VERSION 5.7 ;
  NOWIREEXTENSIONATPIN ON ;
  DIVIDERCHAR "/" ;
  BUSBITCHARS "[]" ;
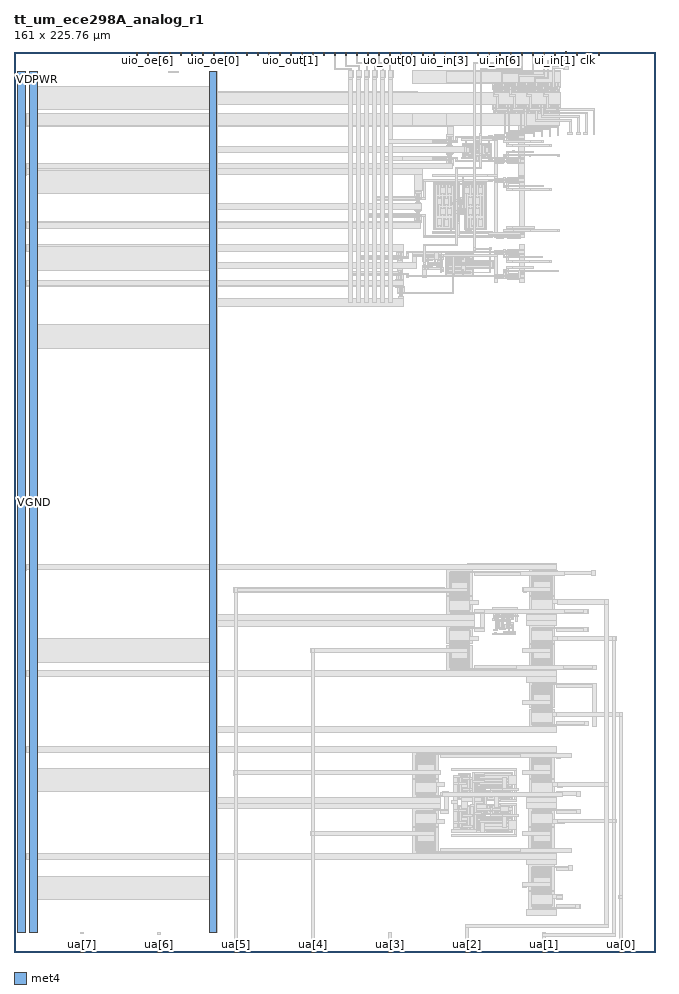
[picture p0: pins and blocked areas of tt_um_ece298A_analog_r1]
MACRO tt_um_ece298A_analog_r1
  CLASS BLOCK ;
  FOREIGN tt_um_ece298A_analog_r1 ;
  ORIGIN 0.000 0.000 ;
  SIZE 161.000 BY 225.760 ;
  PIN clk
    DIRECTION INPUT ;
    USE SIGNAL ;
    PORT
      LAYER met4 ;
        RECT 143.830 224.760 144.130 225.760 ;
    END
  END clk
  PIN ena
    DIRECTION INPUT ;
    USE SIGNAL ;
    PORT
      LAYER met4 ;
        RECT 146.590 224.760 146.890 225.760 ;
    END
  END ena
  PIN rst_n
    DIRECTION INPUT ;
    USE SIGNAL ;
    PORT
      LAYER met4 ;
        RECT 141.070 224.760 141.370 225.760 ;
    END
  END rst_n
  PIN ua[0]
    DIRECTION INOUT ;
    USE SIGNAL ;
    ANTENNADIFFAREA 15.520000 ;
    PORT
      LAYER met4 ;
        RECT 151.810 0.000 152.710 1.000 ;
    END
  END ua[0]
  PIN ua[1]
    DIRECTION INOUT ;
    USE SIGNAL ;
    ANTENNADIFFAREA 31.039999 ;
    PORT
      LAYER met4 ;
        RECT 132.490 0.000 133.390 1.000 ;
    END
  END ua[1]
  PIN ua[2]
    DIRECTION INOUT ;
    USE SIGNAL ;
    ANTENNADIFFAREA 31.039999 ;
    PORT
      LAYER met4 ;
        RECT 113.170 0.000 114.070 1.000 ;
    END
  END ua[2]
  PIN ua[3]
    DIRECTION INOUT ;
    USE SIGNAL ;
    PORT
      LAYER met4 ;
        RECT 93.850 0.000 94.750 1.000 ;
    END
  END ua[3]
  PIN ua[4]
    DIRECTION INOUT ;
    USE SIGNAL ;
    ANTENNADIFFAREA 26.400000 ;
    PORT
      LAYER met4 ;
        RECT 74.530 0.000 75.430 1.000 ;
    END
  END ua[4]
  PIN ua[5]
    DIRECTION INOUT ;
    USE SIGNAL ;
    ANTENNADIFFAREA 26.400000 ;
    PORT
      LAYER met4 ;
        RECT 55.210 0.000 56.110 1.000 ;
    END
  END ua[5]
  PIN ua[6]
    DIRECTION INOUT ;
    USE SIGNAL ;
    PORT
      LAYER met4 ;
        RECT 35.890 0.000 36.790 1.000 ;
    END
  END ua[6]
  PIN ua[7]
    DIRECTION INOUT ;
    USE SIGNAL ;
    PORT
      LAYER met4 ;
        RECT 16.570 0.000 17.470 1.000 ;
    END
  END ua[7]
  PIN ui_in[0]
    DIRECTION INPUT ;
    USE SIGNAL ;
    PORT
      LAYER met4 ;
        RECT 138.310 224.780 138.610 225.780 ;
    END
  END ui_in[0]
  PIN ui_in[1]
    DIRECTION INPUT ;
    USE SIGNAL ;
    ANTENNAGATEAREA 1.980000 ;
    PORT
      LAYER met4 ;
        RECT 135.550 224.760 135.850 225.760 ;
    END
  END ui_in[1]
  PIN ui_in[2]
    DIRECTION INPUT ;
    USE SIGNAL ;
    ANTENNAGATEAREA 1.980000 ;
    PORT
      LAYER met4 ;
        RECT 132.790 224.760 133.090 225.760 ;
    END
  END ui_in[2]
  PIN ui_in[3]
    DIRECTION INPUT ;
    USE SIGNAL ;
    ANTENNAGATEAREA 1.980000 ;
    PORT
      LAYER met4 ;
        RECT 130.030 224.760 130.330 225.760 ;
    END
  END ui_in[3]
  PIN ui_in[4]
    DIRECTION INPUT ;
    USE SIGNAL ;
    ANTENNAGATEAREA 0.951600 ;
    PORT
      LAYER met4 ;
        RECT 127.270 224.760 127.570 225.760 ;
    END
  END ui_in[4]
  PIN ui_in[5]
    DIRECTION INPUT ;
    USE SIGNAL ;
    ANTENNAGATEAREA 4.008000 ;
    ANTENNADIFFAREA 25.557999 ;
    PORT
      LAYER met4 ;
        RECT 124.510 224.760 124.810 225.760 ;
    END
  END ui_in[5]
  PIN ui_in[6]
    DIRECTION INPUT ;
    USE SIGNAL ;
    PORT
      LAYER met4 ;
        RECT 121.750 224.760 122.050 225.760 ;
    END
  END ui_in[6]
  PIN ui_in[7]
    DIRECTION INPUT ;
    USE SIGNAL ;
    PORT
      LAYER met4 ;
        RECT 118.990 224.760 119.290 225.760 ;
    END
  END ui_in[7]
  PIN uio_in[0]
    DIRECTION INPUT ;
    USE SIGNAL ;
    PORT
      LAYER met4 ;
        RECT 116.230 224.760 116.530 225.760 ;
    END
  END uio_in[0]
  PIN uio_in[1]
    DIRECTION INPUT ;
    USE SIGNAL ;
    PORT
      LAYER met4 ;
        RECT 113.470 224.760 113.770 225.760 ;
    END
  END uio_in[1]
  PIN uio_in[2]
    DIRECTION INPUT ;
    USE SIGNAL ;
    PORT
      LAYER met4 ;
        RECT 110.710 224.760 111.010 225.760 ;
    END
  END uio_in[2]
  PIN uio_in[3]
    DIRECTION INPUT ;
    USE SIGNAL ;
    PORT
      LAYER met4 ;
        RECT 107.950 224.760 108.250 225.760 ;
    END
  END uio_in[3]
  PIN uio_in[4]
    DIRECTION INPUT ;
    USE SIGNAL ;
    PORT
      LAYER met4 ;
        RECT 105.190 224.760 105.490 225.760 ;
    END
  END uio_in[4]
  PIN uio_in[5]
    DIRECTION INPUT ;
    USE SIGNAL ;
    PORT
      LAYER met4 ;
        RECT 102.430 224.760 102.730 225.760 ;
    END
  END uio_in[5]
  PIN uio_in[6]
    DIRECTION INPUT ;
    USE SIGNAL ;
    PORT
      LAYER met4 ;
        RECT 99.670 224.760 99.970 225.760 ;
    END
  END uio_in[6]
  PIN uio_in[7]
    DIRECTION INPUT ;
    USE SIGNAL ;
    PORT
      LAYER met4 ;
        RECT 96.910 224.760 97.210 225.760 ;
    END
  END uio_in[7]
  PIN uio_oe[0]
    DIRECTION OUTPUT ;
    USE SIGNAL ;
    PORT
      LAYER met4 ;
        RECT 49.990 224.760 50.290 225.760 ;
    END
  END uio_oe[0]
  PIN uio_oe[1]
    DIRECTION OUTPUT ;
    USE SIGNAL ;
    PORT
      LAYER met4 ;
        RECT 47.230 224.760 47.530 225.760 ;
    END
  END uio_oe[1]
  PIN uio_oe[2]
    DIRECTION OUTPUT ;
    USE SIGNAL ;
    PORT
      LAYER met4 ;
        RECT 44.470 224.760 44.770 225.760 ;
    END
  END uio_oe[2]
  PIN uio_oe[3]
    DIRECTION OUTPUT ;
    USE SIGNAL ;
    PORT
      LAYER met4 ;
        RECT 41.710 224.760 42.010 225.760 ;
    END
  END uio_oe[3]
  PIN uio_oe[4]
    DIRECTION OUTPUT ;
    USE SIGNAL ;
    PORT
      LAYER met4 ;
        RECT 38.950 224.760 39.250 225.760 ;
    END
  END uio_oe[4]
  PIN uio_oe[5]
    DIRECTION OUTPUT ;
    USE SIGNAL ;
    PORT
      LAYER met4 ;
        RECT 36.190 224.760 36.490 225.760 ;
    END
  END uio_oe[5]
  PIN uio_oe[6]
    DIRECTION OUTPUT ;
    USE SIGNAL ;
    PORT
      LAYER met4 ;
        RECT 33.430 224.760 33.730 225.760 ;
    END
  END uio_oe[6]
  PIN uio_oe[7]
    DIRECTION OUTPUT ;
    USE SIGNAL ;
    PORT
      LAYER met4 ;
        RECT 30.670 224.760 30.970 225.760 ;
    END
  END uio_oe[7]
  PIN uio_out[0]
    DIRECTION OUTPUT ;
    USE SIGNAL ;
    PORT
      LAYER met4 ;
        RECT 72.070 224.760 72.370 225.760 ;
    END
  END uio_out[0]
  PIN uio_out[1]
    DIRECTION OUTPUT ;
    USE SIGNAL ;
    PORT
      LAYER met4 ;
        RECT 69.310 224.760 69.610 225.760 ;
    END
  END uio_out[1]
  PIN uio_out[2]
    DIRECTION OUTPUT ;
    USE SIGNAL ;
    PORT
      LAYER met4 ;
        RECT 66.550 224.760 66.850 225.760 ;
    END
  END uio_out[2]
  PIN uio_out[3]
    DIRECTION OUTPUT ;
    USE SIGNAL ;
    PORT
      LAYER met4 ;
        RECT 63.790 224.760 64.090 225.760 ;
    END
  END uio_out[3]
  PIN uio_out[4]
    DIRECTION OUTPUT ;
    USE SIGNAL ;
    PORT
      LAYER met4 ;
        RECT 61.030 224.760 61.330 225.760 ;
    END
  END uio_out[4]
  PIN uio_out[5]
    DIRECTION OUTPUT ;
    USE SIGNAL ;
    PORT
      LAYER met4 ;
        RECT 58.270 224.760 58.570 225.760 ;
    END
  END uio_out[5]
  PIN uio_out[6]
    DIRECTION OUTPUT ;
    USE SIGNAL ;
    PORT
      LAYER met4 ;
        RECT 55.510 224.760 55.810 225.760 ;
    END
  END uio_out[6]
  PIN uio_out[7]
    DIRECTION OUTPUT ;
    USE SIGNAL ;
    PORT
      LAYER met4 ;
        RECT 52.750 224.760 53.050 225.760 ;
    END
  END uio_out[7]
  PIN uo_out[0]
    DIRECTION OUTPUT ;
    USE SIGNAL ;
    ANTENNADIFFAREA 0.429000 ;
    PORT
      LAYER met4 ;
        RECT 94.150 224.760 94.450 225.760 ;
    END
  END uo_out[0]
  PIN uo_out[1]
    DIRECTION OUTPUT ;
    USE SIGNAL ;
    ANTENNADIFFAREA 0.429000 ;
    PORT
      LAYER met4 ;
        RECT 91.390 224.760 91.690 225.760 ;
    END
  END uo_out[1]
  PIN uo_out[2]
    DIRECTION OUTPUT ;
    USE SIGNAL ;
    ANTENNADIFFAREA 0.429000 ;
    PORT
      LAYER met4 ;
        RECT 88.630 224.760 88.930 225.760 ;
    END
  END uo_out[2]
  PIN uo_out[3]
    DIRECTION OUTPUT ;
    USE SIGNAL ;
    ANTENNADIFFAREA 0.429000 ;
    PORT
      LAYER met4 ;
        RECT 85.870 224.760 86.170 225.760 ;
    END
  END uo_out[3]
  PIN uo_out[4]
    DIRECTION OUTPUT ;
    USE SIGNAL ;
    ANTENNADIFFAREA 0.429000 ;
    PORT
      LAYER met4 ;
        RECT 83.110 224.760 83.410 225.760 ;
    END
  END uo_out[4]
  PIN uo_out[5]
    DIRECTION OUTPUT ;
    USE SIGNAL ;
    ANTENNADIFFAREA 0.429000 ;
    PORT
      LAYER met4 ;
        RECT 80.350 224.760 80.650 225.760 ;
    END
  END uo_out[5]
  PIN uo_out[6]
    DIRECTION OUTPUT ;
    USE SIGNAL ;
    PORT
      LAYER met4 ;
        RECT 77.590 224.760 77.890 225.760 ;
    END
  END uo_out[6]
  PIN uo_out[7]
    DIRECTION OUTPUT ;
    USE SIGNAL ;
    PORT
      LAYER met4 ;
        RECT 74.830 224.760 75.130 225.760 ;
    END
  END uo_out[7]
  PIN VDPWR
    DIRECTION INOUT ;
    USE POWER ;
    PORT
      LAYER met4 ;
        RECT 1.000 5.000 3.000 220.760 ;
    END
  END VDPWR
  PIN VGND
    DIRECTION INOUT ;
    USE GROUND ;
    PORT
      LAYER met4 ;
        RECT 4.000 5.000 5.920 220.760 ;
    END
    PORT
      LAYER met4 ;
        RECT 48.990 5.000 50.910 220.760 ;
    END
  END VGND
  OBS
      LAYER nwell ;
        RECT 120.070 216.845 137.010 218.450 ;
      LAYER pwell ;
        RECT 120.430 215.645 124.300 216.555 ;
        RECT 124.570 215.645 128.440 216.555 ;
        RECT 128.710 215.645 132.580 216.555 ;
        RECT 132.850 215.645 136.720 216.555 ;
        RECT 120.430 215.625 120.575 215.645 ;
        RECT 124.570 215.625 124.715 215.645 ;
        RECT 128.710 215.625 128.855 215.645 ;
        RECT 132.850 215.625 132.995 215.645 ;
        RECT 120.405 215.455 120.575 215.625 ;
        RECT 124.545 215.455 124.715 215.625 ;
        RECT 128.685 215.455 128.855 215.625 ;
        RECT 132.825 215.455 132.995 215.625 ;
      LAYER nwell ;
        RECT 120.070 211.415 137.010 213.020 ;
      LAYER pwell ;
        RECT 120.360 210.215 124.230 211.125 ;
        RECT 124.500 210.215 128.370 211.125 ;
        RECT 128.640 210.215 132.510 211.125 ;
        RECT 132.780 210.215 136.650 211.125 ;
        RECT 124.085 210.195 124.230 210.215 ;
        RECT 128.225 210.195 128.370 210.215 ;
        RECT 132.365 210.195 132.510 210.215 ;
        RECT 136.505 210.195 136.650 210.215 ;
        RECT 124.085 210.025 124.255 210.195 ;
        RECT 128.225 210.025 128.395 210.195 ;
        RECT 132.365 210.025 132.535 210.195 ;
        RECT 136.505 210.025 136.675 210.195 ;
      LAYER nwell ;
        RECT 108.420 203.475 110.180 205.080 ;
      LAYER pwell ;
        RECT 115.805 203.380 116.510 204.185 ;
      LAYER nwell ;
        RECT 123.680 203.730 126.490 205.340 ;
      LAYER pwell ;
        RECT 108.850 202.275 109.780 203.185 ;
        RECT 109.675 202.255 109.780 202.275 ;
        RECT 109.675 202.085 109.845 202.255 ;
        RECT 109.675 200.205 109.845 200.375 ;
        RECT 109.675 200.185 109.780 200.205 ;
        RECT 108.850 199.275 109.780 200.185 ;
      LAYER nwell ;
        RECT 112.560 199.670 115.170 202.830 ;
      LAYER pwell ;
        RECT 115.410 199.380 117.110 203.380 ;
      LAYER nwell ;
        RECT 117.260 199.670 119.870 202.830 ;
        RECT 108.420 197.380 110.180 198.985 ;
        RECT 123.680 197.720 126.490 199.330 ;
        RECT 100.450 189.165 102.210 190.770 ;
      LAYER pwell ;
        RECT 100.880 187.965 101.810 188.875 ;
        RECT 101.705 187.945 101.810 187.965 ;
        RECT 101.705 187.775 101.875 187.945 ;
        RECT 101.705 185.895 101.875 186.065 ;
        RECT 101.705 185.875 101.810 185.895 ;
        RECT 100.880 184.965 101.810 185.875 ;
      LAYER nwell ;
        RECT 100.450 183.070 102.210 184.675 ;
      LAYER pwell ;
        RECT 105.330 181.110 110.660 192.990 ;
        RECT 110.780 188.240 112.650 189.260 ;
        RECT 110.780 187.490 112.980 188.240 ;
        RECT 110.780 184.990 112.650 187.490 ;
        RECT 113.130 181.110 118.460 192.990 ;
      LAYER nwell ;
        RECT 123.730 192.770 126.540 194.380 ;
      LAYER pwell ;
        RECT 113.180 180.895 114.880 181.110 ;
      LAYER nwell ;
        RECT 123.730 178.890 126.540 180.500 ;
        RECT 96.000 174.415 97.760 176.020 ;
      LAYER pwell ;
        RECT 96.430 173.215 97.360 174.125 ;
        RECT 97.255 173.195 97.360 173.215 ;
        RECT 97.255 173.025 97.425 173.195 ;
        RECT 97.255 171.145 97.425 171.315 ;
        RECT 97.255 171.125 97.360 171.145 ;
      LAYER nwell ;
        RECT 106.140 171.130 107.400 174.110 ;
      LAYER pwell ;
        RECT 108.160 173.580 115.260 175.680 ;
      LAYER nwell ;
        RECT 123.730 174.700 126.540 176.310 ;
      LAYER pwell ;
        RECT 108.160 171.470 120.260 173.580 ;
        RECT 96.430 170.215 97.360 171.125 ;
      LAYER nwell ;
        RECT 96.000 168.320 97.760 169.925 ;
      LAYER pwell ;
        RECT 108.160 169.370 115.260 171.470 ;
      LAYER nwell ;
        RECT 123.730 168.690 126.540 170.300 ;
        RECT 96.220 165.415 97.980 167.020 ;
      LAYER pwell ;
        RECT 96.620 164.215 97.550 165.125 ;
        RECT 96.620 164.195 96.725 164.215 ;
        RECT 96.555 164.025 96.725 164.195 ;
      LAYER nwell ;
        RECT 108.570 89.370 115.040 96.210 ;
        RECT 129.210 89.410 135.680 96.250 ;
      LAYER pwell ;
        RECT 108.570 84.270 115.040 89.060 ;
      LAYER nwell ;
        RECT 121.340 86.300 122.340 86.500 ;
        RECT 121.340 86.220 125.900 86.300 ;
        RECT 120.900 85.860 125.900 86.220 ;
        RECT 120.380 84.420 125.900 85.860 ;
        RECT 120.380 84.180 123.060 84.420 ;
      LAYER pwell ;
        RECT 129.210 84.310 135.680 89.100 ;
      LAYER nwell ;
        RECT 120.380 83.940 122.740 84.180 ;
      LAYER pwell ;
        RECT 108.560 77.310 115.030 82.100 ;
        RECT 129.200 77.350 135.670 82.140 ;
      LAYER nwell ;
        RECT 108.560 70.160 115.030 77.000 ;
        RECT 129.200 70.200 135.670 77.040 ;
        RECT 129.200 61.210 135.670 68.050 ;
      LAYER pwell ;
        RECT 129.200 56.110 135.670 60.900 ;
      LAYER nwell ;
        RECT 100.080 43.540 106.550 50.380 ;
      LAYER pwell ;
        RECT 100.080 38.440 106.550 43.230 ;
      LAYER nwell ;
        RECT 111.420 38.190 114.530 44.900 ;
        RECT 115.840 41.060 125.030 45.100 ;
        RECT 129.190 43.590 135.660 50.430 ;
      LAYER pwell ;
        RECT 100.070 31.480 106.540 36.270 ;
      LAYER nwell ;
        RECT 100.070 24.330 106.540 31.170 ;
        RECT 111.420 30.090 114.530 36.800 ;
      LAYER pwell ;
        RECT 115.160 34.300 118.230 40.670 ;
        RECT 118.470 38.000 120.930 40.600 ;
        RECT 121.070 37.750 125.030 40.600 ;
        RECT 129.190 38.490 135.660 43.280 ;
        RECT 118.470 34.500 120.930 37.100 ;
        RECT 121.070 34.450 125.030 37.300 ;
      LAYER nwell ;
        RECT 115.840 29.860 125.030 33.900 ;
      LAYER pwell ;
        RECT 129.180 31.530 135.650 36.320 ;
      LAYER nwell ;
        RECT 129.180 24.380 135.650 31.220 ;
        RECT 129.180 15.390 135.650 22.230 ;
      LAYER pwell ;
        RECT 129.180 10.290 135.650 15.080 ;
      LAYER li1 ;
        RECT 120.260 218.175 136.820 218.345 ;
        RECT 120.515 217.375 120.770 218.175 ;
        RECT 120.940 217.205 121.270 218.005 ;
        RECT 121.440 217.375 121.610 218.175 ;
        RECT 121.780 217.205 122.110 218.005 ;
        RECT 122.280 217.375 122.450 218.175 ;
        RECT 122.620 217.205 122.950 218.005 ;
        RECT 123.120 217.375 123.290 218.175 ;
        RECT 123.460 217.205 123.790 218.005 ;
        RECT 123.960 217.375 124.260 218.175 ;
        RECT 124.655 217.375 124.910 218.175 ;
        RECT 125.080 217.205 125.410 218.005 ;
        RECT 125.580 217.375 125.750 218.175 ;
        RECT 125.920 217.205 126.250 218.005 ;
        RECT 126.420 217.375 126.590 218.175 ;
        RECT 126.760 217.205 127.090 218.005 ;
        RECT 127.260 217.375 127.430 218.175 ;
        RECT 127.600 217.205 127.930 218.005 ;
        RECT 128.100 217.375 128.400 218.175 ;
        RECT 128.795 217.375 129.050 218.175 ;
        RECT 129.220 217.205 129.550 218.005 ;
        RECT 129.720 217.375 129.890 218.175 ;
        RECT 130.060 217.205 130.390 218.005 ;
        RECT 130.560 217.375 130.730 218.175 ;
        RECT 130.900 217.205 131.230 218.005 ;
        RECT 131.400 217.375 131.570 218.175 ;
        RECT 131.740 217.205 132.070 218.005 ;
        RECT 132.240 217.375 132.540 218.175 ;
        RECT 132.935 217.375 133.190 218.175 ;
        RECT 133.360 217.205 133.690 218.005 ;
        RECT 133.860 217.375 134.030 218.175 ;
        RECT 134.200 217.205 134.530 218.005 ;
        RECT 134.700 217.375 134.870 218.175 ;
        RECT 135.040 217.205 135.370 218.005 ;
        RECT 135.540 217.375 135.710 218.175 ;
        RECT 135.880 217.205 136.210 218.005 ;
        RECT 136.380 217.375 136.680 218.175 ;
        RECT 120.345 217.040 124.315 217.205 ;
        RECT 124.485 217.040 128.455 217.205 ;
        RECT 128.625 217.040 132.595 217.205 ;
        RECT 132.765 217.040 136.735 217.205 ;
        RECT 120.160 217.035 136.735 217.040 ;
        RECT 120.160 216.445 120.690 217.035 ;
        RECT 120.940 216.615 123.795 216.865 ;
        RECT 123.995 216.445 124.830 217.035 ;
        RECT 125.080 216.615 127.935 216.865 ;
        RECT 128.135 216.445 128.970 217.035 ;
        RECT 129.220 216.615 132.075 216.865 ;
        RECT 132.275 216.445 133.110 217.035 ;
        RECT 133.360 216.615 136.215 216.865 ;
        RECT 136.415 216.445 136.735 217.035 ;
        RECT 120.160 216.440 136.735 216.445 ;
        RECT 120.345 216.255 124.315 216.440 ;
        RECT 124.485 216.255 128.455 216.440 ;
        RECT 128.625 216.255 132.595 216.440 ;
        RECT 132.765 216.255 136.735 216.440 ;
        RECT 120.515 215.625 120.770 216.085 ;
        RECT 120.940 215.795 121.270 216.255 ;
        RECT 121.440 215.625 121.610 216.085 ;
        RECT 121.780 215.795 122.110 216.255 ;
        RECT 122.280 215.625 122.450 216.085 ;
        RECT 122.620 215.795 122.950 216.255 ;
        RECT 123.120 215.625 123.290 216.085 ;
        RECT 123.460 215.795 123.790 216.255 ;
        RECT 123.960 215.625 124.265 216.085 ;
        RECT 124.655 215.625 124.910 216.085 ;
        RECT 125.080 215.795 125.410 216.255 ;
        RECT 125.580 215.625 125.750 216.085 ;
        RECT 125.920 215.795 126.250 216.255 ;
        RECT 126.420 215.625 126.590 216.085 ;
        RECT 126.760 215.795 127.090 216.255 ;
        RECT 127.260 215.625 127.430 216.085 ;
        RECT 127.600 215.795 127.930 216.255 ;
        RECT 128.100 215.625 128.405 216.085 ;
        RECT 128.795 215.625 129.050 216.085 ;
        RECT 129.220 215.795 129.550 216.255 ;
        RECT 129.720 215.625 129.890 216.085 ;
        RECT 130.060 215.795 130.390 216.255 ;
        RECT 130.560 215.625 130.730 216.085 ;
        RECT 130.900 215.795 131.230 216.255 ;
        RECT 131.400 215.625 131.570 216.085 ;
        RECT 131.740 215.795 132.070 216.255 ;
        RECT 132.240 215.625 132.545 216.085 ;
        RECT 132.935 215.625 133.190 216.085 ;
        RECT 133.360 215.795 133.690 216.255 ;
        RECT 133.860 215.625 134.030 216.085 ;
        RECT 134.200 215.795 134.530 216.255 ;
        RECT 134.700 215.625 134.870 216.085 ;
        RECT 135.040 215.795 135.370 216.255 ;
        RECT 135.540 215.625 135.710 216.085 ;
        RECT 135.880 215.795 136.210 216.255 ;
        RECT 136.380 215.625 136.685 216.085 ;
        RECT 120.260 215.455 136.820 215.625 ;
        RECT 120.260 212.745 136.820 212.915 ;
        RECT 120.400 211.945 120.700 212.745 ;
        RECT 120.870 211.775 121.200 212.575 ;
        RECT 121.370 211.945 121.540 212.745 ;
        RECT 121.710 211.775 122.040 212.575 ;
        RECT 122.210 211.945 122.380 212.745 ;
        RECT 122.550 211.775 122.880 212.575 ;
        RECT 123.050 211.945 123.220 212.745 ;
        RECT 123.390 211.775 123.720 212.575 ;
        RECT 123.890 211.945 124.145 212.745 ;
        RECT 124.540 211.945 124.840 212.745 ;
        RECT 125.010 211.775 125.340 212.575 ;
        RECT 125.510 211.945 125.680 212.745 ;
        RECT 125.850 211.775 126.180 212.575 ;
        RECT 126.350 211.945 126.520 212.745 ;
        RECT 126.690 211.775 127.020 212.575 ;
        RECT 127.190 211.945 127.360 212.745 ;
        RECT 127.530 211.775 127.860 212.575 ;
        RECT 128.030 211.945 128.285 212.745 ;
        RECT 128.680 211.945 128.980 212.745 ;
        RECT 129.150 211.775 129.480 212.575 ;
        RECT 129.650 211.945 129.820 212.745 ;
        RECT 129.990 211.775 130.320 212.575 ;
        RECT 130.490 211.945 130.660 212.745 ;
        RECT 130.830 211.775 131.160 212.575 ;
        RECT 131.330 211.945 131.500 212.745 ;
        RECT 131.670 211.775 132.000 212.575 ;
        RECT 132.170 211.945 132.425 212.745 ;
        RECT 132.820 211.945 133.120 212.745 ;
        RECT 133.290 211.775 133.620 212.575 ;
        RECT 133.790 211.945 133.960 212.745 ;
        RECT 134.130 211.775 134.460 212.575 ;
        RECT 134.630 211.945 134.800 212.745 ;
        RECT 134.970 211.775 135.300 212.575 ;
        RECT 135.470 211.945 135.640 212.745 ;
        RECT 135.810 211.775 136.140 212.575 ;
        RECT 136.310 211.945 136.565 212.745 ;
        RECT 120.345 211.610 124.315 211.775 ;
        RECT 124.485 211.610 128.455 211.775 ;
        RECT 128.625 211.610 132.595 211.775 ;
        RECT 132.765 211.610 136.735 211.775 ;
        RECT 120.345 211.605 136.920 211.610 ;
        RECT 120.345 211.015 120.665 211.605 ;
        RECT 120.865 211.185 123.720 211.435 ;
        RECT 123.970 211.015 124.805 211.605 ;
        RECT 125.005 211.185 127.860 211.435 ;
        RECT 128.110 211.015 128.945 211.605 ;
        RECT 129.145 211.185 132.000 211.435 ;
        RECT 132.250 211.015 133.085 211.605 ;
        RECT 133.285 211.185 136.140 211.435 ;
        RECT 136.390 211.015 136.920 211.605 ;
        RECT 120.345 211.010 136.920 211.015 ;
        RECT 120.345 210.825 124.315 211.010 ;
        RECT 124.485 210.825 128.455 211.010 ;
        RECT 128.625 210.825 132.595 211.010 ;
        RECT 132.765 210.825 136.735 211.010 ;
        RECT 120.395 210.195 120.700 210.655 ;
        RECT 120.870 210.365 121.200 210.825 ;
        RECT 121.370 210.195 121.540 210.655 ;
        RECT 121.710 210.365 122.040 210.825 ;
        RECT 122.210 210.195 122.380 210.655 ;
        RECT 122.550 210.365 122.880 210.825 ;
        RECT 123.050 210.195 123.220 210.655 ;
        RECT 123.390 210.365 123.720 210.825 ;
        RECT 123.890 210.195 124.145 210.655 ;
        RECT 124.535 210.195 124.840 210.655 ;
        RECT 125.010 210.365 125.340 210.825 ;
        RECT 125.510 210.195 125.680 210.655 ;
        RECT 125.850 210.365 126.180 210.825 ;
        RECT 126.350 210.195 126.520 210.655 ;
        RECT 126.690 210.365 127.020 210.825 ;
        RECT 127.190 210.195 127.360 210.655 ;
        RECT 127.530 210.365 127.860 210.825 ;
        RECT 128.030 210.195 128.285 210.655 ;
        RECT 128.675 210.195 128.980 210.655 ;
        RECT 129.150 210.365 129.480 210.825 ;
        RECT 129.650 210.195 129.820 210.655 ;
        RECT 129.990 210.365 130.320 210.825 ;
        RECT 130.490 210.195 130.660 210.655 ;
        RECT 130.830 210.365 131.160 210.825 ;
        RECT 131.330 210.195 131.500 210.655 ;
        RECT 131.670 210.365 132.000 210.825 ;
        RECT 132.170 210.195 132.425 210.655 ;
        RECT 132.815 210.195 133.120 210.655 ;
        RECT 133.290 210.365 133.620 210.825 ;
        RECT 133.790 210.195 133.960 210.655 ;
        RECT 134.130 210.365 134.460 210.825 ;
        RECT 134.630 210.195 134.800 210.655 ;
        RECT 134.970 210.365 135.300 210.825 ;
        RECT 135.470 210.195 135.640 210.655 ;
        RECT 135.810 210.365 136.140 210.825 ;
        RECT 136.310 210.195 136.565 210.655 ;
        RECT 120.260 210.025 136.820 210.195 ;
        RECT 108.610 204.805 109.990 204.975 ;
        RECT 121.660 204.910 122.700 205.080 ;
        RECT 108.940 203.655 109.270 204.635 ;
        RECT 109.440 203.665 109.650 204.805 ;
        RECT 121.660 204.430 122.700 204.600 ;
        RECT 108.940 203.520 109.170 203.655 ;
        RECT 115.960 203.630 116.410 204.080 ;
        RECT 121.660 203.950 122.700 204.120 ;
        RECT 122.870 204.035 123.040 204.995 ;
        RECT 123.775 204.055 123.945 205.015 ;
        RECT 124.160 204.930 126.200 205.100 ;
        RECT 124.160 204.450 126.200 204.620 ;
        RECT 124.160 203.970 126.200 204.140 ;
        RECT 108.590 203.190 109.170 203.520 ;
        RECT 109.340 203.480 109.670 203.485 ;
        RECT 109.890 203.480 110.190 203.510 ;
        RECT 109.340 203.250 110.190 203.480 ;
        RECT 109.340 203.245 109.670 203.250 ;
        RECT 109.890 203.220 110.190 203.250 ;
        RECT 108.940 203.055 109.170 203.190 ;
        RECT 108.940 202.425 109.270 203.055 ;
        RECT 109.440 202.255 109.670 203.075 ;
        RECT 112.740 202.480 114.990 202.650 ;
        RECT 108.610 202.085 109.990 202.255 ;
        RECT 108.610 200.205 109.990 200.375 ;
        RECT 108.940 199.405 109.270 200.035 ;
        RECT 108.940 199.270 109.170 199.405 ;
        RECT 109.440 199.385 109.670 200.205 ;
        RECT 112.740 200.020 112.910 202.480 ;
        RECT 113.250 201.980 113.420 201.995 ;
        RECT 113.200 200.510 113.450 201.980 ;
        RECT 113.635 201.910 114.095 202.080 ;
        RECT 113.250 200.505 113.420 200.510 ;
        RECT 113.635 200.420 114.095 200.590 ;
        RECT 114.310 200.505 114.480 201.995 ;
        RECT 114.820 200.020 114.990 202.480 ;
        RECT 115.490 202.435 115.660 202.975 ;
        RECT 115.830 202.890 116.620 203.060 ;
        RECT 115.830 202.350 116.620 202.520 ;
        RECT 116.790 202.435 116.960 202.975 ;
        RECT 117.440 202.480 119.690 202.650 ;
        RECT 116.300 201.730 116.630 201.900 ;
        RECT 115.570 201.020 115.740 201.560 ;
        RECT 116.110 201.020 116.280 201.560 ;
        RECT 116.650 201.020 116.820 201.560 ;
        RECT 115.760 200.680 116.090 200.850 ;
        RECT 112.740 199.850 114.990 200.020 ;
        RECT 115.480 199.755 115.650 200.295 ;
        RECT 115.820 200.210 116.610 200.380 ;
        RECT 115.820 199.670 116.610 199.840 ;
        RECT 116.780 199.755 116.950 200.295 ;
        RECT 117.440 200.020 117.610 202.480 ;
        RECT 117.950 200.505 118.120 201.995 ;
        RECT 118.335 201.910 118.795 202.080 ;
        RECT 118.335 200.420 118.795 200.590 ;
        RECT 119.010 200.505 119.180 201.995 ;
        RECT 119.520 200.020 119.690 202.480 ;
        RECT 117.440 199.850 119.690 200.020 ;
        RECT 108.590 198.940 109.170 199.270 ;
        RECT 109.340 199.210 109.670 199.215 ;
        RECT 109.890 199.210 110.190 199.240 ;
        RECT 109.340 198.980 110.190 199.210 ;
        RECT 109.340 198.975 109.670 198.980 ;
        RECT 109.890 198.950 110.190 198.980 ;
        RECT 108.940 198.805 109.170 198.940 ;
        RECT 121.660 198.900 122.700 199.070 ;
        RECT 108.940 197.825 109.270 198.805 ;
        RECT 109.440 197.655 109.650 198.795 ;
        RECT 121.660 198.420 122.700 198.590 ;
        RECT 121.660 197.940 122.700 198.110 ;
        RECT 122.870 198.025 123.040 198.985 ;
        RECT 123.775 198.045 123.945 199.005 ;
        RECT 124.160 198.920 126.200 199.090 ;
        RECT 124.160 198.440 126.200 198.610 ;
        RECT 124.160 197.960 126.200 198.130 ;
        RECT 108.610 197.485 109.990 197.655 ;
        RECT 121.710 193.950 122.750 194.120 ;
        RECT 121.710 193.470 122.750 193.640 ;
        RECT 121.710 192.990 122.750 193.160 ;
        RECT 122.920 193.075 123.090 194.035 ;
        RECT 123.825 193.095 123.995 194.055 ;
        RECT 124.210 193.970 126.250 194.140 ;
        RECT 124.210 193.490 126.250 193.660 ;
        RECT 124.210 193.010 126.250 193.180 ;
        RECT 105.510 192.640 110.480 192.810 ;
        RECT 100.640 190.495 102.020 190.665 ;
        RECT 100.970 189.345 101.300 190.325 ;
        RECT 101.470 189.355 101.680 190.495 ;
        RECT 100.970 189.210 101.200 189.345 ;
        RECT 100.620 188.880 101.200 189.210 ;
        RECT 101.370 189.170 101.700 189.175 ;
        RECT 101.920 189.170 102.220 189.200 ;
        RECT 101.370 188.940 102.220 189.170 ;
        RECT 101.370 188.935 101.700 188.940 ;
        RECT 101.920 188.910 102.220 188.940 ;
        RECT 100.970 188.745 101.200 188.880 ;
        RECT 100.970 188.115 101.300 188.745 ;
        RECT 101.470 187.945 101.700 188.765 ;
        RECT 100.640 187.775 102.020 187.945 ;
        RECT 100.640 185.895 102.020 186.065 ;
        RECT 100.970 185.095 101.300 185.725 ;
        RECT 100.970 184.960 101.200 185.095 ;
        RECT 101.470 185.075 101.700 185.895 ;
        RECT 100.620 184.630 101.200 184.960 ;
        RECT 101.370 184.900 101.700 184.905 ;
        RECT 101.920 184.900 102.220 184.930 ;
        RECT 101.370 184.670 102.220 184.900 ;
        RECT 101.370 184.665 101.700 184.670 ;
        RECT 101.920 184.640 102.220 184.670 ;
        RECT 100.970 184.495 101.200 184.630 ;
        RECT 100.970 183.515 101.300 184.495 ;
        RECT 101.470 183.345 101.680 184.485 ;
        RECT 100.640 183.175 102.020 183.345 ;
        RECT 105.510 181.460 105.680 192.640 ;
        RECT 110.130 192.590 110.480 192.640 ;
        RECT 110.295 192.390 110.480 192.590 ;
        RECT 106.160 190.000 106.510 192.160 ;
        RECT 106.990 190.000 107.340 192.160 ;
        RECT 107.820 190.000 108.170 192.160 ;
        RECT 108.650 190.000 109.000 192.160 ;
        RECT 109.480 190.000 109.830 192.160 ;
        RECT 106.160 187.310 106.510 189.470 ;
        RECT 106.990 187.310 107.340 189.470 ;
        RECT 107.820 187.310 108.170 189.470 ;
        RECT 108.650 187.310 109.000 189.470 ;
        RECT 109.480 187.310 109.830 189.470 ;
        RECT 106.160 184.630 106.510 186.790 ;
        RECT 106.990 184.630 107.340 186.790 ;
        RECT 107.820 184.630 108.170 186.790 ;
        RECT 108.650 184.630 109.000 186.790 ;
        RECT 109.480 184.630 109.830 186.790 ;
        RECT 106.160 181.940 106.510 184.100 ;
        RECT 106.990 181.940 107.340 184.100 ;
        RECT 107.820 181.940 108.170 184.100 ;
        RECT 108.650 181.940 109.000 184.100 ;
        RECT 109.480 181.940 109.830 184.100 ;
        RECT 110.310 181.460 110.480 192.390 ;
        RECT 113.310 192.640 118.280 192.810 ;
        RECT 113.310 192.620 113.730 192.640 ;
        RECT 113.310 192.490 113.500 192.620 ;
        RECT 110.910 188.305 111.080 188.845 ;
        RECT 111.250 188.760 112.040 188.930 ;
        RECT 111.250 188.220 112.040 188.390 ;
        RECT 112.210 188.305 112.380 188.845 ;
        RECT 111.620 187.540 111.950 187.710 ;
        RECT 112.380 187.640 112.830 188.090 ;
        RECT 110.890 186.830 111.060 187.370 ;
        RECT 111.430 186.830 111.600 187.370 ;
        RECT 111.970 186.830 112.140 187.370 ;
        RECT 111.080 186.490 111.410 186.660 ;
        RECT 110.910 185.355 111.080 185.895 ;
        RECT 111.250 185.810 112.040 185.980 ;
        RECT 111.250 185.270 112.040 185.440 ;
        RECT 112.210 185.355 112.380 185.895 ;
        RECT 105.510 181.290 110.480 181.460 ;
        RECT 113.310 181.460 113.480 192.490 ;
        RECT 113.960 190.000 114.310 192.160 ;
        RECT 114.790 190.000 115.140 192.160 ;
        RECT 115.620 190.000 115.970 192.160 ;
        RECT 116.450 190.000 116.800 192.160 ;
        RECT 117.280 190.000 117.630 192.160 ;
        RECT 113.960 187.310 114.310 189.470 ;
        RECT 114.790 187.310 115.140 189.470 ;
        RECT 115.620 187.310 115.970 189.470 ;
        RECT 116.450 187.310 116.800 189.470 ;
        RECT 117.280 187.310 117.630 189.470 ;
        RECT 113.960 184.630 114.310 186.790 ;
        RECT 114.790 184.630 115.140 186.790 ;
        RECT 115.620 184.630 115.970 186.790 ;
        RECT 116.450 184.630 116.800 186.790 ;
        RECT 117.280 184.630 117.630 186.790 ;
        RECT 113.960 181.940 114.310 184.100 ;
        RECT 114.790 181.940 115.140 184.100 ;
        RECT 115.620 181.940 115.970 184.100 ;
        RECT 116.450 181.940 116.800 184.100 ;
        RECT 117.280 181.940 117.630 184.100 ;
        RECT 118.110 181.460 118.280 192.640 ;
        RECT 113.310 181.290 118.280 181.460 ;
        RECT 121.710 180.070 122.750 180.240 ;
        RECT 121.710 179.590 122.750 179.760 ;
        RECT 121.710 179.110 122.750 179.280 ;
        RECT 122.920 179.195 123.090 180.155 ;
        RECT 123.825 179.215 123.995 180.175 ;
        RECT 124.210 180.090 126.250 180.260 ;
        RECT 124.210 179.610 126.250 179.780 ;
        RECT 124.210 179.130 126.250 179.300 ;
        RECT 96.190 175.745 97.570 175.915 ;
        RECT 121.710 175.880 122.750 176.050 ;
        RECT 96.520 174.595 96.850 175.575 ;
        RECT 97.020 174.605 97.230 175.745 ;
        RECT 108.340 175.330 115.080 175.500 ;
        RECT 121.710 175.400 122.750 175.570 ;
        RECT 96.520 174.460 96.750 174.595 ;
        RECT 96.170 174.130 96.750 174.460 ;
        RECT 96.920 174.420 97.250 174.425 ;
        RECT 97.470 174.420 97.770 174.450 ;
        RECT 96.920 174.190 97.770 174.420 ;
        RECT 96.920 174.185 97.250 174.190 ;
        RECT 97.470 174.160 97.770 174.190 ;
        RECT 96.520 173.995 96.750 174.130 ;
        RECT 96.520 173.365 96.850 173.995 ;
        RECT 97.020 173.195 97.250 174.015 ;
        RECT 102.540 173.890 102.820 174.110 ;
        RECT 102.600 173.670 102.780 173.890 ;
        RECT 103.240 173.850 105.720 174.030 ;
        RECT 103.240 173.670 103.420 173.850 ;
        RECT 102.520 173.250 102.820 173.670 ;
        RECT 103.180 173.250 103.480 173.670 ;
        RECT 103.730 173.610 103.960 173.670 ;
        RECT 104.200 173.610 105.040 173.670 ;
        RECT 103.730 173.430 105.040 173.610 ;
        RECT 96.190 173.025 97.570 173.195 ;
        RECT 102.840 172.550 103.160 172.930 ;
        RECT 103.730 172.290 103.960 173.430 ;
        RECT 104.200 173.370 105.040 173.430 ;
        RECT 104.200 172.890 105.040 172.950 ;
        RECT 105.540 172.890 105.720 173.850 ;
        RECT 108.340 173.920 108.510 175.330 ;
        RECT 108.850 174.460 109.020 174.790 ;
        RECT 109.190 174.760 114.230 174.930 ;
        RECT 109.190 174.320 114.230 174.490 ;
        RECT 114.400 174.460 114.570 174.790 ;
        RECT 114.910 173.920 115.080 175.330 ;
        RECT 121.710 174.920 122.750 175.090 ;
        RECT 122.920 175.005 123.090 175.965 ;
        RECT 123.825 175.025 123.995 175.985 ;
        RECT 124.210 175.900 126.250 176.070 ;
        RECT 124.210 175.420 126.250 175.590 ;
        RECT 124.210 174.940 126.250 175.110 ;
        RECT 108.340 173.750 115.080 173.920 ;
        RECT 106.320 173.610 106.740 173.670 ;
        RECT 106.980 173.610 107.260 173.670 ;
        RECT 106.320 173.430 107.260 173.610 ;
        RECT 106.320 173.370 106.740 173.430 ;
        RECT 106.320 172.890 106.740 172.950 ;
        RECT 104.200 172.710 106.740 172.890 ;
        RECT 104.200 172.650 105.040 172.710 ;
        RECT 105.300 172.490 105.480 172.710 ;
        RECT 106.320 172.650 106.740 172.710 ;
        RECT 104.200 172.290 105.040 172.350 ;
        RECT 102.520 171.810 102.820 172.230 ;
        RECT 103.180 171.810 103.480 172.230 ;
        RECT 103.730 172.110 105.040 172.290 ;
        RECT 105.220 172.170 105.560 172.490 ;
        RECT 105.780 172.170 106.120 172.490 ;
        RECT 106.320 172.290 106.740 172.350 ;
        RECT 106.980 172.290 107.260 173.430 ;
        RECT 108.850 173.400 109.020 173.750 ;
        RECT 103.730 171.810 103.960 172.110 ;
        RECT 104.200 172.050 105.040 172.110 ;
        RECT 102.600 171.570 102.780 171.810 ;
        RECT 103.240 171.570 103.420 171.810 ;
        RECT 104.200 171.570 105.040 171.630 ;
        RECT 105.860 171.570 106.040 172.170 ;
        RECT 106.320 172.110 107.260 172.290 ;
        RECT 106.320 172.050 106.740 172.110 ;
        RECT 106.980 171.810 107.260 172.110 ;
        RECT 108.340 173.230 120.080 173.400 ;
        RECT 108.340 171.820 108.510 173.230 ;
        RECT 108.850 172.360 109.020 172.690 ;
        RECT 109.190 172.660 119.230 172.830 ;
        RECT 109.190 172.220 119.230 172.390 ;
        RECT 119.400 172.360 119.570 172.690 ;
        RECT 119.910 171.820 120.080 173.230 ;
        RECT 108.340 171.650 120.080 171.820 ;
        RECT 106.320 171.570 106.740 171.630 ;
        RECT 102.540 171.350 102.820 171.570 ;
        RECT 103.240 171.390 106.740 171.570 ;
        RECT 104.200 171.330 105.040 171.390 ;
        RECT 106.320 171.330 106.740 171.390 ;
        RECT 96.190 171.145 97.570 171.315 ;
        RECT 108.850 171.300 109.020 171.650 ;
        RECT 96.520 170.345 96.850 170.975 ;
        RECT 96.520 170.210 96.750 170.345 ;
        RECT 97.020 170.325 97.250 171.145 ;
        RECT 108.340 171.130 115.080 171.300 ;
        RECT 96.170 169.880 96.750 170.210 ;
        RECT 96.920 170.150 97.250 170.155 ;
        RECT 97.470 170.150 97.770 170.180 ;
        RECT 96.920 169.920 97.770 170.150 ;
        RECT 96.920 169.915 97.250 169.920 ;
        RECT 97.470 169.890 97.770 169.920 ;
        RECT 96.520 169.745 96.750 169.880 ;
        RECT 96.520 168.765 96.850 169.745 ;
        RECT 97.020 168.595 97.230 169.735 ;
        RECT 108.340 169.720 108.510 171.130 ;
        RECT 108.850 170.260 109.020 170.590 ;
        RECT 109.190 170.560 114.230 170.730 ;
        RECT 109.190 170.120 114.230 170.290 ;
        RECT 114.400 170.260 114.570 170.590 ;
        RECT 114.910 169.720 115.080 171.130 ;
        RECT 121.710 169.870 122.750 170.040 ;
        RECT 108.340 169.550 115.080 169.720 ;
        RECT 121.710 169.390 122.750 169.560 ;
        RECT 121.710 168.910 122.750 169.080 ;
        RECT 122.920 168.995 123.090 169.955 ;
        RECT 123.825 169.015 123.995 169.975 ;
        RECT 124.210 169.890 126.250 170.060 ;
        RECT 124.210 169.410 126.250 169.580 ;
        RECT 124.210 168.930 126.250 169.100 ;
        RECT 96.190 168.425 97.570 168.595 ;
        RECT 96.410 166.745 97.790 166.915 ;
        RECT 96.750 165.605 96.960 166.745 ;
        RECT 97.130 165.595 97.460 166.575 ;
        RECT 97.230 165.460 97.460 165.595 ;
        RECT 96.210 165.420 96.510 165.450 ;
        RECT 96.730 165.420 97.060 165.425 ;
        RECT 96.210 165.190 97.060 165.420 ;
        RECT 96.210 165.160 96.510 165.190 ;
        RECT 96.730 165.185 97.060 165.190 ;
        RECT 97.230 165.130 97.810 165.460 ;
        RECT 96.730 164.195 96.960 165.015 ;
        RECT 97.230 164.995 97.460 165.130 ;
        RECT 97.130 164.365 97.460 164.995 ;
        RECT 96.410 164.025 97.790 164.195 ;
        RECT 109.150 95.860 114.460 96.030 ;
        RECT 129.790 95.900 135.100 96.070 ;
        RECT 109.405 95.345 114.205 95.515 ;
        RECT 130.045 95.385 134.845 95.555 ;
        RECT 109.320 90.090 109.490 95.130 ;
        RECT 109.800 90.090 109.970 95.130 ;
        RECT 110.280 90.090 110.450 95.130 ;
        RECT 110.760 90.090 110.930 95.130 ;
        RECT 111.240 90.090 111.410 95.130 ;
        RECT 111.720 90.090 111.890 95.130 ;
        RECT 112.200 90.090 112.370 95.130 ;
        RECT 112.680 90.090 112.850 95.130 ;
        RECT 113.160 90.090 113.330 95.130 ;
        RECT 113.640 90.090 113.810 95.130 ;
        RECT 114.120 90.090 114.290 95.130 ;
        RECT 129.960 90.130 130.130 95.170 ;
        RECT 130.440 90.130 130.610 95.170 ;
        RECT 130.920 90.130 131.090 95.170 ;
        RECT 131.400 90.130 131.570 95.170 ;
        RECT 131.880 90.130 132.050 95.170 ;
        RECT 132.360 90.130 132.530 95.170 ;
        RECT 132.840 90.130 133.010 95.170 ;
        RECT 133.320 90.130 133.490 95.170 ;
        RECT 133.800 90.130 133.970 95.170 ;
        RECT 134.280 90.130 134.450 95.170 ;
        RECT 134.760 90.130 134.930 95.170 ;
        RECT 109.320 85.300 109.490 88.340 ;
        RECT 109.800 85.300 109.970 88.340 ;
        RECT 110.280 85.300 110.450 88.340 ;
        RECT 110.760 85.300 110.930 88.340 ;
        RECT 111.240 85.300 111.410 88.340 ;
        RECT 111.720 85.300 111.890 88.340 ;
        RECT 112.200 85.300 112.370 88.340 ;
        RECT 112.680 85.300 112.850 88.340 ;
        RECT 113.160 85.300 113.330 88.340 ;
        RECT 113.640 85.300 113.810 88.340 ;
        RECT 114.120 85.300 114.290 88.340 ;
        RECT 121.660 85.940 122.020 86.300 ;
        RECT 109.405 84.960 114.205 85.130 ;
        RECT 109.150 84.450 114.460 84.620 ;
        RECT 120.660 84.380 121.020 85.660 ;
        RECT 121.260 84.380 121.620 85.660 ;
        RECT 121.900 84.380 122.260 85.660 ;
        RECT 122.500 84.380 122.860 85.660 ;
        RECT 123.140 84.620 123.500 85.660 ;
        RECT 123.740 84.620 124.100 85.660 ;
        RECT 124.380 84.620 124.740 85.660 ;
        RECT 124.980 84.620 125.340 85.660 ;
        RECT 120.940 83.780 121.340 84.180 ;
        RECT 122.180 83.780 122.580 84.180 ;
        RECT 123.420 84.020 123.820 84.420 ;
        RECT 124.660 84.020 125.060 84.420 ;
        RECT 120.100 83.460 120.460 83.540 ;
        RECT 121.140 83.460 121.500 83.540 ;
        RECT 120.100 83.260 121.500 83.460 ;
        RECT 120.100 83.180 120.460 83.260 ;
        RECT 121.140 83.180 121.500 83.260 ;
        RECT 122.180 83.140 122.580 83.540 ;
        RECT 123.140 83.300 123.500 83.820 ;
        RECT 123.740 83.300 124.100 83.820 ;
        RECT 124.380 83.300 124.740 83.820 ;
        RECT 124.980 83.300 125.340 83.820 ;
        RECT 125.900 82.980 126.260 86.380 ;
        RECT 129.960 85.340 130.130 88.380 ;
        RECT 130.440 85.340 130.610 88.380 ;
        RECT 130.920 85.340 131.090 88.380 ;
        RECT 131.400 85.340 131.570 88.380 ;
        RECT 131.880 85.340 132.050 88.380 ;
        RECT 132.360 85.340 132.530 88.380 ;
        RECT 132.840 85.340 133.010 88.380 ;
        RECT 133.320 85.340 133.490 88.380 ;
        RECT 133.800 85.340 133.970 88.380 ;
        RECT 134.280 85.340 134.450 88.380 ;
        RECT 134.760 85.340 134.930 88.380 ;
        RECT 130.045 85.000 134.845 85.170 ;
        RECT 129.790 84.490 135.100 84.660 ;
        RECT 109.140 81.750 114.450 81.920 ;
        RECT 109.395 81.240 114.195 81.410 ;
        RECT 120.660 81.140 121.020 82.940 ;
        RECT 121.260 81.140 121.620 82.940 ;
        RECT 121.900 81.140 122.260 82.940 ;
        RECT 122.500 81.140 122.860 82.940 ;
        RECT 123.420 82.580 123.820 82.660 ;
        RECT 124.660 82.580 125.060 82.660 ;
        RECT 123.420 82.380 125.060 82.580 ;
        RECT 123.420 82.260 123.820 82.380 ;
        RECT 124.660 82.260 125.060 82.380 ;
        RECT 123.140 81.140 123.500 82.060 ;
        RECT 123.740 81.140 124.100 82.060 ;
        RECT 124.380 81.140 124.740 82.060 ;
        RECT 124.980 81.140 125.340 82.060 ;
        RECT 129.780 81.790 135.090 81.960 ;
        RECT 130.035 81.280 134.835 81.450 ;
        RECT 109.310 78.030 109.480 81.070 ;
        RECT 109.790 78.030 109.960 81.070 ;
        RECT 110.270 78.030 110.440 81.070 ;
        RECT 110.750 78.030 110.920 81.070 ;
        RECT 111.230 78.030 111.400 81.070 ;
        RECT 111.710 78.030 111.880 81.070 ;
        RECT 112.190 78.030 112.360 81.070 ;
        RECT 112.670 78.030 112.840 81.070 ;
        RECT 113.150 78.030 113.320 81.070 ;
        RECT 113.630 78.030 113.800 81.070 ;
        RECT 114.110 78.030 114.280 81.070 ;
        RECT 120.940 80.540 121.340 80.940 ;
        RECT 120.500 79.580 121.100 80.180 ;
        RECT 122.860 80.140 125.900 80.500 ;
        RECT 129.950 78.070 130.120 81.110 ;
        RECT 130.430 78.070 130.600 81.110 ;
        RECT 130.910 78.070 131.080 81.110 ;
        RECT 131.390 78.070 131.560 81.110 ;
        RECT 131.870 78.070 132.040 81.110 ;
        RECT 132.350 78.070 132.520 81.110 ;
        RECT 132.830 78.070 133.000 81.110 ;
        RECT 133.310 78.070 133.480 81.110 ;
        RECT 133.790 78.070 133.960 81.110 ;
        RECT 134.270 78.070 134.440 81.110 ;
        RECT 134.750 78.070 134.920 81.110 ;
        RECT 109.310 71.240 109.480 76.280 ;
        RECT 109.790 71.240 109.960 76.280 ;
        RECT 110.270 71.240 110.440 76.280 ;
        RECT 110.750 71.240 110.920 76.280 ;
        RECT 111.230 71.240 111.400 76.280 ;
        RECT 111.710 71.240 111.880 76.280 ;
        RECT 112.190 71.240 112.360 76.280 ;
        RECT 112.670 71.240 112.840 76.280 ;
        RECT 113.150 71.240 113.320 76.280 ;
        RECT 113.630 71.240 113.800 76.280 ;
        RECT 114.110 71.240 114.280 76.280 ;
        RECT 129.950 71.280 130.120 76.320 ;
        RECT 130.430 71.280 130.600 76.320 ;
        RECT 130.910 71.280 131.080 76.320 ;
        RECT 131.390 71.280 131.560 76.320 ;
        RECT 131.870 71.280 132.040 76.320 ;
        RECT 132.350 71.280 132.520 76.320 ;
        RECT 132.830 71.280 133.000 76.320 ;
        RECT 133.310 71.280 133.480 76.320 ;
        RECT 133.790 71.280 133.960 76.320 ;
        RECT 134.270 71.280 134.440 76.320 ;
        RECT 134.750 71.280 134.920 76.320 ;
        RECT 109.395 70.855 114.195 71.025 ;
        RECT 130.035 70.895 134.835 71.065 ;
        RECT 109.140 70.340 114.450 70.510 ;
        RECT 129.780 70.380 135.090 70.550 ;
        RECT 129.780 67.700 135.090 67.870 ;
        RECT 130.035 67.185 134.835 67.355 ;
        RECT 129.950 61.930 130.120 66.970 ;
        RECT 130.430 61.930 130.600 66.970 ;
        RECT 130.910 61.930 131.080 66.970 ;
        RECT 131.390 61.930 131.560 66.970 ;
        RECT 131.870 61.930 132.040 66.970 ;
        RECT 132.350 61.930 132.520 66.970 ;
        RECT 132.830 61.930 133.000 66.970 ;
        RECT 133.310 61.930 133.480 66.970 ;
        RECT 133.790 61.930 133.960 66.970 ;
        RECT 134.270 61.930 134.440 66.970 ;
        RECT 134.750 61.930 134.920 66.970 ;
        RECT 129.950 57.140 130.120 60.180 ;
        RECT 130.430 57.140 130.600 60.180 ;
        RECT 130.910 57.140 131.080 60.180 ;
        RECT 131.390 57.140 131.560 60.180 ;
        RECT 131.870 57.140 132.040 60.180 ;
        RECT 132.350 57.140 132.520 60.180 ;
        RECT 132.830 57.140 133.000 60.180 ;
        RECT 133.310 57.140 133.480 60.180 ;
        RECT 133.790 57.140 133.960 60.180 ;
        RECT 134.270 57.140 134.440 60.180 ;
        RECT 134.750 57.140 134.920 60.180 ;
        RECT 130.035 56.800 134.835 56.970 ;
        RECT 129.780 56.290 135.090 56.460 ;
        RECT 100.660 50.030 105.970 50.200 ;
        RECT 129.770 50.080 135.080 50.250 ;
        RECT 100.915 49.515 105.715 49.685 ;
        RECT 130.025 49.565 134.825 49.735 ;
        RECT 100.830 44.260 101.000 49.300 ;
        RECT 101.310 44.260 101.480 49.300 ;
        RECT 101.790 44.260 101.960 49.300 ;
        RECT 102.270 44.260 102.440 49.300 ;
        RECT 102.750 44.260 102.920 49.300 ;
        RECT 103.230 44.260 103.400 49.300 ;
        RECT 103.710 44.260 103.880 49.300 ;
        RECT 104.190 44.260 104.360 49.300 ;
        RECT 104.670 44.260 104.840 49.300 ;
        RECT 105.150 44.260 105.320 49.300 ;
        RECT 105.630 44.260 105.800 49.300 ;
        RECT 117.430 44.920 117.730 45.000 ;
        RECT 116.020 44.750 124.850 44.920 ;
        RECT 111.600 44.550 114.350 44.720 ;
        RECT 111.600 44.200 111.770 44.550 ;
        RECT 111.530 43.900 111.830 44.200 ;
        RECT 112.255 44.040 113.695 44.210 ;
        RECT 100.830 39.470 101.000 42.510 ;
        RECT 101.310 39.470 101.480 42.510 ;
        RECT 101.790 39.470 101.960 42.510 ;
        RECT 102.270 39.470 102.440 42.510 ;
        RECT 102.750 39.470 102.920 42.510 ;
        RECT 103.230 39.470 103.400 42.510 ;
        RECT 103.710 39.470 103.880 42.510 ;
        RECT 104.190 39.470 104.360 42.510 ;
        RECT 104.670 39.470 104.840 42.510 ;
        RECT 105.150 39.470 105.320 42.510 ;
        RECT 105.630 39.470 105.800 42.510 ;
        RECT 100.915 39.130 105.715 39.300 ;
        RECT 100.660 38.620 105.970 38.790 ;
        RECT 111.600 38.540 111.770 43.900 ;
        RECT 112.170 42.115 112.340 43.825 ;
        RECT 112.650 42.115 112.820 43.825 ;
        RECT 113.130 42.115 113.300 43.825 ;
        RECT 113.610 42.115 113.780 43.825 ;
        RECT 112.255 41.730 113.695 41.900 ;
        RECT 112.255 41.190 113.695 41.360 ;
        RECT 112.170 39.265 112.340 40.975 ;
        RECT 112.650 39.265 112.820 40.975 ;
        RECT 113.130 39.265 113.300 40.975 ;
        RECT 113.610 39.265 113.780 40.975 ;
        RECT 112.255 38.880 113.695 39.050 ;
        RECT 114.180 38.540 114.350 44.550 ;
        RECT 116.020 41.410 116.190 44.750 ;
        RECT 117.430 44.700 117.730 44.750 ;
        RECT 116.530 41.895 116.700 44.265 ;
        RECT 116.915 44.180 123.955 44.350 ;
        RECT 116.915 43.390 123.955 43.560 ;
        RECT 116.915 42.600 123.955 42.770 ;
        RECT 116.915 41.810 123.955 41.980 ;
        RECT 124.170 41.895 124.340 44.265 ;
        RECT 124.680 41.410 124.850 44.750 ;
        RECT 129.940 44.310 130.110 49.350 ;
        RECT 130.420 44.310 130.590 49.350 ;
        RECT 130.900 44.310 131.070 49.350 ;
        RECT 131.380 44.310 131.550 49.350 ;
        RECT 131.860 44.310 132.030 49.350 ;
        RECT 132.340 44.310 132.510 49.350 ;
        RECT 132.820 44.310 132.990 49.350 ;
        RECT 133.300 44.310 133.470 49.350 ;
        RECT 133.780 44.310 133.950 49.350 ;
        RECT 134.260 44.310 134.430 49.350 ;
        RECT 134.740 44.310 134.910 49.350 ;
        RECT 116.020 41.240 124.850 41.410 ;
        RECT 111.600 38.370 114.350 38.540 ;
        RECT 115.340 40.320 118.050 40.490 ;
        RECT 111.600 36.450 114.350 36.620 ;
        RECT 100.650 35.920 105.960 36.090 ;
        RECT 100.905 35.410 105.705 35.580 ;
        RECT 100.820 32.200 100.990 35.240 ;
        RECT 101.300 32.200 101.470 35.240 ;
        RECT 101.780 32.200 101.950 35.240 ;
        RECT 102.260 32.200 102.430 35.240 ;
        RECT 102.740 32.200 102.910 35.240 ;
        RECT 103.220 32.200 103.390 35.240 ;
        RECT 103.700 32.200 103.870 35.240 ;
        RECT 104.180 32.200 104.350 35.240 ;
        RECT 104.660 32.200 104.830 35.240 ;
        RECT 105.140 32.200 105.310 35.240 ;
        RECT 105.620 32.200 105.790 35.240 ;
        RECT 111.600 31.100 111.770 36.450 ;
        RECT 112.255 35.940 113.695 36.110 ;
        RECT 112.170 34.015 112.340 35.725 ;
        RECT 112.650 34.015 112.820 35.725 ;
        RECT 113.130 34.015 113.300 35.725 ;
        RECT 113.610 34.015 113.780 35.725 ;
        RECT 112.255 33.630 113.695 33.800 ;
        RECT 112.255 33.090 113.695 33.260 ;
        RECT 112.170 31.165 112.340 32.875 ;
        RECT 112.650 31.165 112.820 32.875 ;
        RECT 113.130 31.165 113.300 32.875 ;
        RECT 113.610 31.165 113.780 32.875 ;
        RECT 111.530 30.800 111.830 31.100 ;
        RECT 100.820 25.410 100.990 30.450 ;
        RECT 101.300 25.410 101.470 30.450 ;
        RECT 101.780 25.410 101.950 30.450 ;
        RECT 102.260 25.410 102.430 30.450 ;
        RECT 102.740 25.410 102.910 30.450 ;
        RECT 103.220 25.410 103.390 30.450 ;
        RECT 103.700 25.410 103.870 30.450 ;
        RECT 104.180 25.410 104.350 30.450 ;
        RECT 104.660 25.410 104.830 30.450 ;
        RECT 105.140 25.410 105.310 30.450 ;
        RECT 105.620 25.410 105.790 30.450 ;
        RECT 111.600 30.440 111.770 30.800 ;
        RECT 112.255 30.780 113.695 30.950 ;
        RECT 114.180 30.440 114.350 36.450 ;
        RECT 115.340 34.650 115.510 40.320 ;
        RECT 115.990 37.680 117.400 39.840 ;
        RECT 115.990 35.130 117.400 37.290 ;
        RECT 117.880 34.650 118.050 40.320 ;
        RECT 118.650 40.250 120.750 40.420 ;
        RECT 118.650 39.400 118.820 40.250 ;
        RECT 119.305 39.740 120.095 39.910 ;
        RECT 118.630 39.100 118.930 39.400 ;
        RECT 118.650 38.350 118.820 39.100 ;
        RECT 119.220 39.030 119.390 39.570 ;
        RECT 120.010 39.030 120.180 39.570 ;
        RECT 119.305 38.690 120.095 38.860 ;
        RECT 120.580 38.350 120.750 40.250 ;
        RECT 121.250 40.250 124.850 40.420 ;
        RECT 121.250 39.400 121.420 40.250 ;
        RECT 121.905 39.740 124.195 39.910 ;
        RECT 121.230 39.100 121.530 39.400 ;
        RECT 118.650 38.180 120.750 38.350 ;
        RECT 121.250 38.100 121.420 39.100 ;
        RECT 121.820 38.780 121.990 39.570 ;
        RECT 124.110 38.780 124.280 39.570 ;
        RECT 121.905 38.440 124.195 38.610 ;
        RECT 124.680 38.100 124.850 40.250 ;
        RECT 129.940 39.520 130.110 42.560 ;
        RECT 130.420 39.520 130.590 42.560 ;
        RECT 130.900 39.520 131.070 42.560 ;
        RECT 131.380 39.520 131.550 42.560 ;
        RECT 131.860 39.520 132.030 42.560 ;
        RECT 132.340 39.520 132.510 42.560 ;
        RECT 132.820 39.520 132.990 42.560 ;
        RECT 133.300 39.520 133.470 42.560 ;
        RECT 133.780 39.520 133.950 42.560 ;
        RECT 134.260 39.520 134.430 42.560 ;
        RECT 134.740 39.520 134.910 42.560 ;
        RECT 130.025 39.180 134.825 39.350 ;
        RECT 129.770 38.670 135.080 38.840 ;
        RECT 121.250 37.930 124.850 38.100 ;
        RECT 121.250 36.950 124.850 37.120 ;
        RECT 118.650 36.750 120.750 36.920 ;
        RECT 118.650 36.000 118.820 36.750 ;
        RECT 119.305 36.240 120.095 36.410 ;
        RECT 118.630 35.700 118.930 36.000 ;
        RECT 118.650 34.850 118.820 35.700 ;
        RECT 119.220 35.530 119.390 36.070 ;
        RECT 120.010 35.530 120.180 36.070 ;
        RECT 119.305 35.190 120.095 35.360 ;
        RECT 120.580 34.850 120.750 36.750 ;
        RECT 121.250 36.000 121.420 36.950 ;
        RECT 121.905 36.440 124.195 36.610 ;
        RECT 121.230 35.700 121.530 36.000 ;
        RECT 118.650 34.680 120.750 34.850 ;
        RECT 121.250 34.800 121.420 35.700 ;
        RECT 121.820 35.480 121.990 36.270 ;
        RECT 124.110 35.480 124.280 36.270 ;
        RECT 121.905 35.140 124.195 35.310 ;
        RECT 124.680 34.800 124.850 36.950 ;
        RECT 129.760 35.970 135.070 36.140 ;
        RECT 130.015 35.460 134.815 35.630 ;
        RECT 115.340 34.480 118.050 34.650 ;
        RECT 121.250 34.630 124.850 34.800 ;
        RECT 111.600 30.270 114.350 30.440 ;
        RECT 116.020 33.550 124.850 33.720 ;
        RECT 116.020 30.210 116.190 33.550 ;
        RECT 116.530 30.695 116.700 33.065 ;
        RECT 116.915 32.980 123.955 33.150 ;
        RECT 116.915 32.190 123.955 32.360 ;
        RECT 116.915 31.400 123.955 31.570 ;
        RECT 116.915 30.610 123.955 30.780 ;
        RECT 124.170 30.695 124.340 33.065 ;
        RECT 118.230 30.210 118.530 30.300 ;
        RECT 124.680 30.210 124.850 33.550 ;
        RECT 129.930 32.250 130.100 35.290 ;
        RECT 130.410 32.250 130.580 35.290 ;
        RECT 130.890 32.250 131.060 35.290 ;
        RECT 131.370 32.250 131.540 35.290 ;
        RECT 131.850 32.250 132.020 35.290 ;
        RECT 132.330 32.250 132.500 35.290 ;
        RECT 132.810 32.250 132.980 35.290 ;
        RECT 133.290 32.250 133.460 35.290 ;
        RECT 133.770 32.250 133.940 35.290 ;
        RECT 134.250 32.250 134.420 35.290 ;
        RECT 134.730 32.250 134.900 35.290 ;
        RECT 116.020 30.040 124.850 30.210 ;
        RECT 118.230 30.000 118.530 30.040 ;
        RECT 129.930 25.460 130.100 30.500 ;
        RECT 130.410 25.460 130.580 30.500 ;
        RECT 130.890 25.460 131.060 30.500 ;
        RECT 131.370 25.460 131.540 30.500 ;
        RECT 131.850 25.460 132.020 30.500 ;
        RECT 132.330 25.460 132.500 30.500 ;
        RECT 132.810 25.460 132.980 30.500 ;
        RECT 133.290 25.460 133.460 30.500 ;
        RECT 133.770 25.460 133.940 30.500 ;
        RECT 134.250 25.460 134.420 30.500 ;
        RECT 134.730 25.460 134.900 30.500 ;
        RECT 100.905 25.025 105.705 25.195 ;
        RECT 130.015 25.075 134.815 25.245 ;
        RECT 100.650 24.510 105.960 24.680 ;
        RECT 129.760 24.560 135.070 24.730 ;
        RECT 129.760 21.880 135.070 22.050 ;
        RECT 130.015 21.365 134.815 21.535 ;
        RECT 129.930 16.110 130.100 21.150 ;
        RECT 130.410 16.110 130.580 21.150 ;
        RECT 130.890 16.110 131.060 21.150 ;
        RECT 131.370 16.110 131.540 21.150 ;
        RECT 131.850 16.110 132.020 21.150 ;
        RECT 132.330 16.110 132.500 21.150 ;
        RECT 132.810 16.110 132.980 21.150 ;
        RECT 133.290 16.110 133.460 21.150 ;
        RECT 133.770 16.110 133.940 21.150 ;
        RECT 134.250 16.110 134.420 21.150 ;
        RECT 134.730 16.110 134.900 21.150 ;
        RECT 129.930 11.320 130.100 14.360 ;
        RECT 130.410 11.320 130.580 14.360 ;
        RECT 130.890 11.320 131.060 14.360 ;
        RECT 131.370 11.320 131.540 14.360 ;
        RECT 131.850 11.320 132.020 14.360 ;
        RECT 132.330 11.320 132.500 14.360 ;
        RECT 132.810 11.320 132.980 14.360 ;
        RECT 133.290 11.320 133.460 14.360 ;
        RECT 133.770 11.320 133.940 14.360 ;
        RECT 134.250 11.320 134.420 14.360 ;
        RECT 134.730 11.320 134.900 14.360 ;
        RECT 130.015 10.980 134.815 11.150 ;
        RECT 129.760 10.470 135.070 10.640 ;
      LAYER met1 ;
        RECT 101.020 220.980 137.010 221.000 ;
        RECT 99.950 218.030 137.010 220.980 ;
        RECT 99.950 218.020 136.820 218.030 ;
        RECT 99.950 217.970 123.000 218.020 ;
        RECT 99.950 217.960 108.520 217.970 ;
        RECT 120.130 217.040 120.640 217.100 ;
        RECT 124.270 217.040 124.780 217.100 ;
        RECT 128.410 217.040 128.920 217.100 ;
        RECT 132.550 217.040 133.060 217.100 ;
        RECT 120.110 216.440 120.660 217.040 ;
        RECT 120.930 216.600 123.810 216.890 ;
        RECT 124.250 216.440 124.800 217.040 ;
        RECT 125.070 216.600 127.950 216.890 ;
        RECT 128.390 216.440 128.940 217.040 ;
        RECT 129.210 216.600 132.090 216.890 ;
        RECT 132.530 216.440 133.080 217.040 ;
        RECT 133.350 216.600 136.230 216.890 ;
        RECT 120.130 216.380 120.640 216.440 ;
        RECT 124.270 216.380 124.780 216.440 ;
        RECT 128.410 216.380 128.920 216.440 ;
        RECT 132.550 216.380 133.060 216.440 ;
        RECT 49.060 215.730 101.200 215.740 ;
        RECT 48.930 215.700 101.200 215.730 ;
        RECT 120.260 215.700 136.820 215.780 ;
        RECT 48.930 212.710 137.010 215.700 ;
        RECT 48.930 212.650 51.060 212.710 ;
        RECT 79.370 212.690 137.010 212.710 ;
        RECT 99.960 212.680 137.010 212.690 ;
        RECT 115.030 212.670 137.010 212.680 ;
        RECT 120.260 212.590 136.820 212.670 ;
        RECT 124.020 211.610 124.530 211.670 ;
        RECT 128.160 211.610 128.670 211.670 ;
        RECT 132.300 211.610 132.810 211.670 ;
        RECT 136.440 211.610 136.950 211.670 ;
        RECT 120.850 211.170 123.730 211.460 ;
        RECT 124.000 211.010 124.550 211.610 ;
        RECT 124.990 211.170 127.870 211.460 ;
        RECT 128.140 211.010 128.690 211.610 ;
        RECT 129.130 211.170 132.010 211.460 ;
        RECT 132.280 211.010 132.830 211.610 ;
        RECT 133.270 211.170 136.150 211.460 ;
        RECT 136.420 211.010 136.970 211.610 ;
        RECT 124.020 210.950 124.530 211.010 ;
        RECT 128.160 210.950 128.670 211.010 ;
        RECT 132.300 210.950 132.810 211.010 ;
        RECT 136.440 210.950 136.950 211.010 ;
        RECT 120.260 210.340 136.820 210.350 ;
        RECT 0.950 210.310 3.030 210.320 ;
        RECT 99.950 210.310 136.950 210.340 ;
        RECT 0.950 207.320 136.950 210.310 ;
        RECT 0.950 207.090 110.150 207.320 ;
        RECT 114.970 207.310 136.950 207.320 ;
        RECT 2.000 207.070 110.150 207.090 ;
        RECT 108.420 207.060 110.150 207.070 ;
        RECT 108.630 205.130 110.150 207.060 ;
        RECT 126.640 205.170 128.020 207.310 ;
        RECT 108.610 204.650 110.150 205.130 ;
        RECT 121.010 205.100 122.680 205.110 ;
        RECT 120.520 204.880 122.680 205.100 ;
        RECT 110.810 204.280 120.110 204.680 ;
        RECT 104.030 203.780 105.010 203.810 ;
        RECT 104.030 203.580 108.790 203.780 ;
        RECT 104.030 203.520 108.920 203.580 ;
        RECT 109.830 203.520 110.250 203.540 ;
        RECT 110.810 203.520 111.210 204.280 ;
        RECT 115.960 203.630 116.410 204.080 ;
        RECT 104.030 203.190 108.940 203.520 ;
        RECT 109.830 203.190 111.210 203.520 ;
        RECT 116.710 203.380 116.910 204.280 ;
        RECT 120.520 204.150 121.380 204.880 ;
        RECT 121.680 204.310 122.680 204.700 ;
        RECT 120.520 204.000 122.680 204.150 ;
        RECT 122.840 204.030 123.120 205.140 ;
        RECT 123.500 204.920 123.970 205.020 ;
        RECT 124.160 204.920 128.020 205.170 ;
        RECT 123.500 204.630 123.975 204.920 ;
        RECT 124.180 204.900 126.180 204.920 ;
        RECT 123.500 204.440 123.970 204.630 ;
        RECT 123.500 204.150 123.975 204.440 ;
        RECT 124.150 204.340 126.200 204.730 ;
        RECT 124.180 204.150 126.180 204.170 ;
        RECT 126.490 204.150 128.020 204.920 ;
        RECT 123.500 204.090 123.970 204.150 ;
        RECT 123.490 204.060 123.970 204.090 ;
        RECT 123.490 204.055 123.945 204.060 ;
        RECT 119.740 203.980 122.680 204.000 ;
        RECT 118.950 203.920 122.680 203.980 ;
        RECT 118.950 203.670 121.270 203.920 ;
        RECT 118.950 203.630 120.160 203.670 ;
        RECT 104.030 203.130 108.920 203.190 ;
        RECT 104.030 202.800 108.790 203.130 ;
        RECT 109.890 203.120 111.210 203.190 ;
        RECT 116.310 203.180 116.910 203.380 ;
        RECT 116.310 203.090 116.610 203.180 ;
        RECT 115.490 202.850 115.660 202.975 ;
        RECT 115.850 202.880 116.610 203.090 ;
        RECT 116.790 202.930 116.960 202.975 ;
        RECT 115.850 202.860 116.600 202.880 ;
        RECT 104.030 202.770 105.010 202.800 ;
        RECT 115.460 202.560 115.690 202.850 ;
        RECT 115.490 202.435 115.660 202.560 ;
        RECT 108.610 202.090 109.990 202.410 ;
        RECT 113.710 202.180 115.160 202.430 ;
        RECT 115.850 202.320 116.600 202.550 ;
        RECT 116.760 202.480 117.160 202.930 ;
        RECT 116.790 202.435 116.960 202.480 ;
        RECT 113.710 202.110 114.110 202.180 ;
        RECT 108.520 202.040 110.280 202.090 ;
        RECT 113.655 202.080 114.110 202.110 ;
        RECT 113.150 202.040 113.490 202.070 ;
        RECT 108.520 202.030 113.490 202.040 ;
        RECT 49.160 202.010 83.730 202.030 ;
        RECT 96.010 202.010 113.490 202.030 ;
        RECT 49.160 201.990 113.490 202.010 ;
        RECT 48.920 200.530 113.490 201.990 ;
        RECT 113.655 201.880 114.075 202.080 ;
        RECT 114.310 201.830 114.480 201.995 ;
        RECT 114.910 201.980 115.160 202.180 ;
        RECT 116.160 201.980 116.410 202.320 ;
        RECT 117.360 202.280 118.710 202.480 ;
        RECT 114.280 200.670 114.510 201.830 ;
        RECT 114.910 201.780 116.610 201.980 ;
        RECT 114.910 201.680 115.710 201.780 ;
        RECT 116.320 201.700 116.610 201.780 ;
        RECT 115.510 201.540 115.710 201.680 ;
        RECT 115.510 201.080 115.770 201.540 ;
        RECT 115.540 201.040 115.770 201.080 ;
        RECT 116.010 201.030 116.410 201.560 ;
        RECT 116.620 201.040 116.850 201.540 ;
        RECT 115.780 200.780 116.070 200.880 ;
        RECT 116.660 200.780 116.810 201.040 ;
        RECT 117.360 200.780 117.560 202.280 ;
        RECT 118.360 202.110 118.710 202.280 ;
        RECT 117.950 201.830 118.120 201.995 ;
        RECT 118.355 201.880 118.775 202.110 ;
        RECT 119.010 201.830 119.180 201.995 ;
        RECT 48.920 200.510 96.070 200.530 ;
        RECT 49.160 200.500 83.730 200.510 ;
        RECT 108.520 200.450 113.490 200.530 ;
        RECT 108.520 200.390 110.280 200.450 ;
        RECT 113.150 200.420 113.490 200.450 ;
        RECT 113.655 200.390 114.075 200.620 ;
        RECT 114.310 200.505 114.480 200.670 ;
        RECT 115.780 200.650 117.560 200.780 ;
        RECT 117.920 200.670 118.150 201.830 ;
        RECT 115.810 200.580 117.560 200.650 ;
        RECT 116.160 200.410 116.410 200.580 ;
        RECT 117.950 200.505 118.120 200.670 ;
        RECT 118.355 200.610 118.775 200.620 ;
        RECT 108.610 200.050 109.990 200.390 ;
        RECT 112.910 200.075 113.170 200.080 ;
        RECT 113.720 200.075 114.065 200.390 ;
        RECT 115.480 200.170 115.650 200.295 ;
        RECT 115.840 200.180 116.590 200.410 ;
        RECT 118.350 200.380 118.790 200.610 ;
        RECT 118.960 200.530 119.310 201.830 ;
        RECT 119.010 200.505 119.180 200.530 ;
        RECT 116.780 200.230 116.950 200.295 ;
        RECT 116.760 200.170 117.110 200.230 ;
        RECT 112.910 199.780 114.065 200.075 ;
        RECT 115.450 199.880 115.680 200.170 ;
        RECT 116.750 199.880 117.110 200.170 ;
        RECT 91.970 199.620 93.010 199.650 ;
        RECT 104.010 199.620 104.990 199.650 ;
        RECT 91.970 198.640 98.500 199.620 ;
        RECT 104.010 199.330 108.790 199.620 ;
        RECT 113.210 199.330 114.065 199.780 ;
        RECT 115.480 199.755 115.650 199.880 ;
        RECT 115.840 199.640 116.590 199.870 ;
        RECT 116.760 199.780 117.110 199.880 ;
        RECT 118.395 200.035 118.770 200.380 ;
        RECT 119.175 200.035 119.620 200.125 ;
        RECT 118.395 199.850 119.620 200.035 ;
        RECT 116.780 199.755 116.950 199.780 ;
        RECT 115.910 199.480 116.510 199.640 ;
        RECT 118.395 199.330 118.770 199.850 ;
        RECT 119.175 199.760 119.620 199.850 ;
        RECT 119.010 199.330 119.260 199.335 ;
        RECT 104.010 199.270 108.920 199.330 ;
        RECT 110.040 199.270 111.210 199.320 ;
        RECT 104.010 198.940 108.940 199.270 ;
        RECT 104.010 198.880 108.920 198.940 ;
        RECT 109.830 198.920 111.210 199.270 ;
        RECT 112.265 199.300 120.110 199.330 ;
        RECT 112.265 198.940 120.140 199.300 ;
        RECT 120.520 199.100 121.270 203.670 ;
        RECT 122.850 203.440 123.110 204.030 ;
        RECT 122.820 203.180 123.140 203.440 ;
        RECT 122.850 203.150 123.110 203.180 ;
        RECT 123.490 202.505 123.940 204.055 ;
        RECT 124.150 203.900 128.020 204.150 ;
        RECT 123.490 202.060 125.575 202.505 ;
        RECT 124.030 202.055 125.575 202.060 ;
        RECT 123.500 200.915 123.950 200.920 ;
        RECT 123.500 200.465 125.585 200.915 ;
        RECT 122.840 200.100 123.120 200.150 ;
        RECT 122.750 199.580 123.200 200.100 ;
        RECT 112.265 198.930 120.110 198.940 ;
        RECT 113.720 198.925 114.065 198.930 ;
        RECT 118.395 198.925 118.770 198.930 ;
        RECT 104.010 198.640 108.790 198.880 ;
        RECT 91.970 198.610 93.010 198.640 ;
        RECT 104.010 198.610 104.990 198.640 ;
        RECT 110.810 198.630 111.210 198.920 ;
        RECT 120.520 198.870 122.680 199.100 ;
        RECT 110.810 198.230 120.150 198.630 ;
        RECT 120.520 198.230 121.380 198.870 ;
        RECT 121.680 198.300 122.680 198.690 ;
        RECT 120.500 198.140 121.380 198.230 ;
        RECT 120.500 197.910 122.680 198.140 ;
        RECT 122.840 198.020 123.120 199.580 ;
        RECT 123.500 199.010 123.950 200.465 ;
        RECT 126.640 199.400 128.020 203.900 ;
        RECT 129.200 203.440 129.460 203.470 ;
        RECT 129.200 203.180 132.730 203.440 ;
        RECT 129.200 203.150 129.460 203.180 ;
        RECT 128.675 202.505 129.125 202.535 ;
        RECT 128.675 202.055 134.795 202.505 ;
        RECT 128.675 202.025 129.125 202.055 ;
        RECT 129.260 199.960 129.540 199.990 ;
        RECT 136.440 199.960 136.720 199.990 ;
        RECT 129.260 199.680 136.720 199.960 ;
        RECT 129.260 199.650 129.540 199.680 ;
        RECT 136.440 199.650 136.720 199.680 ;
        RECT 126.610 199.160 128.020 199.400 ;
        RECT 123.500 198.910 123.970 199.010 ;
        RECT 124.160 198.910 128.020 199.160 ;
        RECT 123.500 198.620 123.975 198.910 ;
        RECT 124.180 198.890 126.180 198.910 ;
        RECT 123.500 198.430 123.970 198.620 ;
        RECT 123.500 198.140 123.975 198.430 ;
        RECT 124.150 198.330 126.200 198.720 ;
        RECT 124.180 198.140 126.180 198.160 ;
        RECT 126.490 198.140 128.020 198.910 ;
        RECT 123.500 198.050 123.970 198.140 ;
        RECT 123.775 198.045 123.945 198.050 ;
        RECT 0.960 197.740 83.830 197.750 ;
        RECT 108.610 197.740 109.990 197.810 ;
        RECT 0.960 196.500 110.110 197.740 ;
        RECT 0.960 194.990 102.370 196.500 ;
        RECT 0.960 194.910 83.830 194.990 ;
        RECT 0.960 194.890 3.040 194.910 ;
        RECT 100.490 191.100 102.370 194.990 ;
        RECT 117.640 194.990 118.770 195.000 ;
        RECT 120.500 194.990 121.290 197.910 ;
        RECT 124.150 197.890 128.020 198.140 ;
        RECT 117.640 194.480 121.320 194.990 ;
        RECT 126.670 194.740 128.020 197.890 ;
        RECT 126.670 194.510 128.070 194.740 ;
        RECT 120.560 194.150 121.320 194.480 ;
        RECT 126.690 194.210 128.070 194.510 ;
        RECT 120.560 194.090 122.730 194.150 ;
        RECT 120.570 193.920 122.730 194.090 ;
        RECT 102.840 193.710 119.120 193.790 ;
        RECT 102.840 193.330 120.150 193.710 ;
        RECT 102.840 193.290 119.120 193.330 ;
        RECT 100.660 190.820 102.180 191.100 ;
        RECT 100.640 190.340 102.180 190.820 ;
        RECT 89.960 189.490 91.000 189.520 ;
        RECT 89.960 189.270 100.740 189.490 ;
        RECT 89.960 189.210 100.950 189.270 ;
        RECT 101.860 189.210 102.280 189.230 ;
        RECT 102.840 189.210 103.240 193.290 ;
        RECT 110.030 192.290 110.630 192.890 ;
        RECT 106.210 190.025 106.460 192.130 ;
        RECT 107.040 191.890 107.290 192.130 ;
        RECT 107.870 191.890 108.120 192.130 ;
        RECT 108.700 191.890 108.950 192.130 ;
        RECT 109.530 191.890 109.780 192.130 ;
        RECT 107.040 190.190 108.130 191.890 ;
        RECT 108.700 190.190 109.780 191.890 ;
        RECT 107.040 190.025 107.290 190.190 ;
        RECT 107.870 190.025 108.120 190.190 ;
        RECT 108.700 190.025 108.950 190.190 ;
        RECT 109.530 190.025 109.780 190.190 ;
        RECT 89.960 188.880 100.970 189.210 ;
        RECT 101.860 188.880 103.240 189.210 ;
        RECT 106.210 189.290 106.460 189.445 ;
        RECT 107.040 189.290 107.290 189.445 ;
        RECT 106.210 189.090 107.290 189.290 ;
        RECT 89.960 188.820 100.950 188.880 ;
        RECT 89.960 188.510 100.740 188.820 ;
        RECT 101.920 188.810 103.240 188.880 ;
        RECT 89.960 188.480 91.000 188.510 ;
        RECT 100.640 187.780 102.020 188.100 ;
        RECT 49.390 187.730 83.960 187.740 ;
        RECT 48.940 187.720 83.960 187.730 ;
        RECT 100.550 187.720 102.310 187.780 ;
        RECT 48.940 186.220 102.310 187.720 ;
        RECT 48.940 186.210 83.960 186.220 ;
        RECT 48.940 186.180 51.080 186.210 ;
        RECT 100.550 186.080 102.310 186.220 ;
        RECT 106.130 187.590 107.290 189.090 ;
        RECT 100.640 185.740 102.020 186.080 ;
        RECT 87.970 185.340 89.040 185.380 ;
        RECT 87.970 185.020 100.760 185.340 ;
        RECT 87.970 184.960 100.950 185.020 ;
        RECT 102.070 184.960 103.240 185.010 ;
        RECT 106.130 184.990 106.530 187.590 ;
        RECT 107.040 187.340 107.290 187.590 ;
        RECT 107.870 189.090 108.120 189.445 ;
        RECT 108.700 189.090 108.950 189.445 ;
        RECT 107.870 187.390 108.950 189.090 ;
        RECT 107.870 187.340 108.120 187.390 ;
        RECT 108.700 187.340 108.950 187.390 ;
        RECT 109.530 188.090 109.780 189.445 ;
        RECT 111.430 188.960 111.730 193.290 ;
        RECT 120.570 193.190 121.430 193.920 ;
        RECT 121.730 193.350 122.730 193.740 ;
        RECT 120.570 192.960 122.730 193.190 ;
        RECT 122.890 193.070 123.170 194.180 ;
        RECT 123.550 193.960 124.020 194.060 ;
        RECT 124.210 193.960 128.070 194.210 ;
        RECT 123.550 193.670 124.025 193.960 ;
        RECT 124.230 193.940 126.230 193.960 ;
        RECT 123.550 193.480 124.020 193.670 ;
        RECT 123.550 193.190 124.025 193.480 ;
        RECT 124.200 193.380 126.250 193.770 ;
        RECT 124.230 193.190 126.230 193.210 ;
        RECT 126.540 193.190 128.070 193.960 ;
        RECT 123.550 193.140 124.020 193.190 ;
        RECT 123.540 193.100 124.020 193.140 ;
        RECT 123.540 193.095 123.995 193.100 ;
        RECT 113.230 192.390 113.830 192.890 ;
        RECT 114.010 191.890 114.260 192.130 ;
        RECT 114.840 191.890 115.090 192.130 ;
        RECT 115.670 191.890 115.920 192.130 ;
        RECT 113.030 190.390 114.260 191.890 ;
        RECT 110.910 188.790 111.080 188.845 ;
        RECT 110.730 188.740 111.080 188.790 ;
        RECT 110.730 188.340 111.130 188.740 ;
        RECT 111.270 188.730 112.020 188.960 ;
        RECT 112.210 188.720 112.380 188.845 ;
        RECT 112.180 188.430 112.410 188.720 ;
        RECT 110.910 188.305 111.080 188.340 ;
        RECT 111.270 188.190 112.020 188.420 ;
        RECT 112.210 188.305 112.380 188.430 ;
        RECT 109.530 187.990 111.030 188.090 ;
        RECT 111.480 187.990 111.730 188.190 ;
        RECT 109.530 187.790 111.730 187.990 ;
        RECT 109.530 187.590 111.930 187.790 ;
        RECT 112.380 187.640 112.830 188.090 ;
        RECT 109.530 187.490 111.030 187.590 ;
        RECT 111.640 187.510 111.930 187.590 ;
        RECT 109.530 187.340 109.780 187.490 ;
        RECT 110.830 187.350 111.030 187.490 ;
        RECT 110.830 186.890 111.090 187.350 ;
        RECT 110.860 186.850 111.090 186.890 ;
        RECT 111.330 186.840 111.730 187.370 ;
        RECT 111.940 186.850 112.170 187.350 ;
        RECT 107.040 186.590 107.290 186.760 ;
        RECT 107.870 186.590 108.120 186.760 ;
        RECT 108.700 186.590 108.950 186.760 ;
        RECT 109.530 186.590 109.780 186.760 ;
        RECT 87.970 184.630 100.970 184.960 ;
        RECT 87.970 184.570 100.950 184.630 ;
        RECT 101.860 184.610 103.240 184.960 ;
        RECT 106.210 184.655 106.460 184.990 ;
        RECT 107.040 184.890 108.130 186.590 ;
        RECT 108.700 184.890 109.780 186.590 ;
        RECT 111.100 186.590 111.390 186.690 ;
        RECT 111.980 186.590 112.130 186.850 ;
        RECT 113.030 186.590 113.630 190.390 ;
        RECT 114.010 190.025 114.260 190.390 ;
        RECT 114.830 190.290 115.920 191.890 ;
        RECT 114.840 190.025 115.090 190.290 ;
        RECT 115.670 190.025 115.920 190.290 ;
        RECT 116.500 191.790 116.750 192.130 ;
        RECT 117.330 191.790 117.580 192.130 ;
        RECT 116.500 190.190 117.580 191.790 ;
        RECT 116.500 190.025 116.750 190.190 ;
        RECT 117.330 190.025 117.580 190.190 ;
        RECT 114.010 189.190 114.260 189.445 ;
        RECT 114.840 189.190 115.090 189.445 ;
        RECT 114.010 187.590 115.090 189.190 ;
        RECT 114.010 187.340 114.260 187.590 ;
        RECT 114.840 187.340 115.090 187.590 ;
        RECT 115.670 189.190 115.920 189.445 ;
        RECT 116.500 189.190 116.750 189.445 ;
        RECT 115.670 187.590 116.750 189.190 ;
        RECT 117.330 188.390 117.580 189.445 ;
        RECT 115.670 187.340 115.920 187.590 ;
        RECT 116.500 187.340 116.750 187.590 ;
        RECT 111.100 186.460 113.630 186.590 ;
        RECT 111.130 186.390 113.630 186.460 ;
        RECT 111.480 186.200 113.630 186.390 ;
        RECT 111.480 186.010 111.730 186.200 ;
        RECT 111.960 186.190 113.630 186.200 ;
        RECT 114.010 186.590 114.260 186.760 ;
        RECT 114.840 186.590 115.090 186.760 ;
        RECT 110.910 185.840 111.080 185.895 ;
        RECT 110.730 185.770 111.080 185.840 ;
        RECT 111.270 185.780 112.020 186.010 ;
        RECT 112.210 185.770 112.380 185.895 ;
        RECT 110.730 185.480 111.110 185.770 ;
        RECT 112.180 185.480 112.410 185.770 ;
        RECT 110.730 185.440 111.080 185.480 ;
        RECT 110.910 185.355 111.080 185.440 ;
        RECT 111.270 185.240 112.020 185.470 ;
        RECT 112.210 185.355 112.380 185.480 ;
        RECT 107.040 184.655 107.290 184.890 ;
        RECT 107.870 184.655 108.120 184.890 ;
        RECT 108.700 184.655 108.950 184.890 ;
        RECT 109.530 184.655 109.780 184.890 ;
        RECT 87.970 184.360 100.760 184.570 ;
        RECT 87.970 184.330 89.040 184.360 ;
        RECT 100.640 183.280 102.020 183.500 ;
        RECT 0.960 183.020 102.020 183.280 ;
        RECT 0.960 181.460 101.880 183.020 ;
        RECT 2.450 181.450 101.880 181.460 ;
        RECT 102.840 179.710 103.240 184.610 ;
        RECT 106.210 183.890 106.460 184.075 ;
        RECT 107.040 183.890 107.290 184.075 ;
        RECT 106.210 182.190 107.290 183.890 ;
        RECT 106.210 181.970 106.460 182.190 ;
        RECT 107.040 181.970 107.290 182.190 ;
        RECT 107.870 183.790 108.120 184.075 ;
        RECT 108.700 183.790 108.950 184.075 ;
        RECT 107.870 182.090 108.950 183.790 ;
        RECT 107.870 181.970 108.120 182.090 ;
        RECT 108.700 181.970 108.950 182.090 ;
        RECT 109.530 183.990 109.780 184.075 ;
        RECT 109.530 180.790 109.830 183.990 ;
        RECT 111.430 183.190 111.730 185.240 ;
        RECT 114.010 184.990 115.090 186.590 ;
        RECT 114.010 184.655 114.260 184.990 ;
        RECT 114.840 184.655 115.090 184.990 ;
        RECT 115.670 186.490 115.920 186.760 ;
        RECT 116.500 186.490 116.750 186.760 ;
        RECT 115.670 184.890 116.750 186.490 ;
        RECT 117.230 185.190 117.630 188.390 ;
        RECT 115.670 184.655 115.920 184.890 ;
        RECT 116.500 184.655 116.750 184.890 ;
        RECT 117.330 184.655 117.580 185.190 ;
        RECT 114.010 183.890 114.260 184.075 ;
        RECT 111.130 182.690 111.730 183.190 ;
        RECT 113.930 180.790 114.330 183.890 ;
        RECT 114.840 183.790 115.090 184.075 ;
        RECT 115.670 183.790 115.920 184.075 ;
        RECT 114.840 182.190 115.930 183.790 ;
        RECT 116.500 183.690 116.750 184.075 ;
        RECT 117.330 183.690 117.580 184.075 ;
        RECT 114.840 181.970 115.090 182.190 ;
        RECT 115.670 181.970 115.920 182.190 ;
        RECT 116.500 182.090 117.580 183.690 ;
        RECT 116.500 181.970 116.750 182.090 ;
        RECT 117.330 181.970 117.580 182.090 ;
        RECT 105.030 180.470 120.090 180.790 ;
        RECT 105.030 180.190 120.190 180.470 ;
        RECT 118.000 180.110 120.190 180.190 ;
        RECT 120.570 180.270 121.320 192.960 ;
        RECT 122.900 192.340 123.160 193.070 ;
        RECT 122.840 191.940 123.220 192.340 ;
        RECT 123.540 191.490 123.990 193.095 ;
        RECT 124.200 192.940 128.070 193.190 ;
        RECT 123.540 191.040 125.545 191.490 ;
        RECT 123.550 182.015 124.000 182.020 ;
        RECT 123.550 181.565 125.535 182.015 ;
        RECT 122.880 181.135 123.170 181.140 ;
        RECT 123.550 181.135 124.000 181.565 ;
        RECT 122.880 180.845 125.505 181.135 ;
        RECT 120.570 180.040 122.730 180.270 ;
        RECT 122.880 180.210 123.170 180.845 ;
        RECT 119.000 179.790 120.200 179.800 ;
        RECT 105.030 179.710 120.200 179.790 ;
        RECT 102.840 179.400 120.200 179.710 ;
        RECT 102.840 179.310 120.090 179.400 ;
        RECT 105.030 179.290 120.090 179.310 ;
        RECT 120.570 179.310 121.430 180.040 ;
        RECT 121.730 179.470 122.730 179.860 ;
        RECT 120.570 179.130 122.730 179.310 ;
        RECT 122.890 179.190 123.170 180.210 ;
        RECT 123.550 180.180 124.000 180.845 ;
        RECT 126.690 180.570 128.070 192.940 ;
        RECT 129.180 192.260 129.440 192.290 ;
        RECT 129.180 192.000 132.710 192.260 ;
        RECT 129.180 191.970 129.440 192.000 ;
        RECT 129.025 191.040 134.845 191.490 ;
        RECT 129.205 181.135 129.495 181.165 ;
        RECT 129.205 180.845 136.755 181.135 ;
        RECT 129.205 180.815 129.495 180.845 ;
        RECT 126.660 180.330 128.070 180.570 ;
        RECT 123.550 180.080 124.020 180.180 ;
        RECT 124.210 180.080 128.070 180.330 ;
        RECT 123.550 179.790 124.025 180.080 ;
        RECT 124.230 180.060 126.230 180.080 ;
        RECT 123.550 179.600 124.020 179.790 ;
        RECT 123.550 179.310 124.025 179.600 ;
        RECT 124.200 179.500 126.250 179.890 ;
        RECT 124.230 179.310 126.230 179.330 ;
        RECT 126.540 179.310 128.070 180.080 ;
        RECT 123.550 179.220 124.020 179.310 ;
        RECT 123.825 179.215 123.995 179.220 ;
        RECT 121.060 179.080 122.730 179.130 ;
        RECT 124.200 179.160 128.070 179.310 ;
        RECT 124.200 179.060 127.040 179.160 ;
        RECT 2.360 177.560 96.590 177.570 ;
        RECT 0.950 177.550 96.590 177.560 ;
        RECT 0.950 175.830 97.730 177.550 ;
        RECT 119.220 176.170 119.840 176.570 ;
        RECT 0.950 175.820 3.040 175.830 ;
        RECT 79.050 175.810 97.730 175.830 ;
        RECT 96.190 175.590 97.730 175.810 ;
        RECT 98.450 175.350 99.050 175.670 ;
        RECT 85.970 174.740 87.010 174.770 ;
        RECT 85.970 174.520 96.350 174.740 ;
        RECT 85.970 174.460 96.500 174.520 ;
        RECT 97.410 174.460 97.830 174.480 ;
        RECT 98.500 174.460 99.000 175.350 ;
        RECT 85.970 174.130 96.520 174.460 ;
        RECT 97.410 174.130 99.000 174.460 ;
        RECT 85.970 174.070 96.500 174.130 ;
        RECT 85.970 173.760 96.350 174.070 ;
        RECT 97.470 174.060 99.000 174.130 ;
        RECT 99.980 174.920 107.310 175.510 ;
        RECT 109.920 174.960 110.420 175.215 ;
        RECT 99.980 174.850 107.550 174.920 ;
        RECT 99.980 174.845 108.160 174.850 ;
        RECT 99.980 174.770 109.020 174.845 ;
        RECT 99.980 174.675 109.050 174.770 ;
        RECT 109.210 174.730 114.210 174.960 ;
        RECT 109.920 174.710 110.420 174.730 ;
        RECT 114.370 174.710 114.600 174.770 ;
        RECT 119.400 174.710 119.575 176.170 ;
        RECT 126.690 176.140 128.070 177.580 ;
        RECT 121.060 176.070 122.730 176.080 ;
        RECT 120.570 175.850 122.730 176.070 ;
        RECT 120.570 175.120 121.430 175.850 ;
        RECT 121.730 175.280 122.730 175.670 ;
        RECT 120.570 174.920 122.730 175.120 ;
        RECT 122.890 175.000 123.170 176.110 ;
        RECT 123.550 175.890 124.020 175.990 ;
        RECT 124.210 175.890 128.070 176.140 ;
        RECT 123.550 175.600 124.025 175.890 ;
        RECT 124.230 175.870 126.230 175.890 ;
        RECT 123.550 175.410 124.020 175.600 ;
        RECT 123.550 175.120 124.025 175.410 ;
        RECT 124.200 175.310 126.250 175.700 ;
        RECT 124.230 175.120 126.230 175.140 ;
        RECT 126.540 175.120 128.070 175.890 ;
        RECT 123.550 175.060 124.020 175.120 ;
        RECT 123.540 175.030 124.020 175.060 ;
        RECT 123.540 175.025 123.995 175.030 ;
        RECT 99.980 174.670 108.160 174.675 ;
        RECT 99.980 174.560 107.550 174.670 ;
        RECT 99.980 174.500 107.310 174.560 ;
        RECT 85.970 173.730 87.010 173.760 ;
        RECT 96.190 173.030 97.570 173.350 ;
        RECT 96.100 172.980 97.860 173.030 ;
        RECT 99.980 172.980 101.050 174.500 ;
        RECT 108.820 174.480 109.050 174.675 ;
        RECT 114.370 174.540 119.575 174.710 ;
        RECT 120.320 174.890 122.730 174.920 ;
        RECT 120.320 174.570 121.370 174.890 ;
        RECT 105.440 174.110 106.500 174.130 ;
        RECT 102.520 173.830 107.760 174.110 ;
        RECT 105.440 173.820 106.500 173.830 ;
        RECT 96.100 172.950 101.050 172.980 ;
        RECT 48.940 171.450 101.050 172.950 ;
        RECT 102.840 172.550 103.160 172.930 ;
        RECT 103.730 171.810 104.020 173.670 ;
        RECT 106.980 171.810 107.260 173.670 ;
        RECT 108.850 172.670 109.020 174.480 ;
        RECT 109.210 174.290 114.210 174.520 ;
        RECT 114.370 174.480 114.600 174.540 ;
        RECT 112.220 172.860 113.220 174.290 ;
        RECT 108.820 172.380 109.050 172.670 ;
        RECT 109.210 172.630 119.210 172.860 ;
        RECT 119.400 172.670 119.575 174.540 ;
        RECT 48.940 171.420 85.160 171.450 ;
        RECT 48.940 171.400 51.080 171.420 ;
        RECT 96.100 171.390 101.050 171.450 ;
        RECT 96.100 171.330 97.860 171.390 ;
        RECT 96.190 170.990 97.570 171.330 ;
        RECT 102.520 171.310 107.760 171.590 ;
        RECT 83.970 170.580 85.000 170.610 ;
        RECT 83.970 170.270 96.360 170.580 ;
        RECT 83.970 170.210 96.500 170.270 ;
        RECT 97.620 170.210 99.000 170.260 ;
        RECT 83.970 169.880 96.520 170.210 ;
        RECT 83.970 169.820 96.500 169.880 ;
        RECT 97.410 169.860 99.000 170.210 ;
        RECT 83.970 169.600 96.360 169.820 ;
        RECT 98.500 169.640 99.000 169.860 ;
        RECT 83.970 169.570 85.000 169.600 ;
        RECT 98.450 169.350 99.050 169.640 ;
        RECT 102.520 169.630 103.480 171.310 ;
        RECT 108.850 170.570 109.020 172.380 ;
        RECT 109.210 172.190 119.210 172.420 ;
        RECT 119.370 172.380 119.600 172.670 ;
        RECT 112.225 170.760 113.225 172.190 ;
        RECT 108.820 170.280 109.050 170.570 ;
        RECT 109.210 170.530 114.210 170.760 ;
        RECT 114.370 170.510 114.600 170.570 ;
        RECT 119.400 170.510 119.575 172.380 ;
        RECT 109.925 170.320 110.425 170.350 ;
        RECT 114.370 170.340 119.575 170.510 ;
        RECT 109.210 170.090 114.210 170.320 ;
        RECT 114.370 170.280 114.600 170.340 ;
        RECT 109.925 169.845 110.425 170.090 ;
        RECT 120.570 170.070 121.320 174.570 ;
        RECT 122.900 174.410 123.160 175.000 ;
        RECT 122.870 174.150 123.190 174.410 ;
        RECT 122.900 174.120 123.160 174.150 ;
        RECT 123.540 173.475 123.990 175.025 ;
        RECT 124.200 174.870 128.070 175.120 ;
        RECT 123.540 173.030 125.625 173.475 ;
        RECT 124.080 173.025 125.625 173.030 ;
        RECT 123.550 171.885 124.000 171.890 ;
        RECT 123.550 171.435 125.635 171.885 ;
        RECT 122.890 171.070 123.170 171.120 ;
        RECT 122.800 170.550 123.250 171.070 ;
        RECT 120.570 169.840 122.730 170.070 ;
        RECT 102.470 169.360 103.530 169.630 ;
        RECT 98.500 169.300 99.000 169.350 ;
        RECT 120.570 169.200 121.430 169.840 ;
        RECT 121.730 169.270 122.730 169.660 ;
        RECT 110.050 168.850 110.310 169.170 ;
        RECT 120.550 169.110 121.430 169.200 ;
        RECT 120.550 168.880 122.730 169.110 ;
        RECT 122.890 168.990 123.170 170.550 ;
        RECT 123.550 169.980 124.000 171.435 ;
        RECT 126.690 170.370 128.070 174.870 ;
        RECT 128.850 174.410 129.110 174.440 ;
        RECT 128.850 174.150 132.640 174.410 ;
        RECT 128.850 174.120 129.110 174.150 ;
        RECT 128.735 173.475 129.185 173.505 ;
        RECT 128.735 173.025 134.735 173.475 ;
        RECT 128.735 172.995 129.185 173.025 ;
        RECT 128.960 170.930 129.240 170.960 ;
        RECT 136.390 170.930 136.670 170.960 ;
        RECT 128.960 170.650 136.670 170.930 ;
        RECT 128.960 170.620 129.240 170.650 ;
        RECT 136.390 170.620 136.670 170.650 ;
        RECT 126.660 170.130 128.070 170.370 ;
        RECT 123.550 169.880 124.020 169.980 ;
        RECT 124.210 169.880 128.070 170.130 ;
        RECT 123.550 169.590 124.025 169.880 ;
        RECT 124.230 169.860 126.230 169.880 ;
        RECT 123.550 169.400 124.020 169.590 ;
        RECT 123.550 169.110 124.025 169.400 ;
        RECT 124.200 169.300 126.250 169.690 ;
        RECT 124.230 169.110 126.230 169.130 ;
        RECT 126.540 169.110 128.070 169.880 ;
        RECT 123.550 169.020 124.020 169.110 ;
        RECT 123.825 169.015 123.995 169.020 ;
        RECT 96.190 168.600 97.570 168.750 ;
        RECT 95.580 168.410 97.710 168.600 ;
        RECT 79.020 168.400 97.710 168.410 ;
        RECT 0.950 167.070 97.710 168.400 ;
        RECT 0.950 166.910 97.790 167.070 ;
        RECT 95.580 166.790 97.790 166.910 ;
        RECT 96.410 166.590 97.790 166.790 ;
        RECT 96.150 165.130 96.570 165.480 ;
        RECT 97.480 165.460 97.840 165.520 ;
        RECT 97.460 165.350 97.860 165.460 ;
        RECT 110.080 165.350 110.280 168.850 ;
        RECT 120.550 168.000 121.340 168.880 ;
        RECT 124.200 168.860 128.070 169.110 ;
        RECT 126.720 168.000 128.070 168.860 ;
        RECT 97.460 165.150 110.280 165.350 ;
        RECT 97.460 165.130 97.860 165.150 ;
        RECT 97.480 165.070 97.840 165.130 ;
        RECT 96.410 164.030 97.790 164.350 ;
        RECT 79.540 164.010 97.790 164.030 ;
        RECT 48.950 163.870 97.790 164.010 ;
        RECT 48.950 161.970 97.710 163.870 ;
        RECT 48.950 161.960 81.290 161.970 ;
        RECT 48.950 161.950 51.030 161.960 ;
        RECT 113.745 97.290 136.180 97.330 ;
        RECT 1.005 97.280 136.180 97.290 ;
        RECT 0.940 95.880 136.180 97.280 ;
        RECT 0.940 95.840 115.540 95.880 ;
        RECT 0.940 95.830 3.050 95.840 ;
        RECT 130.140 95.555 130.430 95.585 ;
        RECT 130.620 95.555 130.910 95.585 ;
        RECT 131.100 95.555 131.390 95.585 ;
        RECT 131.580 95.555 131.870 95.585 ;
        RECT 132.060 95.555 132.350 95.585 ;
        RECT 132.540 95.555 132.830 95.585 ;
        RECT 133.020 95.555 133.310 95.585 ;
        RECT 133.500 95.555 133.790 95.585 ;
        RECT 133.980 95.555 134.270 95.585 ;
        RECT 134.460 95.580 134.750 95.585 ;
        RECT 134.460 95.570 136.290 95.580 ;
        RECT 134.460 95.555 145.990 95.570 ;
        RECT 109.500 95.515 109.790 95.545 ;
        RECT 109.980 95.515 110.270 95.545 ;
        RECT 110.460 95.515 110.750 95.545 ;
        RECT 110.940 95.515 111.230 95.545 ;
        RECT 111.420 95.515 111.710 95.545 ;
        RECT 111.900 95.515 112.190 95.545 ;
        RECT 112.380 95.515 112.670 95.545 ;
        RECT 112.860 95.515 113.150 95.545 ;
        RECT 113.340 95.515 113.630 95.545 ;
        RECT 113.820 95.540 114.110 95.545 ;
        RECT 113.820 95.530 115.650 95.540 ;
        RECT 113.820 95.515 128.020 95.530 ;
        RECT 109.405 95.345 128.020 95.515 ;
        RECT 130.045 95.385 145.990 95.555 ;
        RECT 130.140 95.355 130.430 95.385 ;
        RECT 130.620 95.355 130.910 95.385 ;
        RECT 131.100 95.355 131.390 95.385 ;
        RECT 131.580 95.355 131.870 95.385 ;
        RECT 132.060 95.355 132.350 95.385 ;
        RECT 132.540 95.355 132.830 95.385 ;
        RECT 133.020 95.355 133.310 95.385 ;
        RECT 133.500 95.355 133.790 95.385 ;
        RECT 133.980 95.355 134.270 95.385 ;
        RECT 134.460 95.355 145.990 95.385 ;
        RECT 134.470 95.350 145.990 95.355 ;
        RECT 109.500 95.315 109.790 95.345 ;
        RECT 109.980 95.315 110.270 95.345 ;
        RECT 110.460 95.315 110.750 95.345 ;
        RECT 110.940 95.315 111.230 95.345 ;
        RECT 111.420 95.315 111.710 95.345 ;
        RECT 111.900 95.315 112.190 95.345 ;
        RECT 112.380 95.315 112.670 95.345 ;
        RECT 112.860 95.315 113.150 95.345 ;
        RECT 113.340 95.315 113.630 95.345 ;
        RECT 113.820 95.315 128.020 95.345 ;
        RECT 135.640 95.340 145.990 95.350 ;
        RECT 113.830 95.310 128.020 95.315 ;
        RECT 115.000 95.300 128.020 95.310 ;
        RECT 106.990 90.290 108.090 91.290 ;
        RECT 109.290 88.290 109.530 95.110 ;
        RECT 109.770 92.790 110.010 95.110 ;
        RECT 109.690 90.290 110.090 92.790 ;
        RECT 109.210 85.790 109.610 88.290 ;
        RECT 109.290 85.320 109.530 85.790 ;
        RECT 109.770 85.320 110.010 90.290 ;
        RECT 110.250 88.290 110.490 95.120 ;
        RECT 110.730 92.790 110.970 95.110 ;
        RECT 111.210 95.100 111.440 95.110 ;
        RECT 111.690 95.100 111.920 95.110 ;
        RECT 110.650 90.290 111.050 92.790 ;
        RECT 110.170 85.790 110.570 88.290 ;
        RECT 110.250 85.330 110.490 85.790 ;
        RECT 110.250 85.320 110.480 85.330 ;
        RECT 110.730 85.320 110.970 90.290 ;
        RECT 111.210 88.290 111.450 95.100 ;
        RECT 111.690 92.790 111.930 95.100 ;
        RECT 111.610 90.290 112.010 92.790 ;
        RECT 111.130 85.790 111.530 88.290 ;
        RECT 111.210 85.310 111.450 85.790 ;
        RECT 111.690 85.310 111.930 90.290 ;
        RECT 112.170 88.290 112.410 95.110 ;
        RECT 112.650 92.790 112.890 95.110 ;
        RECT 112.570 90.290 112.970 92.790 ;
        RECT 112.090 85.790 112.490 88.290 ;
        RECT 112.170 85.320 112.410 85.790 ;
        RECT 112.650 85.320 112.890 90.290 ;
        RECT 113.120 88.290 113.360 95.110 ;
        RECT 113.610 92.790 113.850 95.110 ;
        RECT 113.530 90.290 113.930 92.790 ;
        RECT 113.050 85.790 113.450 88.290 ;
        RECT 113.120 85.320 113.360 85.790 ;
        RECT 113.610 85.320 113.850 90.290 ;
        RECT 114.090 88.290 114.330 95.110 ;
        RECT 115.550 94.530 128.020 95.300 ;
        RECT 127.630 90.330 128.730 91.330 ;
        RECT 129.930 88.330 130.170 95.150 ;
        RECT 130.410 92.830 130.650 95.150 ;
        RECT 130.330 90.330 130.730 92.830 ;
        RECT 114.020 87.290 116.540 88.290 ;
        RECT 114.020 85.790 114.420 87.290 ;
        RECT 121.420 86.300 122.260 86.420 ;
        RECT 119.980 85.940 126.260 86.300 ;
        RECT 114.090 85.320 114.330 85.790 ;
        RECT 109.500 85.130 109.790 85.160 ;
        RECT 109.980 85.130 110.270 85.160 ;
        RECT 110.460 85.130 110.750 85.160 ;
        RECT 110.940 85.130 111.230 85.160 ;
        RECT 111.420 85.130 111.710 85.160 ;
        RECT 111.900 85.130 112.190 85.160 ;
        RECT 112.380 85.130 112.670 85.160 ;
        RECT 112.860 85.130 113.150 85.160 ;
        RECT 113.340 85.130 113.630 85.160 ;
        RECT 113.820 85.150 114.110 85.160 ;
        RECT 115.540 85.150 119.010 85.920 ;
        RECT 119.980 85.860 125.900 85.940 ;
        RECT 113.790 85.130 119.010 85.150 ;
        RECT 109.405 84.960 119.010 85.130 ;
        RECT 109.500 84.930 109.790 84.960 ;
        RECT 109.980 84.930 110.270 84.960 ;
        RECT 110.460 84.930 110.750 84.960 ;
        RECT 110.940 84.930 111.230 84.960 ;
        RECT 111.420 84.930 111.710 84.960 ;
        RECT 111.900 84.930 112.190 84.960 ;
        RECT 112.380 84.930 112.670 84.960 ;
        RECT 112.860 84.930 113.150 84.960 ;
        RECT 113.340 84.930 113.630 84.960 ;
        RECT 113.790 84.920 119.010 84.960 ;
        RECT 48.940 84.630 51.020 84.640 ;
        RECT 48.940 83.180 115.540 84.630 ;
        RECT 48.940 81.740 115.530 83.180 ;
        RECT 48.940 81.730 51.020 81.740 ;
        RECT 116.970 81.450 117.970 84.920 ;
        RECT 120.660 84.380 121.020 85.660 ;
        RECT 121.260 84.380 121.620 85.860 ;
        RECT 121.900 84.380 122.260 85.860 ;
        RECT 122.500 84.460 122.860 85.660 ;
        RECT 123.140 84.620 123.500 85.860 ;
        RECT 123.740 84.740 124.100 85.660 ;
        RECT 123.740 84.620 124.140 84.740 ;
        RECT 124.380 84.620 124.740 85.860 ;
        RECT 129.850 85.830 130.250 88.330 ;
        RECT 124.980 84.740 125.340 85.660 ;
        RECT 129.930 85.360 130.170 85.830 ;
        RECT 130.410 85.360 130.650 90.330 ;
        RECT 130.890 88.330 131.130 95.160 ;
        RECT 131.370 92.830 131.610 95.150 ;
        RECT 131.850 95.140 132.080 95.150 ;
        RECT 132.330 95.140 132.560 95.150 ;
        RECT 131.290 90.330 131.690 92.830 ;
        RECT 130.810 85.830 131.210 88.330 ;
        RECT 130.890 85.370 131.130 85.830 ;
        RECT 130.890 85.360 131.120 85.370 ;
        RECT 131.370 85.360 131.610 90.330 ;
        RECT 131.850 88.330 132.090 95.140 ;
        RECT 132.330 92.830 132.570 95.140 ;
        RECT 132.250 90.330 132.650 92.830 ;
        RECT 131.770 85.830 132.170 88.330 ;
        RECT 131.850 85.350 132.090 85.830 ;
        RECT 132.330 85.350 132.570 90.330 ;
        RECT 132.810 88.330 133.050 95.150 ;
        RECT 133.290 92.830 133.530 95.150 ;
        RECT 133.210 90.330 133.610 92.830 ;
        RECT 132.730 85.830 133.130 88.330 ;
        RECT 132.810 85.360 133.050 85.830 ;
        RECT 133.290 85.360 133.530 90.330 ;
        RECT 133.760 88.330 134.000 95.150 ;
        RECT 134.250 92.830 134.490 95.150 ;
        RECT 134.170 90.330 134.570 92.830 ;
        RECT 133.690 85.830 134.090 88.330 ;
        RECT 133.760 85.360 134.000 85.830 ;
        RECT 134.250 85.360 134.490 90.330 ;
        RECT 134.730 88.330 134.970 95.150 ;
        RECT 136.190 94.570 145.990 95.340 ;
        RECT 137.020 94.530 138.080 94.570 ;
        RECT 136.430 88.330 137.550 88.420 ;
        RECT 134.660 87.330 137.550 88.330 ;
        RECT 134.660 85.830 135.060 87.330 ;
        RECT 136.430 87.270 137.550 87.330 ;
        RECT 136.180 85.930 137.190 85.960 ;
        RECT 134.730 85.360 134.970 85.830 ;
        RECT 130.140 85.170 130.430 85.200 ;
        RECT 130.620 85.170 130.910 85.200 ;
        RECT 131.100 85.170 131.390 85.200 ;
        RECT 131.580 85.170 131.870 85.200 ;
        RECT 132.060 85.170 132.350 85.200 ;
        RECT 132.540 85.170 132.830 85.200 ;
        RECT 133.020 85.170 133.310 85.200 ;
        RECT 133.500 85.170 133.790 85.200 ;
        RECT 133.980 85.170 134.270 85.200 ;
        RECT 134.460 85.190 134.750 85.200 ;
        RECT 136.180 85.190 144.030 85.930 ;
        RECT 134.430 85.170 144.030 85.190 ;
        RECT 130.045 85.000 144.030 85.170 ;
        RECT 130.140 84.970 130.430 85.000 ;
        RECT 130.620 84.970 130.910 85.000 ;
        RECT 131.100 84.970 131.390 85.000 ;
        RECT 131.580 84.970 131.870 85.000 ;
        RECT 132.060 84.970 132.350 85.000 ;
        RECT 132.540 84.970 132.830 85.000 ;
        RECT 133.020 84.970 133.310 85.000 ;
        RECT 133.500 84.970 133.790 85.000 ;
        RECT 133.980 84.970 134.270 85.000 ;
        RECT 134.430 84.960 144.030 85.000 ;
        RECT 136.750 84.920 144.030 84.960 ;
        RECT 124.980 84.620 125.380 84.740 ;
        RECT 122.500 84.380 122.900 84.460 ;
        RECT 120.660 84.180 120.940 84.380 ;
        RECT 122.740 84.300 122.900 84.380 ;
        RECT 123.420 84.300 123.820 84.420 ;
        RECT 120.660 84.060 121.340 84.180 ;
        RECT 122.180 84.060 122.580 84.180 ;
        RECT 120.660 83.900 122.580 84.060 ;
        RECT 120.660 83.780 121.340 83.900 ;
        RECT 122.180 83.780 122.580 83.900 ;
        RECT 122.740 84.140 123.820 84.300 ;
        RECT 120.100 83.180 120.460 83.540 ;
        RECT 109.490 81.410 109.780 81.440 ;
        RECT 109.970 81.410 110.260 81.440 ;
        RECT 110.450 81.410 110.740 81.440 ;
        RECT 110.930 81.410 111.220 81.440 ;
        RECT 111.410 81.410 111.700 81.440 ;
        RECT 111.890 81.410 112.180 81.440 ;
        RECT 112.370 81.410 112.660 81.440 ;
        RECT 112.850 81.410 113.140 81.440 ;
        RECT 113.330 81.410 113.620 81.440 ;
        RECT 113.780 81.410 117.970 81.450 ;
        RECT 109.395 81.240 117.970 81.410 ;
        RECT 109.490 81.210 109.780 81.240 ;
        RECT 109.970 81.210 110.260 81.240 ;
        RECT 110.450 81.210 110.740 81.240 ;
        RECT 110.930 81.210 111.220 81.240 ;
        RECT 111.410 81.210 111.700 81.240 ;
        RECT 111.890 81.210 112.180 81.240 ;
        RECT 112.370 81.210 112.660 81.240 ;
        RECT 112.850 81.210 113.140 81.240 ;
        RECT 113.330 81.210 113.620 81.240 ;
        RECT 113.780 81.220 117.970 81.240 ;
        RECT 113.810 81.210 114.100 81.220 ;
        RECT 109.280 80.580 109.520 81.050 ;
        RECT 109.200 78.080 109.600 80.580 ;
        RECT 106.980 75.080 108.080 76.080 ;
        RECT 109.280 71.260 109.520 78.080 ;
        RECT 109.760 76.080 110.000 81.050 ;
        RECT 110.240 81.040 110.470 81.050 ;
        RECT 110.240 80.580 110.480 81.040 ;
        RECT 110.160 78.080 110.560 80.580 ;
        RECT 109.680 73.580 110.080 76.080 ;
        RECT 109.760 71.260 110.000 73.580 ;
        RECT 110.240 71.250 110.480 78.080 ;
        RECT 110.720 76.080 110.960 81.050 ;
        RECT 111.200 80.580 111.440 81.060 ;
        RECT 111.120 78.080 111.520 80.580 ;
        RECT 110.640 73.580 111.040 76.080 ;
        RECT 110.720 71.260 110.960 73.580 ;
        RECT 111.200 71.270 111.440 78.080 ;
        RECT 111.680 76.080 111.920 81.060 ;
        RECT 112.160 80.580 112.400 81.050 ;
        RECT 112.080 78.080 112.480 80.580 ;
        RECT 111.600 73.580 112.000 76.080 ;
        RECT 111.680 71.270 111.920 73.580 ;
        RECT 111.200 71.260 111.430 71.270 ;
        RECT 111.680 71.260 111.910 71.270 ;
        RECT 112.160 71.260 112.400 78.080 ;
        RECT 112.640 76.080 112.880 81.050 ;
        RECT 113.110 80.580 113.350 81.050 ;
        RECT 113.040 78.080 113.440 80.580 ;
        RECT 112.560 73.580 112.960 76.080 ;
        RECT 112.640 71.260 112.880 73.580 ;
        RECT 113.110 71.260 113.350 78.080 ;
        RECT 113.600 76.080 113.840 81.050 ;
        RECT 114.080 80.580 114.320 81.050 ;
        RECT 114.010 79.080 114.410 80.580 ;
        RECT 115.530 80.450 117.970 81.220 ;
        RECT 120.660 82.940 120.940 83.780 ;
        RECT 121.140 83.420 121.500 83.540 ;
        RECT 122.180 83.420 122.580 83.540 ;
        RECT 121.140 83.260 122.580 83.420 ;
        RECT 121.140 83.180 121.500 83.260 ;
        RECT 122.180 83.140 122.580 83.260 ;
        RECT 122.740 82.940 122.900 84.140 ;
        RECT 123.420 84.020 123.820 84.140 ;
        RECT 123.980 84.300 124.140 84.620 ;
        RECT 124.660 84.300 125.060 84.420 ;
        RECT 123.980 84.140 125.060 84.300 ;
        RECT 123.980 83.820 124.140 84.140 ;
        RECT 124.660 84.020 125.060 84.140 ;
        RECT 125.220 84.300 125.380 84.620 ;
        RECT 125.220 84.140 126.620 84.300 ;
        RECT 125.220 83.820 125.380 84.140 ;
        RECT 123.140 83.300 123.500 83.820 ;
        RECT 123.740 83.700 124.140 83.820 ;
        RECT 123.740 83.300 124.100 83.700 ;
        RECT 124.380 83.300 124.740 83.820 ;
        RECT 124.980 83.700 125.380 83.820 ;
        RECT 124.980 83.300 125.340 83.700 ;
        RECT 123.140 83.100 123.300 83.300 ;
        RECT 124.380 83.100 124.540 83.300 ;
        RECT 128.680 83.230 136.180 84.670 ;
        RECT 123.140 82.940 124.540 83.100 ;
        RECT 128.670 83.220 136.180 83.230 ;
        RECT 120.660 81.140 121.020 82.940 ;
        RECT 121.260 81.340 121.620 82.940 ;
        RECT 121.900 81.340 122.260 82.940 ;
        RECT 121.260 81.140 122.260 81.340 ;
        RECT 122.500 82.820 122.900 82.940 ;
        RECT 122.500 81.140 122.860 82.820 ;
        RECT 123.420 82.260 123.820 82.660 ;
        RECT 124.100 82.060 124.380 82.940 ;
        RECT 124.660 82.260 125.340 82.660 ;
        RECT 125.060 82.060 125.340 82.260 ;
        RECT 123.140 81.140 123.500 82.060 ;
        RECT 123.740 81.900 124.740 82.060 ;
        RECT 123.740 81.340 124.100 81.900 ;
        RECT 124.380 81.340 124.740 81.900 ;
        RECT 123.740 81.140 124.740 81.340 ;
        RECT 121.900 80.940 122.060 81.140 ;
        RECT 123.140 80.940 123.380 81.140 ;
        RECT 120.940 80.820 121.340 80.940 ;
        RECT 120.380 80.660 121.340 80.820 ;
        RECT 121.900 80.780 123.380 80.940 ;
        RECT 120.940 80.540 121.340 80.660 ;
        RECT 120.500 79.980 121.100 80.180 ;
        RECT 124.100 79.980 124.380 81.140 ;
        RECT 124.980 80.140 125.340 82.060 ;
        RECT 128.670 81.780 136.170 83.220 ;
        RECT 130.130 81.450 130.420 81.480 ;
        RECT 130.610 81.450 130.900 81.480 ;
        RECT 131.090 81.450 131.380 81.480 ;
        RECT 131.570 81.450 131.860 81.480 ;
        RECT 132.050 81.450 132.340 81.480 ;
        RECT 132.530 81.450 132.820 81.480 ;
        RECT 133.010 81.450 133.300 81.480 ;
        RECT 133.490 81.450 133.780 81.480 ;
        RECT 133.970 81.450 134.260 81.480 ;
        RECT 134.420 81.450 144.010 81.490 ;
        RECT 130.035 81.280 144.010 81.450 ;
        RECT 130.130 81.250 130.420 81.280 ;
        RECT 130.610 81.250 130.900 81.280 ;
        RECT 131.090 81.250 131.380 81.280 ;
        RECT 131.570 81.250 131.860 81.280 ;
        RECT 132.050 81.250 132.340 81.280 ;
        RECT 132.530 81.250 132.820 81.280 ;
        RECT 133.010 81.250 133.300 81.280 ;
        RECT 133.490 81.250 133.780 81.280 ;
        RECT 133.970 81.250 134.260 81.280 ;
        RECT 134.420 81.260 144.010 81.280 ;
        RECT 134.450 81.250 134.740 81.260 ;
        RECT 129.920 80.620 130.160 81.090 ;
        RECT 119.980 79.580 125.900 79.980 ;
        RECT 114.010 78.080 116.530 79.080 ;
        RECT 129.840 78.120 130.240 80.620 ;
        RECT 113.520 73.580 113.920 76.080 ;
        RECT 113.600 71.260 113.840 73.580 ;
        RECT 114.080 71.260 114.320 78.080 ;
        RECT 127.620 75.120 128.720 76.120 ;
        RECT 115.540 71.070 127.020 71.840 ;
        RECT 129.920 71.300 130.160 78.120 ;
        RECT 130.400 76.120 130.640 81.090 ;
        RECT 130.880 81.080 131.110 81.090 ;
        RECT 130.880 80.620 131.120 81.080 ;
        RECT 130.800 78.120 131.200 80.620 ;
        RECT 130.320 73.620 130.720 76.120 ;
        RECT 130.400 71.300 130.640 73.620 ;
        RECT 130.880 71.290 131.120 78.120 ;
        RECT 131.360 76.120 131.600 81.090 ;
        RECT 131.840 80.620 132.080 81.100 ;
        RECT 131.760 78.120 132.160 80.620 ;
        RECT 131.280 73.620 131.680 76.120 ;
        RECT 131.360 71.300 131.600 73.620 ;
        RECT 131.840 71.310 132.080 78.120 ;
        RECT 132.320 76.120 132.560 81.100 ;
        RECT 132.800 80.620 133.040 81.090 ;
        RECT 132.720 78.120 133.120 80.620 ;
        RECT 132.240 73.620 132.640 76.120 ;
        RECT 132.320 71.310 132.560 73.620 ;
        RECT 131.840 71.300 132.070 71.310 ;
        RECT 132.320 71.300 132.550 71.310 ;
        RECT 132.800 71.300 133.040 78.120 ;
        RECT 133.280 76.120 133.520 81.090 ;
        RECT 133.750 80.620 133.990 81.090 ;
        RECT 133.680 78.120 134.080 80.620 ;
        RECT 133.200 73.620 133.600 76.120 ;
        RECT 133.280 71.300 133.520 73.620 ;
        RECT 133.750 71.300 133.990 78.120 ;
        RECT 134.240 76.120 134.480 81.090 ;
        RECT 134.720 80.620 134.960 81.090 ;
        RECT 134.650 79.120 135.050 80.620 ;
        RECT 136.170 80.490 144.010 81.260 ;
        RECT 136.450 79.120 138.050 79.190 ;
        RECT 134.650 78.120 138.050 79.120 ;
        RECT 134.160 73.620 134.560 76.120 ;
        RECT 134.240 71.300 134.480 73.620 ;
        RECT 134.720 71.300 134.960 78.120 ;
        RECT 136.180 71.110 146.030 71.880 ;
        RECT 135.630 71.100 146.030 71.110 ;
        RECT 134.460 71.095 146.030 71.100 ;
        RECT 114.990 71.060 127.020 71.070 ;
        RECT 130.130 71.065 130.420 71.095 ;
        RECT 130.610 71.065 130.900 71.095 ;
        RECT 131.090 71.065 131.380 71.095 ;
        RECT 131.570 71.065 131.860 71.095 ;
        RECT 132.050 71.065 132.340 71.095 ;
        RECT 132.530 71.065 132.820 71.095 ;
        RECT 133.010 71.065 133.300 71.095 ;
        RECT 133.490 71.065 133.780 71.095 ;
        RECT 133.970 71.065 134.260 71.095 ;
        RECT 134.450 71.065 146.030 71.095 ;
        RECT 113.820 71.055 127.020 71.060 ;
        RECT 109.490 71.025 109.780 71.055 ;
        RECT 109.970 71.025 110.260 71.055 ;
        RECT 110.450 71.025 110.740 71.055 ;
        RECT 110.930 71.025 111.220 71.055 ;
        RECT 111.410 71.025 111.700 71.055 ;
        RECT 111.890 71.025 112.180 71.055 ;
        RECT 112.370 71.025 112.660 71.055 ;
        RECT 112.850 71.025 113.140 71.055 ;
        RECT 113.330 71.025 113.620 71.055 ;
        RECT 113.810 71.025 127.020 71.055 ;
        RECT 109.395 70.855 127.020 71.025 ;
        RECT 130.035 70.895 146.030 71.065 ;
        RECT 130.130 70.865 130.420 70.895 ;
        RECT 130.610 70.865 130.900 70.895 ;
        RECT 131.090 70.865 131.380 70.895 ;
        RECT 131.570 70.865 131.860 70.895 ;
        RECT 132.050 70.865 132.340 70.895 ;
        RECT 132.530 70.865 132.820 70.895 ;
        RECT 133.010 70.865 133.300 70.895 ;
        RECT 133.490 70.865 133.780 70.895 ;
        RECT 133.970 70.865 134.260 70.895 ;
        RECT 134.450 70.880 146.030 70.895 ;
        RECT 134.450 70.870 136.280 70.880 ;
        RECT 134.450 70.865 134.740 70.870 ;
        RECT 109.490 70.825 109.780 70.855 ;
        RECT 109.970 70.825 110.260 70.855 ;
        RECT 110.450 70.825 110.740 70.855 ;
        RECT 110.930 70.825 111.220 70.855 ;
        RECT 111.410 70.825 111.700 70.855 ;
        RECT 111.890 70.825 112.180 70.855 ;
        RECT 112.370 70.825 112.660 70.855 ;
        RECT 112.850 70.825 113.140 70.855 ;
        RECT 113.330 70.825 113.620 70.855 ;
        RECT 113.810 70.840 127.020 70.855 ;
        RECT 136.720 70.840 137.780 70.880 ;
        RECT 113.810 70.830 115.640 70.840 ;
        RECT 113.810 70.825 114.100 70.830 ;
        RECT 0.950 70.530 3.040 70.540 ;
        RECT 128.670 70.530 136.170 70.570 ;
        RECT 0.950 69.090 136.170 70.530 ;
        RECT 1.005 69.080 136.170 69.090 ;
        RECT 128.670 67.680 136.170 69.080 ;
        RECT 130.130 67.355 130.420 67.385 ;
        RECT 130.610 67.355 130.900 67.385 ;
        RECT 131.090 67.355 131.380 67.385 ;
        RECT 131.570 67.355 131.860 67.385 ;
        RECT 132.050 67.355 132.340 67.385 ;
        RECT 132.530 67.355 132.820 67.385 ;
        RECT 133.010 67.355 133.300 67.385 ;
        RECT 133.490 67.355 133.780 67.385 ;
        RECT 133.970 67.355 134.260 67.385 ;
        RECT 134.450 67.380 134.740 67.385 ;
        RECT 134.450 67.370 136.280 67.380 ;
        RECT 134.450 67.355 146.040 67.370 ;
        RECT 130.035 67.185 146.040 67.355 ;
        RECT 130.130 67.155 130.420 67.185 ;
        RECT 130.610 67.155 130.900 67.185 ;
        RECT 131.090 67.155 131.380 67.185 ;
        RECT 131.570 67.155 131.860 67.185 ;
        RECT 132.050 67.155 132.340 67.185 ;
        RECT 132.530 67.155 132.820 67.185 ;
        RECT 133.010 67.155 133.300 67.185 ;
        RECT 133.490 67.155 133.780 67.185 ;
        RECT 133.970 67.155 134.260 67.185 ;
        RECT 134.450 67.155 146.040 67.185 ;
        RECT 134.460 67.150 146.040 67.155 ;
        RECT 135.630 67.140 146.040 67.150 ;
        RECT 127.620 62.130 128.720 63.130 ;
        RECT 129.920 60.130 130.160 66.950 ;
        RECT 130.400 64.630 130.640 66.950 ;
        RECT 130.320 62.130 130.720 64.630 ;
        RECT 129.840 57.630 130.240 60.130 ;
        RECT 129.920 57.160 130.160 57.630 ;
        RECT 130.400 57.160 130.640 62.130 ;
        RECT 130.880 60.130 131.120 66.960 ;
        RECT 131.360 64.630 131.600 66.950 ;
        RECT 131.840 66.940 132.070 66.950 ;
        RECT 132.320 66.940 132.550 66.950 ;
        RECT 131.280 62.130 131.680 64.630 ;
        RECT 130.800 57.630 131.200 60.130 ;
        RECT 130.880 57.170 131.120 57.630 ;
        RECT 130.880 57.160 131.110 57.170 ;
        RECT 131.360 57.160 131.600 62.130 ;
        RECT 131.840 60.130 132.080 66.940 ;
        RECT 132.320 64.630 132.560 66.940 ;
        RECT 132.240 62.130 132.640 64.630 ;
        RECT 131.760 57.630 132.160 60.130 ;
        RECT 131.840 57.150 132.080 57.630 ;
        RECT 132.320 57.150 132.560 62.130 ;
        RECT 132.800 60.130 133.040 66.950 ;
        RECT 133.280 64.630 133.520 66.950 ;
        RECT 133.200 62.130 133.600 64.630 ;
        RECT 132.720 57.630 133.120 60.130 ;
        RECT 132.800 57.160 133.040 57.630 ;
        RECT 133.280 57.160 133.520 62.130 ;
        RECT 133.750 60.130 133.990 66.950 ;
        RECT 134.240 64.630 134.480 66.950 ;
        RECT 134.160 62.130 134.560 64.630 ;
        RECT 133.680 57.630 134.080 60.130 ;
        RECT 133.750 57.160 133.990 57.630 ;
        RECT 134.240 57.160 134.480 62.130 ;
        RECT 134.720 60.130 134.960 66.950 ;
        RECT 136.180 66.370 146.040 67.140 ;
        RECT 134.650 59.130 137.560 60.130 ;
        RECT 134.650 57.630 135.050 59.130 ;
        RECT 134.720 57.160 134.960 57.630 ;
        RECT 130.130 56.970 130.420 57.000 ;
        RECT 130.610 56.970 130.900 57.000 ;
        RECT 131.090 56.970 131.380 57.000 ;
        RECT 131.570 56.970 131.860 57.000 ;
        RECT 132.050 56.970 132.340 57.000 ;
        RECT 132.530 56.970 132.820 57.000 ;
        RECT 133.010 56.970 133.300 57.000 ;
        RECT 133.490 56.970 133.780 57.000 ;
        RECT 133.970 56.970 134.260 57.000 ;
        RECT 134.450 56.990 134.740 57.000 ;
        RECT 136.170 56.990 144.020 57.760 ;
        RECT 134.420 56.970 144.020 56.990 ;
        RECT 130.035 56.800 144.020 56.970 ;
        RECT 130.130 56.770 130.420 56.800 ;
        RECT 130.610 56.770 130.900 56.800 ;
        RECT 131.090 56.770 131.380 56.800 ;
        RECT 131.570 56.770 131.860 56.800 ;
        RECT 132.050 56.770 132.340 56.800 ;
        RECT 132.530 56.770 132.820 56.800 ;
        RECT 133.010 56.770 133.300 56.800 ;
        RECT 133.490 56.770 133.780 56.800 ;
        RECT 133.970 56.770 134.260 56.800 ;
        RECT 134.420 56.760 144.020 56.800 ;
        RECT 48.940 55.040 136.170 56.470 ;
        RECT 49.055 55.020 136.170 55.040 ;
        RECT 0.950 51.510 3.050 51.520 ;
        RECT 0.950 50.070 136.160 51.510 ;
        RECT 1.005 50.060 136.160 50.070 ;
        RECT 99.550 50.010 107.050 50.060 ;
        RECT 130.120 49.735 130.410 49.765 ;
        RECT 130.600 49.735 130.890 49.765 ;
        RECT 131.080 49.735 131.370 49.765 ;
        RECT 131.560 49.735 131.850 49.765 ;
        RECT 132.040 49.735 132.330 49.765 ;
        RECT 132.520 49.735 132.810 49.765 ;
        RECT 133.000 49.735 133.290 49.765 ;
        RECT 133.480 49.735 133.770 49.765 ;
        RECT 133.960 49.735 134.250 49.765 ;
        RECT 134.440 49.760 134.730 49.765 ;
        RECT 134.440 49.750 136.270 49.760 ;
        RECT 134.440 49.740 137.170 49.750 ;
        RECT 134.440 49.735 137.210 49.740 ;
        RECT 101.010 49.685 101.300 49.715 ;
        RECT 101.490 49.685 101.780 49.715 ;
        RECT 101.970 49.685 102.260 49.715 ;
        RECT 102.450 49.685 102.740 49.715 ;
        RECT 102.930 49.685 103.220 49.715 ;
        RECT 103.410 49.685 103.700 49.715 ;
        RECT 103.890 49.685 104.180 49.715 ;
        RECT 104.370 49.685 104.660 49.715 ;
        RECT 104.850 49.685 105.140 49.715 ;
        RECT 105.330 49.710 105.620 49.715 ;
        RECT 105.330 49.700 107.160 49.710 ;
        RECT 127.040 49.700 128.040 49.730 ;
        RECT 105.330 49.685 128.040 49.700 ;
        RECT 100.915 49.515 128.040 49.685 ;
        RECT 130.025 49.565 137.210 49.735 ;
        RECT 130.120 49.535 130.410 49.565 ;
        RECT 130.600 49.535 130.890 49.565 ;
        RECT 131.080 49.535 131.370 49.565 ;
        RECT 131.560 49.535 131.850 49.565 ;
        RECT 132.040 49.535 132.330 49.565 ;
        RECT 132.520 49.535 132.810 49.565 ;
        RECT 133.000 49.535 133.290 49.565 ;
        RECT 133.480 49.535 133.770 49.565 ;
        RECT 133.960 49.535 134.250 49.565 ;
        RECT 134.440 49.535 137.210 49.565 ;
        RECT 134.450 49.530 137.210 49.535 ;
        RECT 135.620 49.520 137.210 49.530 ;
        RECT 101.010 49.485 101.300 49.515 ;
        RECT 101.490 49.485 101.780 49.515 ;
        RECT 101.970 49.485 102.260 49.515 ;
        RECT 102.450 49.485 102.740 49.515 ;
        RECT 102.930 49.485 103.220 49.515 ;
        RECT 103.410 49.485 103.700 49.515 ;
        RECT 103.890 49.485 104.180 49.515 ;
        RECT 104.370 49.485 104.660 49.515 ;
        RECT 104.850 49.485 105.140 49.515 ;
        RECT 105.330 49.485 128.040 49.515 ;
        RECT 105.340 49.480 128.040 49.485 ;
        RECT 106.510 49.470 128.040 49.480 ;
        RECT 98.500 44.460 99.600 45.460 ;
        RECT 100.800 42.460 101.040 49.280 ;
        RECT 101.280 46.960 101.520 49.280 ;
        RECT 101.200 44.460 101.600 46.960 ;
        RECT 100.720 39.960 101.120 42.460 ;
        RECT 100.800 39.490 101.040 39.960 ;
        RECT 101.280 39.490 101.520 44.460 ;
        RECT 101.760 42.460 102.000 49.290 ;
        RECT 102.240 46.960 102.480 49.280 ;
        RECT 102.720 49.270 102.950 49.280 ;
        RECT 103.200 49.270 103.430 49.280 ;
        RECT 102.160 44.460 102.560 46.960 ;
        RECT 101.680 39.960 102.080 42.460 ;
        RECT 101.760 39.500 102.000 39.960 ;
        RECT 101.760 39.490 101.990 39.500 ;
        RECT 102.240 39.490 102.480 44.460 ;
        RECT 102.720 42.460 102.960 49.270 ;
        RECT 103.200 46.960 103.440 49.270 ;
        RECT 103.120 44.460 103.520 46.960 ;
        RECT 102.640 39.960 103.040 42.460 ;
        RECT 102.720 39.480 102.960 39.960 ;
        RECT 103.200 39.480 103.440 44.460 ;
        RECT 103.680 42.460 103.920 49.280 ;
        RECT 104.160 46.960 104.400 49.280 ;
        RECT 104.080 44.460 104.480 46.960 ;
        RECT 103.600 39.960 104.000 42.460 ;
        RECT 103.680 39.490 103.920 39.960 ;
        RECT 104.160 39.490 104.400 44.460 ;
        RECT 104.630 42.460 104.870 49.280 ;
        RECT 105.120 46.960 105.360 49.280 ;
        RECT 105.040 44.460 105.440 46.960 ;
        RECT 104.560 39.960 104.960 42.460 ;
        RECT 104.630 39.490 104.870 39.960 ;
        RECT 105.120 39.490 105.360 44.460 ;
        RECT 105.600 42.460 105.840 49.280 ;
        RECT 107.060 48.700 128.040 49.470 ;
        RECT 127.040 48.670 128.040 48.700 ;
        RECT 109.630 45.500 125.930 46.000 ;
        RECT 115.130 44.600 118.130 45.100 ;
        RECT 116.930 44.380 118.130 44.600 ;
        RECT 110.330 43.800 111.930 44.300 ;
        RECT 112.350 44.210 112.640 44.240 ;
        RECT 112.830 44.210 113.120 44.240 ;
        RECT 113.310 44.210 113.600 44.240 ;
        RECT 112.255 44.040 113.695 44.210 ;
        RECT 116.530 44.100 116.700 44.265 ;
        RECT 116.930 44.150 123.935 44.380 ;
        RECT 125.430 44.300 125.930 45.500 ;
        RECT 127.610 44.510 128.710 45.510 ;
        RECT 116.930 44.100 118.130 44.150 ;
        RECT 112.350 44.010 112.640 44.040 ;
        RECT 112.830 44.010 113.120 44.040 ;
        RECT 113.310 44.010 113.600 44.040 ;
        RECT 110.330 42.600 111.130 43.800 ;
        RECT 112.140 42.600 112.370 43.805 ;
        RECT 112.620 43.800 112.850 43.805 ;
        RECT 112.530 43.300 112.930 43.800 ;
        RECT 105.530 41.460 108.050 42.460 ;
        RECT 110.330 42.100 112.430 42.600 ;
        RECT 112.620 42.135 112.850 43.300 ;
        RECT 113.100 42.600 113.330 43.805 ;
        RECT 113.580 43.800 113.810 43.805 ;
        RECT 113.530 43.300 115.330 43.800 ;
        RECT 116.500 43.640 116.730 44.100 ;
        RECT 116.530 43.310 116.700 43.640 ;
        RECT 122.630 43.590 123.530 43.800 ;
        RECT 116.935 43.360 123.935 43.590 ;
        RECT 113.030 42.100 113.430 42.600 ;
        RECT 113.580 42.135 113.810 43.300 ;
        RECT 105.530 39.960 105.930 41.460 ;
        RECT 107.450 40.090 109.070 40.100 ;
        RECT 105.600 39.490 105.840 39.960 ;
        RECT 101.010 39.300 101.300 39.330 ;
        RECT 101.490 39.300 101.780 39.330 ;
        RECT 101.970 39.300 102.260 39.330 ;
        RECT 102.450 39.300 102.740 39.330 ;
        RECT 102.930 39.300 103.220 39.330 ;
        RECT 103.410 39.300 103.700 39.330 ;
        RECT 103.890 39.300 104.180 39.330 ;
        RECT 104.370 39.300 104.660 39.330 ;
        RECT 104.850 39.300 105.140 39.330 ;
        RECT 105.330 39.320 105.620 39.330 ;
        RECT 107.050 39.320 109.070 40.090 ;
        RECT 105.300 39.300 109.070 39.320 ;
        RECT 100.915 39.130 109.070 39.300 ;
        RECT 101.010 39.100 101.300 39.130 ;
        RECT 101.490 39.100 101.780 39.130 ;
        RECT 101.970 39.100 102.260 39.130 ;
        RECT 102.450 39.100 102.740 39.130 ;
        RECT 102.930 39.100 103.220 39.130 ;
        RECT 103.410 39.100 103.700 39.130 ;
        RECT 103.890 39.100 104.180 39.130 ;
        RECT 104.370 39.100 104.660 39.130 ;
        RECT 104.850 39.100 105.140 39.130 ;
        RECT 105.300 39.090 109.070 39.130 ;
        RECT 110.330 39.800 111.130 42.100 ;
        RECT 112.350 41.900 112.640 41.930 ;
        RECT 112.830 41.900 113.120 41.930 ;
        RECT 113.310 41.900 113.600 41.930 ;
        RECT 112.230 41.200 113.730 41.900 ;
        RECT 112.255 41.190 113.695 41.200 ;
        RECT 112.350 41.160 112.640 41.190 ;
        RECT 112.830 41.160 113.120 41.190 ;
        RECT 113.310 41.160 113.600 41.190 ;
        RECT 114.630 41.000 115.330 43.300 ;
        RECT 116.500 42.850 116.730 43.310 ;
        RECT 122.630 43.100 123.530 43.360 ;
        RECT 116.530 42.520 116.700 42.850 ;
        RECT 116.930 42.800 118.130 43.000 ;
        RECT 116.930 42.570 123.935 42.800 ;
        RECT 116.500 42.060 116.730 42.520 ;
        RECT 116.930 42.400 118.130 42.570 ;
        RECT 116.530 41.895 116.700 42.060 ;
        RECT 122.630 42.010 123.530 42.200 ;
        RECT 116.935 41.780 123.935 42.010 ;
        RECT 124.130 41.900 125.930 44.300 ;
        RECT 129.910 42.510 130.150 49.330 ;
        RECT 130.390 47.010 130.630 49.330 ;
        RECT 130.310 44.510 130.710 47.010 ;
        RECT 124.170 41.895 124.340 41.900 ;
        RECT 122.630 41.100 123.530 41.780 ;
        RECT 112.140 39.800 112.370 40.955 ;
        RECT 112.530 40.500 112.930 41.000 ;
        RECT 110.330 39.300 112.430 39.800 ;
        RECT 48.940 37.350 107.050 38.800 ;
        RECT 48.940 35.910 107.040 37.350 ;
        RECT 108.020 35.620 109.020 39.090 ;
        RECT 110.330 37.900 111.130 39.300 ;
        RECT 112.140 39.285 112.370 39.300 ;
        RECT 112.620 39.285 112.850 40.500 ;
        RECT 113.100 39.800 113.330 40.955 ;
        RECT 113.530 40.500 115.330 41.000 ;
        RECT 113.030 39.300 113.430 39.800 ;
        RECT 113.100 39.285 113.330 39.300 ;
        RECT 113.580 39.285 113.810 40.500 ;
        RECT 114.630 39.700 115.330 40.500 ;
        RECT 119.430 40.500 125.030 41.100 ;
        RECT 119.430 39.910 119.930 40.500 ;
        RECT 122.070 39.910 124.030 39.940 ;
        RECT 116.040 39.700 117.350 39.810 ;
        RECT 119.305 39.740 120.095 39.910 ;
        RECT 121.905 39.740 124.195 39.910 ;
        RECT 119.430 39.700 119.930 39.740 ;
        RECT 122.070 39.710 124.030 39.740 ;
        RECT 109.630 37.200 111.130 37.900 ;
        RECT 101.000 35.580 101.290 35.610 ;
        RECT 101.480 35.580 101.770 35.610 ;
        RECT 101.960 35.580 102.250 35.610 ;
        RECT 102.440 35.580 102.730 35.610 ;
        RECT 102.920 35.580 103.210 35.610 ;
        RECT 103.400 35.580 103.690 35.610 ;
        RECT 103.880 35.580 104.170 35.610 ;
        RECT 104.360 35.580 104.650 35.610 ;
        RECT 104.840 35.580 105.130 35.610 ;
        RECT 105.290 35.580 109.020 35.620 ;
        RECT 100.905 35.410 109.020 35.580 ;
        RECT 101.000 35.380 101.290 35.410 ;
        RECT 101.480 35.380 101.770 35.410 ;
        RECT 101.960 35.380 102.250 35.410 ;
        RECT 102.440 35.380 102.730 35.410 ;
        RECT 102.920 35.380 103.210 35.410 ;
        RECT 103.400 35.380 103.690 35.410 ;
        RECT 103.880 35.380 104.170 35.410 ;
        RECT 104.360 35.380 104.650 35.410 ;
        RECT 104.840 35.380 105.130 35.410 ;
        RECT 105.290 35.390 109.020 35.410 ;
        RECT 105.320 35.380 105.610 35.390 ;
        RECT 100.790 34.750 101.030 35.220 ;
        RECT 100.710 32.250 101.110 34.750 ;
        RECT 98.490 29.250 99.590 30.250 ;
        RECT 100.790 25.430 101.030 32.250 ;
        RECT 101.270 30.250 101.510 35.220 ;
        RECT 101.750 35.210 101.980 35.220 ;
        RECT 101.750 34.750 101.990 35.210 ;
        RECT 101.670 32.250 102.070 34.750 ;
        RECT 101.190 27.750 101.590 30.250 ;
        RECT 101.270 25.430 101.510 27.750 ;
        RECT 101.750 25.420 101.990 32.250 ;
        RECT 102.230 30.250 102.470 35.220 ;
        RECT 102.710 34.750 102.950 35.230 ;
        RECT 102.630 32.250 103.030 34.750 ;
        RECT 102.150 27.750 102.550 30.250 ;
        RECT 102.230 25.430 102.470 27.750 ;
        RECT 102.710 25.440 102.950 32.250 ;
        RECT 103.190 30.250 103.430 35.230 ;
        RECT 103.670 34.750 103.910 35.220 ;
        RECT 103.590 32.250 103.990 34.750 ;
        RECT 103.110 27.750 103.510 30.250 ;
        RECT 103.190 25.440 103.430 27.750 ;
        RECT 102.710 25.430 102.940 25.440 ;
        RECT 103.190 25.430 103.420 25.440 ;
        RECT 103.670 25.430 103.910 32.250 ;
        RECT 104.150 30.250 104.390 35.220 ;
        RECT 104.620 34.750 104.860 35.220 ;
        RECT 104.550 32.250 104.950 34.750 ;
        RECT 104.070 27.750 104.470 30.250 ;
        RECT 104.150 25.430 104.390 27.750 ;
        RECT 104.620 25.430 104.860 32.250 ;
        RECT 105.110 30.250 105.350 35.220 ;
        RECT 105.590 34.750 105.830 35.220 ;
        RECT 105.520 33.250 105.920 34.750 ;
        RECT 107.040 34.620 109.020 35.390 ;
        RECT 110.330 35.700 111.130 37.200 ;
        RECT 112.230 38.800 113.730 39.100 ;
        RECT 114.630 38.800 117.350 39.700 ;
        RECT 119.190 39.500 119.420 39.550 ;
        RECT 119.980 39.500 120.210 39.550 ;
        RECT 121.790 39.500 122.020 39.550 ;
        RECT 124.080 39.500 124.310 39.550 ;
        RECT 124.530 39.500 125.030 40.500 ;
        RECT 112.230 37.800 117.350 38.800 ;
        RECT 112.230 35.900 113.730 37.800 ;
        RECT 116.040 37.705 117.350 37.800 ;
        RECT 117.930 39.100 119.430 39.500 ;
        RECT 119.980 39.100 122.030 39.500 ;
        RECT 117.930 39.000 119.030 39.100 ;
        RECT 119.190 39.050 119.420 39.100 ;
        RECT 119.980 39.050 120.210 39.100 ;
        RECT 116.040 37.200 117.350 37.265 ;
        RECT 116.030 37.100 117.350 37.200 ;
        RECT 117.930 37.100 118.630 39.000 ;
        RECT 120.530 38.900 122.030 39.100 ;
        RECT 119.470 38.860 119.930 38.890 ;
        RECT 119.305 38.690 120.095 38.860 ;
        RECT 119.470 38.660 119.930 38.690 ;
        RECT 112.140 35.700 112.370 35.705 ;
        RECT 110.330 35.200 112.430 35.700 ;
        RECT 105.520 32.250 108.040 33.250 ;
        RECT 110.330 32.800 111.130 35.200 ;
        RECT 112.140 34.035 112.370 35.200 ;
        RECT 112.620 34.500 112.850 35.705 ;
        RECT 113.100 35.700 113.330 35.705 ;
        RECT 113.030 35.200 113.430 35.700 ;
        RECT 112.530 34.000 112.930 34.500 ;
        RECT 113.100 34.035 113.330 35.200 ;
        RECT 113.580 34.500 113.810 35.705 ;
        RECT 114.630 34.500 115.330 36.900 ;
        RECT 113.530 34.000 115.330 34.500 ;
        RECT 116.030 36.100 118.630 37.100 ;
        RECT 119.470 36.410 119.930 36.440 ;
        RECT 119.305 36.240 120.095 36.410 ;
        RECT 119.470 36.210 119.930 36.240 ;
        RECT 120.530 36.200 121.530 38.900 ;
        RECT 121.790 38.800 122.020 38.900 ;
        RECT 124.030 38.800 125.030 39.500 ;
        RECT 122.070 38.610 124.030 38.640 ;
        RECT 121.905 38.440 124.195 38.610 ;
        RECT 122.070 38.410 124.030 38.440 ;
        RECT 122.130 38.200 123.930 38.410 ;
        RECT 125.430 38.200 125.930 41.900 ;
        RECT 129.830 40.010 130.230 42.510 ;
        RECT 129.910 39.540 130.150 40.010 ;
        RECT 130.390 39.540 130.630 44.510 ;
        RECT 130.870 42.510 131.110 49.340 ;
        RECT 131.350 47.010 131.590 49.330 ;
        RECT 131.830 49.320 132.060 49.330 ;
        RECT 132.310 49.320 132.540 49.330 ;
        RECT 131.270 44.510 131.670 47.010 ;
        RECT 130.790 40.010 131.190 42.510 ;
        RECT 130.870 39.550 131.110 40.010 ;
        RECT 130.870 39.540 131.100 39.550 ;
        RECT 131.350 39.540 131.590 44.510 ;
        RECT 131.830 42.510 132.070 49.320 ;
        RECT 132.310 47.010 132.550 49.320 ;
        RECT 132.230 44.510 132.630 47.010 ;
        RECT 131.750 40.010 132.150 42.510 ;
        RECT 131.830 39.530 132.070 40.010 ;
        RECT 132.310 39.530 132.550 44.510 ;
        RECT 132.790 42.510 133.030 49.330 ;
        RECT 133.270 47.010 133.510 49.330 ;
        RECT 133.190 44.510 133.590 47.010 ;
        RECT 132.710 40.010 133.110 42.510 ;
        RECT 132.790 39.540 133.030 40.010 ;
        RECT 133.270 39.540 133.510 44.510 ;
        RECT 133.740 42.510 133.980 49.330 ;
        RECT 134.230 47.010 134.470 49.330 ;
        RECT 134.150 44.510 134.550 47.010 ;
        RECT 133.670 40.010 134.070 42.510 ;
        RECT 133.740 39.540 133.980 40.010 ;
        RECT 134.230 39.540 134.470 44.510 ;
        RECT 134.710 42.510 134.950 49.330 ;
        RECT 136.110 48.700 137.210 49.520 ;
        RECT 136.300 42.510 137.760 42.580 ;
        RECT 134.640 41.510 137.760 42.510 ;
        RECT 134.640 40.010 135.040 41.510 ;
        RECT 136.300 41.430 137.760 41.510 ;
        RECT 136.120 40.140 137.540 40.150 ;
        RECT 134.710 39.540 134.950 40.010 ;
        RECT 130.120 39.350 130.410 39.380 ;
        RECT 130.600 39.350 130.890 39.380 ;
        RECT 131.080 39.350 131.370 39.380 ;
        RECT 131.560 39.350 131.850 39.380 ;
        RECT 132.040 39.350 132.330 39.380 ;
        RECT 132.520 39.350 132.810 39.380 ;
        RECT 133.000 39.350 133.290 39.380 ;
        RECT 133.480 39.350 133.770 39.380 ;
        RECT 133.960 39.350 134.250 39.380 ;
        RECT 134.440 39.370 134.730 39.380 ;
        RECT 136.120 39.370 142.040 40.140 ;
        RECT 134.410 39.350 142.040 39.370 ;
        RECT 130.025 39.180 142.040 39.350 ;
        RECT 130.120 39.150 130.410 39.180 ;
        RECT 130.600 39.150 130.890 39.180 ;
        RECT 131.080 39.150 131.370 39.180 ;
        RECT 131.560 39.150 131.850 39.180 ;
        RECT 132.040 39.150 132.330 39.180 ;
        RECT 132.520 39.150 132.810 39.180 ;
        RECT 133.000 39.150 133.290 39.180 ;
        RECT 133.480 39.150 133.770 39.180 ;
        RECT 133.960 39.150 134.250 39.180 ;
        RECT 134.410 39.140 142.040 39.180 ;
        RECT 136.120 39.090 137.540 39.140 ;
        RECT 122.130 37.700 125.930 38.200 ;
        RECT 128.660 37.410 136.160 38.850 ;
        RECT 128.650 37.400 136.160 37.410 ;
        RECT 122.130 36.800 125.930 37.300 ;
        RECT 122.130 36.640 123.930 36.800 ;
        RECT 122.070 36.610 124.030 36.640 ;
        RECT 121.905 36.440 124.195 36.610 ;
        RECT 122.070 36.410 124.030 36.440 ;
        RECT 122.130 36.400 123.930 36.410 ;
        RECT 121.790 36.200 122.020 36.250 ;
        RECT 124.080 36.200 124.310 36.250 ;
        RECT 116.030 36.000 119.030 36.100 ;
        RECT 119.190 36.000 119.420 36.050 ;
        RECT 119.980 36.000 120.210 36.050 ;
        RECT 120.530 36.000 122.030 36.200 ;
        RECT 116.030 35.600 119.430 36.000 ;
        RECT 119.980 35.600 122.030 36.000 ;
        RECT 116.030 35.160 117.350 35.600 ;
        RECT 119.190 35.550 119.420 35.600 ;
        RECT 119.980 35.550 120.210 35.600 ;
        RECT 121.790 35.500 122.020 35.600 ;
        RECT 124.080 35.500 125.030 36.200 ;
        RECT 119.430 35.360 119.930 35.400 ;
        RECT 119.305 35.190 120.095 35.360 ;
        RECT 122.070 35.310 124.030 35.340 ;
        RECT 116.030 34.400 117.330 35.160 ;
        RECT 119.430 34.500 119.930 35.190 ;
        RECT 121.905 35.140 124.195 35.310 ;
        RECT 122.070 35.110 124.030 35.140 ;
        RECT 124.530 34.500 125.030 35.500 ;
        RECT 112.350 33.800 112.640 33.830 ;
        RECT 112.830 33.800 113.120 33.830 ;
        RECT 113.310 33.800 113.600 33.830 ;
        RECT 112.230 33.100 113.730 33.800 ;
        RECT 112.255 33.090 113.695 33.100 ;
        RECT 112.350 33.060 112.640 33.090 ;
        RECT 112.830 33.060 113.120 33.090 ;
        RECT 113.310 33.060 113.600 33.090 ;
        RECT 112.140 32.800 112.370 32.855 ;
        RECT 110.330 32.300 112.430 32.800 ;
        RECT 105.030 27.750 105.430 30.250 ;
        RECT 105.110 25.430 105.350 27.750 ;
        RECT 105.590 25.430 105.830 32.250 ;
        RECT 110.330 31.200 111.130 32.300 ;
        RECT 110.330 30.700 111.930 31.200 ;
        RECT 112.140 31.185 112.370 32.300 ;
        RECT 112.620 31.700 112.850 32.855 ;
        RECT 113.100 32.800 113.330 32.855 ;
        RECT 113.030 32.300 113.430 32.800 ;
        RECT 112.530 31.200 112.930 31.700 ;
        RECT 112.620 31.185 112.850 31.200 ;
        RECT 113.100 31.185 113.330 32.300 ;
        RECT 113.580 31.700 113.810 32.855 ;
        RECT 114.630 31.700 115.330 34.000 ;
        RECT 119.430 33.900 125.030 34.500 ;
        RECT 122.630 33.180 123.530 33.900 ;
        RECT 116.530 32.900 116.700 33.065 ;
        RECT 116.935 32.950 123.935 33.180 ;
        RECT 125.430 33.100 125.930 36.800 ;
        RECT 128.650 35.960 136.150 37.400 ;
        RECT 130.110 35.630 130.400 35.660 ;
        RECT 130.590 35.630 130.880 35.660 ;
        RECT 131.070 35.630 131.360 35.660 ;
        RECT 131.550 35.630 131.840 35.660 ;
        RECT 132.030 35.630 132.320 35.660 ;
        RECT 132.510 35.630 132.800 35.660 ;
        RECT 132.990 35.630 133.280 35.660 ;
        RECT 133.470 35.630 133.760 35.660 ;
        RECT 133.950 35.630 134.240 35.660 ;
        RECT 134.400 35.630 142.060 35.670 ;
        RECT 130.015 35.460 142.060 35.630 ;
        RECT 130.110 35.430 130.400 35.460 ;
        RECT 130.590 35.430 130.880 35.460 ;
        RECT 131.070 35.430 131.360 35.460 ;
        RECT 131.550 35.430 131.840 35.460 ;
        RECT 132.030 35.430 132.320 35.460 ;
        RECT 132.510 35.430 132.800 35.460 ;
        RECT 132.990 35.430 133.280 35.460 ;
        RECT 133.470 35.430 133.760 35.460 ;
        RECT 133.950 35.430 134.240 35.460 ;
        RECT 134.400 35.440 142.060 35.460 ;
        RECT 134.430 35.430 134.720 35.440 ;
        RECT 129.900 34.800 130.140 35.270 ;
        RECT 116.500 32.440 116.730 32.900 ;
        RECT 122.630 32.800 123.530 32.950 ;
        RECT 116.530 32.110 116.700 32.440 ;
        RECT 117.030 32.390 118.130 32.600 ;
        RECT 116.935 32.160 123.935 32.390 ;
        RECT 113.530 31.200 115.330 31.700 ;
        RECT 116.500 31.650 116.730 32.110 ;
        RECT 117.030 32.000 118.130 32.160 ;
        RECT 116.530 31.320 116.700 31.650 ;
        RECT 122.630 31.600 123.530 31.800 ;
        RECT 116.935 31.370 123.935 31.600 ;
        RECT 113.580 31.185 113.810 31.200 ;
        RECT 112.350 30.950 112.640 30.980 ;
        RECT 112.830 30.950 113.120 30.980 ;
        RECT 113.310 30.950 113.600 30.980 ;
        RECT 112.255 30.780 113.695 30.950 ;
        RECT 112.350 30.750 112.640 30.780 ;
        RECT 112.830 30.750 113.120 30.780 ;
        RECT 113.310 30.750 113.600 30.780 ;
        RECT 114.630 30.400 115.330 31.200 ;
        RECT 116.500 30.860 116.730 31.320 ;
        RECT 122.630 31.200 123.530 31.370 ;
        RECT 116.530 30.695 116.700 30.860 ;
        RECT 117.030 30.810 118.130 31.000 ;
        RECT 116.935 30.580 123.935 30.810 ;
        RECT 124.130 30.700 125.930 33.100 ;
        RECT 129.820 32.300 130.220 34.800 ;
        RECT 124.170 30.695 124.340 30.700 ;
        RECT 117.030 30.400 118.130 30.580 ;
        RECT 114.630 29.900 118.630 30.400 ;
        RECT 125.430 29.500 125.930 30.700 ;
        RECT 109.630 29.000 125.930 29.500 ;
        RECT 127.600 29.300 128.700 30.300 ;
        RECT 107.050 25.240 128.070 26.010 ;
        RECT 129.900 25.480 130.140 32.300 ;
        RECT 130.380 30.300 130.620 35.270 ;
        RECT 130.860 35.260 131.090 35.270 ;
        RECT 130.860 34.800 131.100 35.260 ;
        RECT 130.780 32.300 131.180 34.800 ;
        RECT 130.300 27.800 130.700 30.300 ;
        RECT 130.380 25.480 130.620 27.800 ;
        RECT 130.860 25.470 131.100 32.300 ;
        RECT 131.340 30.300 131.580 35.270 ;
        RECT 131.820 34.800 132.060 35.280 ;
        RECT 131.740 32.300 132.140 34.800 ;
        RECT 131.260 27.800 131.660 30.300 ;
        RECT 131.340 25.480 131.580 27.800 ;
        RECT 131.820 25.490 132.060 32.300 ;
        RECT 132.300 30.300 132.540 35.280 ;
        RECT 132.780 34.800 133.020 35.270 ;
        RECT 132.700 32.300 133.100 34.800 ;
        RECT 132.220 27.800 132.620 30.300 ;
        RECT 132.300 25.490 132.540 27.800 ;
        RECT 131.820 25.480 132.050 25.490 ;
        RECT 132.300 25.480 132.530 25.490 ;
        RECT 132.780 25.480 133.020 32.300 ;
        RECT 133.260 30.300 133.500 35.270 ;
        RECT 133.730 34.800 133.970 35.270 ;
        RECT 133.660 32.300 134.060 34.800 ;
        RECT 133.180 27.800 133.580 30.300 ;
        RECT 133.260 25.480 133.500 27.800 ;
        RECT 133.730 25.480 133.970 32.300 ;
        RECT 134.220 30.300 134.460 35.270 ;
        RECT 134.700 34.800 134.940 35.270 ;
        RECT 134.630 33.300 135.030 34.800 ;
        RECT 136.150 34.670 142.060 35.440 ;
        RECT 136.450 33.300 138.050 33.310 ;
        RECT 134.630 32.310 138.050 33.300 ;
        RECT 134.630 32.300 137.150 32.310 ;
        RECT 134.140 27.800 134.540 30.300 ;
        RECT 134.220 25.480 134.460 27.800 ;
        RECT 134.700 25.480 134.940 32.300 ;
        RECT 136.160 26.030 137.160 26.060 ;
        RECT 136.090 25.290 137.190 26.030 ;
        RECT 135.610 25.280 137.190 25.290 ;
        RECT 134.440 25.275 137.190 25.280 ;
        RECT 130.110 25.245 130.400 25.275 ;
        RECT 130.590 25.245 130.880 25.275 ;
        RECT 131.070 25.245 131.360 25.275 ;
        RECT 131.550 25.245 131.840 25.275 ;
        RECT 132.030 25.245 132.320 25.275 ;
        RECT 132.510 25.245 132.800 25.275 ;
        RECT 132.990 25.245 133.280 25.275 ;
        RECT 133.470 25.245 133.760 25.275 ;
        RECT 133.950 25.245 134.240 25.275 ;
        RECT 134.430 25.245 137.190 25.275 ;
        RECT 106.500 25.230 128.070 25.240 ;
        RECT 105.330 25.225 128.070 25.230 ;
        RECT 101.000 25.195 101.290 25.225 ;
        RECT 101.480 25.195 101.770 25.225 ;
        RECT 101.960 25.195 102.250 25.225 ;
        RECT 102.440 25.195 102.730 25.225 ;
        RECT 102.920 25.195 103.210 25.225 ;
        RECT 103.400 25.195 103.690 25.225 ;
        RECT 103.880 25.195 104.170 25.225 ;
        RECT 104.360 25.195 104.650 25.225 ;
        RECT 104.840 25.195 105.130 25.225 ;
        RECT 105.320 25.195 128.070 25.225 ;
        RECT 100.905 25.025 128.070 25.195 ;
        RECT 130.015 25.075 137.190 25.245 ;
        RECT 130.110 25.045 130.400 25.075 ;
        RECT 130.590 25.045 130.880 25.075 ;
        RECT 131.070 25.045 131.360 25.075 ;
        RECT 131.550 25.045 131.840 25.075 ;
        RECT 132.030 25.045 132.320 25.075 ;
        RECT 132.510 25.045 132.800 25.075 ;
        RECT 132.990 25.045 133.280 25.075 ;
        RECT 133.470 25.045 133.760 25.075 ;
        RECT 133.950 25.045 134.240 25.075 ;
        RECT 134.430 25.050 137.190 25.075 ;
        RECT 134.430 25.045 134.720 25.050 ;
        RECT 101.000 24.995 101.290 25.025 ;
        RECT 101.480 24.995 101.770 25.025 ;
        RECT 101.960 24.995 102.250 25.025 ;
        RECT 102.440 24.995 102.730 25.025 ;
        RECT 102.920 24.995 103.210 25.025 ;
        RECT 103.400 24.995 103.690 25.025 ;
        RECT 103.880 24.995 104.170 25.025 ;
        RECT 104.360 24.995 104.650 25.025 ;
        RECT 104.840 24.995 105.130 25.025 ;
        RECT 105.320 25.010 128.070 25.025 ;
        RECT 105.320 25.000 107.150 25.010 ;
        RECT 105.320 24.995 105.610 25.000 ;
        RECT 136.090 24.990 137.190 25.050 ;
        RECT 128.650 24.700 136.150 24.750 ;
        RECT 1.055 24.690 136.150 24.700 ;
        RECT 0.940 23.250 136.150 24.690 ;
        RECT 0.940 23.240 3.040 23.250 ;
        RECT 128.650 21.860 136.150 23.250 ;
        RECT 130.110 21.535 130.400 21.565 ;
        RECT 130.590 21.535 130.880 21.565 ;
        RECT 131.070 21.535 131.360 21.565 ;
        RECT 131.550 21.535 131.840 21.565 ;
        RECT 132.030 21.535 132.320 21.565 ;
        RECT 132.510 21.535 132.800 21.565 ;
        RECT 132.990 21.535 133.280 21.565 ;
        RECT 133.470 21.535 133.760 21.565 ;
        RECT 133.950 21.535 134.240 21.565 ;
        RECT 134.430 21.560 134.720 21.565 ;
        RECT 134.430 21.550 136.260 21.560 ;
        RECT 134.430 21.535 140.030 21.550 ;
        RECT 130.015 21.365 140.030 21.535 ;
        RECT 130.110 21.335 130.400 21.365 ;
        RECT 130.590 21.335 130.880 21.365 ;
        RECT 131.070 21.335 131.360 21.365 ;
        RECT 131.550 21.335 131.840 21.365 ;
        RECT 132.030 21.335 132.320 21.365 ;
        RECT 132.510 21.335 132.800 21.365 ;
        RECT 132.990 21.335 133.280 21.365 ;
        RECT 133.470 21.335 133.760 21.365 ;
        RECT 133.950 21.335 134.240 21.365 ;
        RECT 134.430 21.335 140.030 21.365 ;
        RECT 134.440 21.330 140.030 21.335 ;
        RECT 135.610 21.320 140.030 21.330 ;
        RECT 127.600 16.310 128.700 17.310 ;
        RECT 129.900 14.310 130.140 21.130 ;
        RECT 130.380 18.810 130.620 21.130 ;
        RECT 130.300 16.310 130.700 18.810 ;
        RECT 129.820 11.810 130.220 14.310 ;
        RECT 129.900 11.340 130.140 11.810 ;
        RECT 130.380 11.340 130.620 16.310 ;
        RECT 130.860 14.310 131.100 21.140 ;
        RECT 131.340 18.810 131.580 21.130 ;
        RECT 131.820 21.120 132.050 21.130 ;
        RECT 132.300 21.120 132.530 21.130 ;
        RECT 131.260 16.310 131.660 18.810 ;
        RECT 130.780 11.810 131.180 14.310 ;
        RECT 130.860 11.350 131.100 11.810 ;
        RECT 130.860 11.340 131.090 11.350 ;
        RECT 131.340 11.340 131.580 16.310 ;
        RECT 131.820 14.310 132.060 21.120 ;
        RECT 132.300 18.810 132.540 21.120 ;
        RECT 132.220 16.310 132.620 18.810 ;
        RECT 131.740 11.810 132.140 14.310 ;
        RECT 131.820 11.330 132.060 11.810 ;
        RECT 132.300 11.330 132.540 16.310 ;
        RECT 132.780 14.310 133.020 21.130 ;
        RECT 133.260 18.810 133.500 21.130 ;
        RECT 133.180 16.310 133.580 18.810 ;
        RECT 132.700 11.810 133.100 14.310 ;
        RECT 132.780 11.340 133.020 11.810 ;
        RECT 133.260 11.340 133.500 16.310 ;
        RECT 133.730 14.310 133.970 21.130 ;
        RECT 134.220 18.810 134.460 21.130 ;
        RECT 134.140 16.310 134.540 18.810 ;
        RECT 133.660 11.810 134.060 14.310 ;
        RECT 133.730 11.340 133.970 11.810 ;
        RECT 134.220 11.340 134.460 16.310 ;
        RECT 134.700 14.310 134.940 21.130 ;
        RECT 136.160 20.550 140.030 21.320 ;
        RECT 134.630 14.300 137.150 14.310 ;
        RECT 134.630 13.320 137.540 14.300 ;
        RECT 134.630 13.310 137.150 13.320 ;
        RECT 134.630 11.810 135.030 13.310 ;
        RECT 134.700 11.340 134.940 11.810 ;
        RECT 130.110 11.150 130.400 11.180 ;
        RECT 130.590 11.150 130.880 11.180 ;
        RECT 131.070 11.150 131.360 11.180 ;
        RECT 131.550 11.150 131.840 11.180 ;
        RECT 132.030 11.150 132.320 11.180 ;
        RECT 132.510 11.150 132.800 11.180 ;
        RECT 132.990 11.150 133.280 11.180 ;
        RECT 133.470 11.150 133.760 11.180 ;
        RECT 133.950 11.150 134.240 11.180 ;
        RECT 134.430 11.170 134.720 11.180 ;
        RECT 136.150 11.170 141.990 11.940 ;
        RECT 134.400 11.150 141.990 11.170 ;
        RECT 130.015 10.980 141.990 11.150 ;
        RECT 130.110 10.950 130.400 10.980 ;
        RECT 130.590 10.950 130.880 10.980 ;
        RECT 131.070 10.950 131.360 10.980 ;
        RECT 131.550 10.950 131.840 10.980 ;
        RECT 132.030 10.950 132.320 10.980 ;
        RECT 132.510 10.950 132.800 10.980 ;
        RECT 132.990 10.950 133.280 10.980 ;
        RECT 133.470 10.950 133.760 10.980 ;
        RECT 133.950 10.950 134.240 10.980 ;
        RECT 134.400 10.940 141.990 10.980 ;
        RECT 128.650 9.200 136.150 10.650 ;
      LAYER met2 ;
        RECT 137.990 222.000 138.990 222.050 ;
        RECT 135.000 221.500 139.000 222.000 ;
        RECT 84.020 220.990 85.030 221.060 ;
        RECT 86.030 220.990 87.040 221.070 ;
        RECT 88.020 220.990 89.030 221.070 ;
        RECT 90.020 220.990 91.030 221.080 ;
        RECT 92.030 220.990 93.040 221.060 ;
        RECT 94.020 220.990 95.030 221.050 ;
        RECT 84.000 219.440 85.030 220.990 ;
        RECT 86.000 219.450 87.040 220.990 ;
        RECT 88.010 219.450 89.030 220.990 ;
        RECT 89.990 219.460 91.030 220.990 ;
        RECT 84.000 218.980 85.000 219.440 ;
        RECT 86.000 218.980 87.000 219.450 ;
        RECT 88.010 218.980 89.010 219.450 ;
        RECT 89.990 218.980 90.990 219.460 ;
        RECT 92.000 219.440 93.040 220.990 ;
        RECT 92.000 218.980 93.000 219.440 ;
        RECT 94.000 219.430 95.030 220.990 ;
        RECT 94.000 218.980 95.000 219.430 ;
        RECT 48.980 212.600 51.010 215.780 ;
        RECT 1.000 207.040 2.980 210.370 ;
        RECT 48.970 200.460 50.960 202.040 ;
        RECT 1.010 194.840 2.990 197.800 ;
        RECT 48.990 186.130 51.030 187.780 ;
        RECT 1.010 181.410 3.000 183.330 ;
        RECT 1.000 175.770 2.990 177.610 ;
        RECT 48.990 171.350 51.030 173.000 ;
        RECT 1.000 166.860 3.010 168.450 ;
        RECT 49.000 161.900 50.980 164.060 ;
        RECT 84.000 162.990 84.980 218.980 ;
        RECT 86.000 163.000 86.980 218.980 ;
        RECT 88.010 163.010 88.990 218.980 ;
        RECT 89.990 163.000 90.970 218.980 ;
        RECT 92.000 163.000 92.980 218.980 ;
        RECT 94.000 203.780 94.980 218.980 ;
        RECT 100.000 217.910 108.470 221.030 ;
        RECT 122.330 220.720 122.630 220.730 ;
        RECT 122.295 220.440 122.665 220.720 ;
        RECT 120.200 217.090 120.600 217.300 ;
        RECT 120.160 216.390 120.610 217.090 ;
        RECT 122.330 216.930 122.630 220.440 ;
        RECT 126.490 220.010 126.770 220.045 ;
        RECT 124.400 217.090 124.800 217.300 ;
        RECT 120.990 216.550 123.750 216.930 ;
        RECT 124.300 216.390 124.800 217.090 ;
        RECT 126.480 216.930 126.780 220.010 ;
        RECT 130.470 219.330 130.750 219.365 ;
        RECT 128.500 217.090 128.900 217.300 ;
        RECT 125.130 216.550 127.890 216.930 ;
        RECT 128.440 216.390 128.900 217.090 ;
        RECT 130.460 216.930 130.760 219.330 ;
        RECT 132.700 217.090 133.100 217.300 ;
        RECT 129.270 216.550 132.030 216.930 ;
        RECT 132.580 216.390 133.100 217.090 ;
        RECT 135.015 216.930 135.485 221.500 ;
        RECT 137.990 221.440 138.990 221.500 ;
        RECT 133.410 216.550 136.170 216.930 ;
        RECT 120.200 215.000 120.600 216.390 ;
        RECT 124.400 215.000 124.800 216.390 ;
        RECT 128.500 215.000 128.900 216.390 ;
        RECT 132.700 215.000 133.100 216.390 ;
        RECT 120.200 214.500 121.500 215.000 ;
        RECT 124.400 214.500 125.700 215.000 ;
        RECT 128.500 214.500 129.800 215.000 ;
        RECT 132.700 214.500 134.000 215.000 ;
        RECT 121.000 211.500 121.500 214.500 ;
        RECT 123.990 211.660 124.310 211.810 ;
        RECT 120.910 211.120 123.670 211.500 ;
        RECT 121.000 211.000 121.500 211.120 ;
        RECT 100.000 207.270 108.470 210.390 ;
        RECT 122.980 205.640 123.300 211.120 ;
        RECT 123.990 210.960 124.500 211.660 ;
        RECT 125.200 211.500 125.700 214.500 ;
        RECT 128.130 211.660 128.450 211.790 ;
        RECT 125.050 211.120 127.810 211.500 ;
        RECT 125.200 211.000 125.700 211.120 ;
        RECT 123.990 206.180 124.310 210.960 ;
        RECT 127.090 206.690 127.410 211.120 ;
        RECT 128.130 210.960 128.640 211.660 ;
        RECT 129.300 211.500 129.800 214.500 ;
        RECT 129.190 211.120 131.950 211.500 ;
        RECT 129.300 211.000 129.800 211.120 ;
        RECT 128.130 207.160 128.450 210.960 ;
        RECT 130.880 208.770 131.400 211.120 ;
        RECT 132.290 209.740 132.810 211.770 ;
        RECT 133.500 211.500 134.000 214.500 ;
        RECT 136.470 211.500 136.920 211.660 ;
        RECT 133.330 211.120 136.090 211.500 ;
        RECT 133.500 211.000 134.000 211.120 ;
        RECT 135.140 210.760 135.660 211.120 ;
        RECT 136.470 211.020 145.730 211.500 ;
        RECT 136.470 210.960 136.920 211.020 ;
        RECT 135.140 210.620 135.650 210.760 ;
        RECT 135.140 210.240 143.760 210.620 ;
        RECT 132.290 209.220 141.790 209.740 ;
        RECT 130.880 208.250 139.770 208.770 ;
        RECT 128.130 206.840 136.660 207.160 ;
        RECT 127.090 206.370 134.630 206.690 ;
        RECT 123.990 205.860 132.670 206.180 ;
        RECT 122.980 205.320 130.660 205.640 ;
        RECT 118.990 204.670 120.050 204.720 ;
        RECT 124.100 204.670 126.250 204.680 ;
        RECT 118.990 204.400 126.250 204.670 ;
        RECT 130.340 204.560 130.660 205.320 ;
        RECT 132.350 204.610 132.670 205.860 ;
        RECT 134.310 204.660 134.630 206.370 ;
        RECT 136.340 204.760 136.660 206.840 ;
        RECT 139.250 205.510 139.770 208.250 ;
        RECT 138.960 204.970 139.980 205.510 ;
        RECT 141.270 205.500 141.790 209.220 ;
        RECT 143.240 205.500 143.760 210.240 ;
        RECT 140.980 205.020 142.000 205.500 ;
        RECT 142.960 205.020 143.980 205.500 ;
        RECT 145.250 205.170 145.730 211.020 ;
        RECT 118.990 204.240 120.050 204.400 ;
        RECT 121.630 204.360 122.730 204.400 ;
        RECT 124.100 204.390 126.250 204.400 ;
        RECT 116.010 203.980 116.360 204.080 ;
        RECT 119.000 203.980 120.110 204.030 ;
        RECT 94.000 202.800 105.040 203.780 ;
        RECT 112.260 203.630 120.110 203.980 ;
        RECT 108.590 203.140 108.890 203.570 ;
        RECT 109.890 203.170 110.190 203.560 ;
        RECT 94.000 163.000 94.980 202.800 ;
        RECT 113.160 202.020 113.410 203.630 ;
        RECT 113.100 200.470 113.540 202.020 ;
        RECT 116.110 201.580 116.260 203.630 ;
        RECT 118.360 203.625 118.760 203.630 ;
        RECT 119.000 203.580 120.110 203.630 ;
        RECT 116.760 202.480 117.160 202.930 ;
        RECT 119.010 201.830 119.260 203.580 ;
        RECT 122.850 203.440 123.110 203.470 ;
        RECT 122.850 203.180 129.490 203.440 ;
        RECT 122.850 203.150 123.110 203.180 ;
        RECT 132.440 203.150 132.700 203.470 ;
        RECT 125.095 202.505 125.545 202.535 ;
        RECT 125.095 202.055 129.265 202.505 ;
        RECT 125.095 202.025 125.545 202.055 ;
        RECT 134.315 202.025 134.765 202.535 ;
        RECT 116.010 201.030 116.410 201.580 ;
        RECT 118.960 200.530 119.310 201.830 ;
        RECT 125.105 200.915 125.555 200.945 ;
        RECT 125.105 200.465 130.235 200.915 ;
        RECT 125.105 200.435 125.555 200.465 ;
        RECT 97.490 199.620 98.470 199.650 ;
        RECT 97.490 198.640 105.020 199.620 ;
        RECT 115.960 199.480 116.510 199.830 ;
        RECT 116.710 199.780 117.110 200.230 ;
        RECT 122.800 199.960 123.150 200.150 ;
        RECT 122.800 199.680 129.570 199.960 ;
        RECT 136.410 199.680 136.750 199.960 ;
        RECT 122.800 199.530 123.150 199.680 ;
        RECT 108.590 198.890 108.890 199.320 ;
        RECT 109.890 198.900 110.190 199.290 ;
        RECT 97.490 198.610 98.470 198.640 ;
        RECT 116.110 198.630 116.410 199.480 ;
        RECT 118.990 199.330 120.090 199.350 ;
        RECT 126.660 199.330 127.030 199.450 ;
        RECT 118.990 198.920 127.030 199.330 ;
        RECT 118.990 198.890 120.090 198.920 ;
        RECT 119.000 198.650 120.100 198.680 ;
        RECT 124.100 198.650 126.250 198.670 ;
        RECT 116.110 198.230 116.510 198.630 ;
        RECT 119.000 198.400 126.250 198.650 ;
        RECT 119.000 198.180 120.100 198.400 ;
        RECT 121.630 198.350 122.730 198.400 ;
        RECT 124.100 198.380 126.250 198.400 ;
        RECT 126.660 198.000 127.030 198.920 ;
        RECT 117.690 194.990 118.720 195.050 ;
        RECT 105.030 194.490 118.730 194.990 ;
        RECT 110.030 192.790 110.630 192.890 ;
        RECT 112.430 192.790 112.830 194.490 ;
        RECT 117.690 194.430 118.720 194.490 ;
        RECT 119.040 193.710 120.100 193.760 ;
        RECT 124.150 193.710 126.300 193.720 ;
        RECT 119.040 193.440 126.300 193.710 ;
        RECT 119.040 193.280 120.100 193.440 ;
        RECT 121.680 193.400 122.780 193.440 ;
        RECT 124.150 193.430 126.300 193.440 ;
        RECT 113.230 192.790 113.830 192.890 ;
        RECT 110.030 192.490 113.830 192.790 ;
        RECT 110.030 192.290 110.630 192.490 ;
        RECT 100.620 188.830 100.920 189.260 ;
        RECT 101.920 188.860 102.220 189.250 ;
        RECT 110.730 188.340 111.130 188.740 ;
        RECT 112.430 188.040 112.830 192.490 ;
        RECT 113.230 192.390 113.830 192.490 ;
        RECT 122.890 192.260 123.170 192.390 ;
        RECT 122.890 192.000 129.470 192.260 ;
        RECT 122.890 191.890 123.170 192.000 ;
        RECT 132.420 191.970 132.680 192.290 ;
        RECT 125.065 191.490 125.515 191.520 ;
        RECT 129.055 191.490 129.505 191.520 ;
        RECT 125.065 191.040 129.505 191.490 ;
        RECT 125.065 191.010 125.515 191.040 ;
        RECT 129.055 191.010 129.505 191.040 ;
        RECT 134.365 191.010 134.815 191.520 ;
        RECT 112.380 187.940 112.830 188.040 ;
        RECT 111.430 187.790 112.830 187.940 ;
        RECT 111.430 187.390 111.580 187.790 ;
        RECT 112.380 187.690 112.830 187.790 ;
        RECT 111.330 186.840 111.730 187.390 ;
        RECT 110.680 185.390 111.080 185.840 ;
        RECT 100.620 184.580 100.920 185.010 ;
        RECT 101.920 184.590 102.220 184.980 ;
        RECT 111.130 182.690 111.730 183.190 ;
        RECT 111.230 179.790 111.630 182.690 ;
        RECT 125.055 182.015 125.505 182.045 ;
        RECT 125.055 181.565 130.645 182.015 ;
        RECT 125.055 181.535 125.505 181.565 ;
        RECT 125.185 181.135 125.475 181.165 ;
        RECT 125.185 180.845 129.525 181.135 ;
        RECT 125.185 180.815 125.475 180.845 ;
        RECT 136.435 180.815 136.725 181.165 ;
        RECT 119.040 180.500 120.140 180.520 ;
        RECT 126.710 180.500 127.080 180.620 ;
        RECT 119.040 180.090 127.080 180.500 ;
        RECT 119.040 180.060 120.140 180.090 ;
        RECT 111.130 179.290 111.630 179.790 ;
        RECT 119.050 179.820 120.150 179.850 ;
        RECT 124.150 179.820 126.300 179.840 ;
        RECT 119.050 179.570 126.300 179.820 ;
        RECT 119.050 179.350 120.150 179.570 ;
        RECT 121.680 179.520 122.780 179.570 ;
        RECT 124.150 179.550 126.300 179.570 ;
        RECT 126.710 179.170 127.080 180.090 ;
        RECT 116.630 176.500 117.380 176.550 ;
        RECT 119.270 176.500 119.790 176.620 ;
        RECT 116.630 176.200 119.790 176.500 ;
        RECT 116.630 176.150 117.380 176.200 ;
        RECT 119.270 176.120 119.790 176.200 ;
        RECT 98.500 175.640 99.000 175.720 ;
        RECT 124.150 175.640 126.300 175.650 ;
        RECT 98.500 175.370 126.300 175.640 ;
        RECT 98.500 175.300 99.000 175.370 ;
        RECT 96.170 174.080 96.470 174.510 ;
        RECT 97.470 174.110 97.770 174.500 ;
        RECT 103.730 174.110 104.000 174.280 ;
        RECT 102.880 173.030 103.120 174.110 ;
        RECT 102.800 172.450 103.200 173.030 ;
        RECT 102.880 171.130 103.120 172.450 ;
        RECT 103.720 171.130 104.020 174.110 ;
        RECT 105.490 173.770 106.450 175.370 ;
        RECT 107.200 174.920 107.500 174.970 ;
        RECT 107.200 174.570 108.020 174.920 ;
        RECT 107.200 174.510 107.500 174.570 ;
        RECT 106.980 170.560 107.260 174.110 ;
        RECT 96.170 169.830 96.470 170.260 ;
        RECT 97.470 169.840 97.770 170.230 ;
        RECT 109.925 169.845 110.420 175.215 ;
        RECT 112.575 173.825 112.845 175.370 ;
        RECT 121.680 175.330 122.780 175.370 ;
        RECT 124.150 175.360 126.300 175.370 ;
        RECT 120.370 174.520 121.320 174.970 ;
        RECT 122.900 174.410 123.160 174.440 ;
        RECT 122.900 174.150 129.140 174.410 ;
        RECT 122.900 174.120 123.160 174.150 ;
        RECT 132.350 174.120 132.610 174.440 ;
        RECT 125.145 173.475 125.595 173.505 ;
        RECT 125.145 173.025 129.215 173.475 ;
        RECT 125.145 172.995 125.595 173.025 ;
        RECT 134.255 172.995 134.705 173.505 ;
        RECT 125.155 171.885 125.605 171.915 ;
        RECT 125.155 171.435 130.335 171.885 ;
        RECT 125.155 171.405 125.605 171.435 ;
        RECT 112.580 170.940 112.840 171.260 ;
        RECT 98.500 169.620 99.000 169.690 ;
        RECT 102.520 169.620 103.480 169.680 ;
        RECT 112.585 169.620 112.835 170.940 ;
        RECT 122.850 170.930 123.200 171.120 ;
        RECT 122.850 170.650 129.270 170.930 ;
        RECT 136.360 170.650 136.700 170.930 ;
        RECT 122.850 170.500 123.200 170.650 ;
        RECT 124.150 169.620 126.300 169.640 ;
        RECT 98.475 169.370 126.300 169.620 ;
        RECT 98.500 169.300 99.000 169.370 ;
        RECT 102.520 169.310 103.480 169.370 ;
        RECT 121.680 169.320 122.780 169.370 ;
        RECT 124.150 169.350 126.300 169.370 ;
        RECT 109.990 168.820 110.370 169.200 ;
        RECT 126.710 168.910 127.080 170.470 ;
        RECT 96.210 165.490 96.510 165.500 ;
        RECT 97.510 165.490 97.810 165.510 ;
        RECT 96.210 165.110 97.810 165.490 ;
        RECT 97.510 165.080 97.810 165.110 ;
        RECT 0.990 95.780 3.000 97.330 ;
        RECT 126.990 95.530 127.990 95.560 ;
        RECT 137.050 95.530 138.050 95.560 ;
        RECT 126.990 94.530 138.050 95.530 ;
        RECT 144.960 94.540 145.960 95.600 ;
        RECT 126.990 94.500 127.990 94.530 ;
        RECT 137.050 94.500 138.050 94.530 ;
        RECT 109.740 92.790 110.040 92.840 ;
        RECT 110.700 92.790 111.000 92.840 ;
        RECT 111.660 92.790 111.960 92.840 ;
        RECT 112.620 92.790 112.920 92.840 ;
        RECT 113.580 92.790 113.880 92.840 ;
        RECT 55.210 91.350 56.110 91.410 ;
        RECT 55.210 91.290 108.090 91.350 ;
        RECT 109.740 91.290 113.880 92.790 ;
        RECT 130.380 92.830 130.680 92.880 ;
        RECT 131.340 92.830 131.640 92.880 ;
        RECT 132.300 92.830 132.600 92.880 ;
        RECT 133.260 92.830 133.560 92.880 ;
        RECT 134.220 92.830 134.520 92.880 ;
        RECT 55.210 90.310 113.880 91.290 ;
        RECT 55.210 90.290 110.040 90.310 ;
        RECT 55.210 90.230 108.090 90.290 ;
        RECT 109.740 90.240 110.040 90.290 ;
        RECT 110.700 90.240 111.000 90.310 ;
        RECT 111.660 90.240 111.960 90.310 ;
        RECT 112.620 90.240 112.920 90.310 ;
        RECT 113.580 90.240 113.880 90.310 ;
        RECT 127.680 91.330 128.680 91.380 ;
        RECT 130.380 91.330 134.520 92.830 ;
        RECT 127.680 90.350 134.520 91.330 ;
        RECT 127.680 90.330 130.680 90.350 ;
        RECT 127.680 90.280 128.680 90.330 ;
        RECT 130.380 90.280 130.680 90.330 ;
        RECT 131.340 90.280 131.640 90.350 ;
        RECT 132.300 90.280 132.600 90.350 ;
        RECT 133.260 90.280 133.560 90.350 ;
        RECT 134.220 90.280 134.520 90.350 ;
        RECT 55.210 90.190 56.110 90.230 ;
        RECT 109.260 88.290 109.560 88.340 ;
        RECT 110.220 88.290 110.520 88.340 ;
        RECT 111.180 88.290 111.480 88.340 ;
        RECT 112.140 88.290 112.440 88.340 ;
        RECT 113.100 88.290 113.400 88.340 ;
        RECT 114.070 88.290 114.370 88.340 ;
        RECT 109.260 85.780 114.370 88.290 ;
        RECT 129.900 88.330 130.200 88.380 ;
        RECT 130.860 88.330 131.160 88.380 ;
        RECT 131.820 88.330 132.120 88.380 ;
        RECT 132.780 88.330 133.080 88.380 ;
        RECT 133.740 88.330 134.040 88.380 ;
        RECT 134.710 88.330 135.010 88.380 ;
        RECT 109.260 85.740 109.560 85.780 ;
        RECT 110.220 85.740 110.520 85.780 ;
        RECT 111.180 85.740 111.480 85.780 ;
        RECT 112.140 85.740 112.440 85.780 ;
        RECT 113.100 85.740 113.400 85.780 ;
        RECT 114.070 85.740 114.370 85.780 ;
        RECT 117.930 84.860 119.040 85.960 ;
        RECT 129.900 85.820 135.010 88.330 ;
        RECT 136.480 87.220 137.500 88.470 ;
        RECT 129.900 85.780 130.200 85.820 ;
        RECT 130.860 85.780 131.160 85.820 ;
        RECT 131.820 85.780 132.120 85.820 ;
        RECT 132.780 85.780 133.080 85.820 ;
        RECT 133.740 85.780 134.040 85.820 ;
        RECT 134.710 85.780 135.010 85.820 ;
        RECT 136.800 85.950 138.000 85.970 ;
        RECT 136.800 84.890 138.010 85.950 ;
        RECT 136.800 84.870 138.000 84.890 ;
        RECT 142.970 84.870 143.980 85.980 ;
        RECT 48.990 81.680 50.970 84.690 ;
        RECT 129.890 80.630 130.190 80.670 ;
        RECT 130.850 80.630 131.150 80.670 ;
        RECT 131.810 80.630 132.110 80.670 ;
        RECT 132.770 80.630 133.070 80.670 ;
        RECT 133.730 80.630 134.030 80.670 ;
        RECT 134.700 80.630 135.000 80.670 ;
        RECT 109.250 80.590 109.550 80.630 ;
        RECT 110.210 80.590 110.510 80.630 ;
        RECT 111.170 80.590 111.470 80.630 ;
        RECT 112.130 80.590 112.430 80.630 ;
        RECT 113.090 80.590 113.390 80.630 ;
        RECT 114.060 80.590 114.360 80.630 ;
        RECT 109.250 78.080 114.360 80.590 ;
        RECT 109.250 78.030 109.550 78.080 ;
        RECT 110.210 78.030 110.510 78.080 ;
        RECT 111.170 78.030 111.470 78.080 ;
        RECT 112.130 78.030 112.430 78.080 ;
        RECT 113.090 78.030 113.390 78.080 ;
        RECT 114.060 78.030 114.360 78.080 ;
        RECT 129.890 78.120 135.000 80.630 ;
        RECT 142.980 80.460 143.980 81.520 ;
        RECT 129.890 78.070 130.190 78.120 ;
        RECT 130.850 78.070 131.150 78.120 ;
        RECT 131.810 78.070 132.110 78.120 ;
        RECT 132.770 78.070 133.070 78.120 ;
        RECT 133.730 78.070 134.030 78.120 ;
        RECT 134.700 78.070 135.000 78.120 ;
        RECT 136.500 78.070 138.000 79.240 ;
        RECT 74.530 76.140 75.430 76.190 ;
        RECT 74.530 76.080 108.090 76.140 ;
        RECT 109.730 76.080 110.030 76.130 ;
        RECT 74.530 76.060 110.030 76.080 ;
        RECT 110.690 76.060 110.990 76.130 ;
        RECT 111.650 76.060 111.950 76.130 ;
        RECT 112.610 76.060 112.910 76.130 ;
        RECT 113.570 76.060 113.870 76.130 ;
        RECT 74.530 75.080 113.870 76.060 ;
        RECT 74.530 75.020 108.090 75.080 ;
        RECT 74.530 74.980 75.430 75.020 ;
        RECT 109.730 73.580 113.870 75.080 ;
        RECT 127.670 76.120 128.670 76.170 ;
        RECT 130.370 76.120 130.670 76.170 ;
        RECT 127.670 76.100 130.670 76.120 ;
        RECT 131.330 76.100 131.630 76.170 ;
        RECT 132.290 76.100 132.590 76.170 ;
        RECT 133.250 76.100 133.550 76.170 ;
        RECT 134.210 76.100 134.510 76.170 ;
        RECT 127.670 75.120 134.510 76.100 ;
        RECT 127.670 75.070 128.670 75.120 ;
        RECT 109.730 73.530 110.030 73.580 ;
        RECT 110.690 73.530 110.990 73.580 ;
        RECT 111.650 73.530 111.950 73.580 ;
        RECT 112.610 73.530 112.910 73.580 ;
        RECT 113.570 73.530 113.870 73.580 ;
        RECT 130.370 73.620 134.510 75.120 ;
        RECT 130.370 73.570 130.670 73.620 ;
        RECT 131.330 73.570 131.630 73.620 ;
        RECT 132.290 73.570 132.590 73.620 ;
        RECT 133.250 73.570 133.550 73.620 ;
        RECT 134.210 73.570 134.510 73.620 ;
        RECT 125.990 71.840 126.990 71.870 ;
        RECT 136.750 71.840 137.750 71.870 ;
        RECT 125.990 70.840 137.750 71.840 ;
        RECT 145.000 70.850 146.000 71.910 ;
        RECT 125.990 70.810 126.990 70.840 ;
        RECT 136.750 70.810 137.750 70.840 ;
        RECT 1.000 69.040 2.990 70.590 ;
        RECT 130.370 64.630 130.670 64.680 ;
        RECT 131.330 64.630 131.630 64.680 ;
        RECT 132.290 64.630 132.590 64.680 ;
        RECT 133.250 64.630 133.550 64.680 ;
        RECT 134.210 64.630 134.510 64.680 ;
        RECT 127.670 63.130 128.670 63.180 ;
        RECT 130.370 63.130 134.510 64.630 ;
        RECT 127.670 62.150 134.510 63.130 ;
        RECT 127.670 62.130 130.670 62.150 ;
        RECT 127.670 62.080 128.670 62.130 ;
        RECT 130.370 62.080 130.670 62.130 ;
        RECT 131.330 62.080 131.630 62.150 ;
        RECT 132.290 62.080 132.590 62.150 ;
        RECT 133.250 62.080 133.550 62.150 ;
        RECT 134.210 62.080 134.510 62.150 ;
        RECT 129.890 60.130 130.190 60.180 ;
        RECT 130.850 60.130 131.150 60.180 ;
        RECT 131.810 60.130 132.110 60.180 ;
        RECT 132.770 60.130 133.070 60.180 ;
        RECT 133.730 60.130 134.030 60.180 ;
        RECT 134.700 60.130 135.000 60.180 ;
        RECT 129.890 57.620 135.000 60.130 ;
        RECT 136.180 59.080 137.510 60.180 ;
        RECT 129.890 57.580 130.190 57.620 ;
        RECT 130.850 57.580 131.150 57.620 ;
        RECT 131.810 57.580 132.110 57.620 ;
        RECT 132.770 57.580 133.070 57.620 ;
        RECT 133.730 57.580 134.030 57.620 ;
        RECT 134.700 57.580 135.000 57.620 ;
        RECT 142.990 56.730 143.990 57.790 ;
        RECT 145.010 56.670 146.010 67.400 ;
        RECT 48.990 54.990 50.980 56.520 ;
        RECT 1.000 50.020 3.000 51.570 ;
        RECT 136.160 49.700 137.160 49.790 ;
        RECT 127.010 48.700 139.840 49.700 ;
        RECT 136.160 48.650 137.160 48.700 ;
        RECT 130.360 47.010 130.660 47.060 ;
        RECT 131.320 47.010 131.620 47.060 ;
        RECT 132.280 47.010 132.580 47.060 ;
        RECT 133.240 47.010 133.540 47.060 ;
        RECT 134.200 47.010 134.500 47.060 ;
        RECT 101.250 46.960 101.550 47.010 ;
        RECT 102.210 46.960 102.510 47.010 ;
        RECT 103.170 46.960 103.470 47.010 ;
        RECT 104.130 46.960 104.430 47.010 ;
        RECT 105.090 46.960 105.390 47.010 ;
        RECT 55.210 45.520 56.110 45.580 ;
        RECT 101.250 45.520 105.390 46.960 ;
        RECT 55.210 44.400 107.040 45.520 ;
        RECT 127.660 45.510 128.660 45.560 ;
        RECT 130.360 45.510 134.500 47.010 ;
        RECT 55.210 44.360 56.110 44.400 ;
        RECT 112.530 43.300 114.330 43.800 ;
        RECT 115.130 43.000 115.630 45.100 ;
        RECT 127.660 44.530 134.500 45.510 ;
        RECT 127.660 44.510 130.660 44.530 ;
        RECT 127.660 44.460 128.660 44.510 ;
        RECT 130.360 44.460 130.660 44.510 ;
        RECT 131.320 44.460 131.620 44.530 ;
        RECT 132.280 44.460 132.580 44.530 ;
        RECT 133.240 44.460 133.540 44.530 ;
        RECT 134.200 44.460 134.500 44.530 ;
        RECT 100.770 42.460 101.070 42.510 ;
        RECT 101.730 42.460 102.030 42.510 ;
        RECT 102.690 42.460 102.990 42.510 ;
        RECT 103.650 42.460 103.950 42.510 ;
        RECT 104.610 42.460 104.910 42.510 ;
        RECT 105.580 42.460 105.880 42.510 ;
        RECT 100.770 39.950 105.880 42.460 ;
        RECT 111.530 42.100 113.430 42.600 ;
        RECT 115.130 42.400 118.130 43.000 ;
        RECT 112.530 40.500 114.330 41.000 ;
        RECT 100.770 39.910 101.070 39.950 ;
        RECT 101.730 39.910 102.030 39.950 ;
        RECT 102.690 39.910 102.990 39.950 ;
        RECT 103.650 39.910 103.950 39.950 ;
        RECT 104.610 39.910 104.910 39.950 ;
        RECT 105.580 39.910 105.880 39.950 ;
        RECT 107.500 39.040 109.020 40.150 ;
        RECT 111.530 39.300 113.430 39.800 ;
        RECT 48.990 35.860 50.990 38.850 ;
        RECT 115.130 36.900 115.630 42.400 ;
        RECT 122.630 41.100 123.530 43.800 ;
        RECT 129.880 42.510 130.180 42.560 ;
        RECT 130.840 42.510 131.140 42.560 ;
        RECT 131.800 42.510 132.100 42.560 ;
        RECT 132.760 42.510 133.060 42.560 ;
        RECT 133.720 42.510 134.020 42.560 ;
        RECT 134.690 42.510 134.990 42.560 ;
        RECT 122.630 40.500 126.530 41.100 ;
        RECT 129.880 40.000 134.990 42.510 ;
        RECT 136.350 41.380 137.710 42.630 ;
        RECT 129.880 39.960 130.180 40.000 ;
        RECT 130.840 39.960 131.140 40.000 ;
        RECT 131.800 39.960 132.100 40.000 ;
        RECT 132.760 39.960 133.060 40.000 ;
        RECT 133.720 39.960 134.020 40.000 ;
        RECT 134.690 39.960 134.990 40.000 ;
        RECT 136.170 39.040 137.490 40.200 ;
        RECT 141.010 39.110 142.010 40.170 ;
        RECT 114.630 36.400 115.630 36.900 ;
        RECT 111.530 35.200 113.430 35.700 ;
        RECT 100.760 34.760 101.060 34.800 ;
        RECT 101.720 34.760 102.020 34.800 ;
        RECT 102.680 34.760 102.980 34.800 ;
        RECT 103.640 34.760 103.940 34.800 ;
        RECT 104.600 34.760 104.900 34.800 ;
        RECT 105.570 34.760 105.870 34.800 ;
        RECT 100.760 32.250 105.870 34.760 ;
        RECT 112.530 34.000 115.130 34.500 ;
        RECT 115.530 34.400 117.330 34.900 ;
        RECT 129.870 34.810 130.170 34.850 ;
        RECT 130.830 34.810 131.130 34.850 ;
        RECT 131.790 34.810 132.090 34.850 ;
        RECT 132.750 34.810 133.050 34.850 ;
        RECT 133.710 34.810 134.010 34.850 ;
        RECT 134.680 34.810 134.980 34.850 ;
        RECT 111.530 32.300 113.430 32.800 ;
        RECT 100.760 32.200 101.060 32.250 ;
        RECT 101.720 32.200 102.020 32.250 ;
        RECT 102.680 32.200 102.980 32.250 ;
        RECT 103.640 32.200 103.940 32.250 ;
        RECT 104.600 32.200 104.900 32.250 ;
        RECT 105.570 32.200 105.870 32.250 ;
        RECT 112.530 31.200 115.130 31.700 ;
        RECT 115.530 30.800 116.030 34.400 ;
        RECT 122.630 33.900 126.530 34.500 ;
        RECT 74.530 30.310 75.430 30.360 ;
        RECT 74.530 30.250 99.580 30.310 ;
        RECT 101.240 30.250 101.540 30.300 ;
        RECT 74.530 30.230 101.540 30.250 ;
        RECT 102.200 30.230 102.500 30.300 ;
        RECT 103.160 30.230 103.460 30.300 ;
        RECT 104.120 30.230 104.420 30.300 ;
        RECT 105.080 30.230 105.380 30.300 ;
        RECT 74.530 29.250 105.380 30.230 ;
        RECT 109.630 30.100 116.030 30.800 ;
        RECT 117.030 29.900 118.130 32.600 ;
        RECT 122.630 31.200 123.530 33.900 ;
        RECT 129.870 32.300 134.980 34.810 ;
        RECT 141.030 34.640 142.030 35.700 ;
        RECT 129.870 32.250 130.170 32.300 ;
        RECT 130.830 32.250 131.130 32.300 ;
        RECT 131.790 32.250 132.090 32.300 ;
        RECT 132.750 32.250 133.050 32.300 ;
        RECT 133.710 32.250 134.010 32.300 ;
        RECT 134.680 32.250 134.980 32.300 ;
        RECT 136.500 32.260 138.000 33.360 ;
        RECT 127.650 30.300 128.650 30.350 ;
        RECT 130.350 30.300 130.650 30.350 ;
        RECT 127.650 30.280 130.650 30.300 ;
        RECT 131.310 30.280 131.610 30.350 ;
        RECT 132.270 30.280 132.570 30.350 ;
        RECT 133.230 30.280 133.530 30.350 ;
        RECT 134.190 30.280 134.490 30.350 ;
        RECT 127.650 29.300 134.490 30.280 ;
        RECT 127.650 29.250 128.650 29.300 ;
        RECT 74.530 29.190 99.580 29.250 ;
        RECT 74.530 29.150 75.430 29.190 ;
        RECT 101.240 27.750 105.380 29.250 ;
        RECT 130.350 27.800 134.490 29.300 ;
        RECT 130.350 27.750 130.650 27.800 ;
        RECT 131.310 27.750 131.610 27.800 ;
        RECT 132.270 27.750 132.570 27.800 ;
        RECT 133.230 27.750 133.530 27.800 ;
        RECT 134.190 27.750 134.490 27.800 ;
        RECT 101.240 27.700 101.540 27.750 ;
        RECT 102.200 27.700 102.500 27.750 ;
        RECT 103.160 27.700 103.460 27.750 ;
        RECT 104.120 27.700 104.420 27.750 ;
        RECT 105.080 27.700 105.380 27.750 ;
        RECT 127.040 26.010 128.040 26.040 ;
        RECT 136.140 26.010 137.140 26.080 ;
        RECT 127.040 25.010 139.840 26.010 ;
        RECT 127.040 24.980 128.040 25.010 ;
        RECT 136.140 24.940 137.140 25.010 ;
        RECT 0.990 23.190 2.990 24.740 ;
        RECT 139.000 20.520 140.000 21.580 ;
        RECT 130.350 18.810 130.650 18.860 ;
        RECT 131.310 18.810 131.610 18.860 ;
        RECT 132.270 18.810 132.570 18.860 ;
        RECT 133.230 18.810 133.530 18.860 ;
        RECT 134.190 18.810 134.490 18.860 ;
        RECT 127.650 17.310 128.650 17.360 ;
        RECT 130.350 17.310 134.490 18.810 ;
        RECT 127.650 16.330 134.490 17.310 ;
        RECT 127.650 16.310 130.650 16.330 ;
        RECT 127.650 16.260 128.650 16.310 ;
        RECT 130.350 16.260 130.650 16.310 ;
        RECT 131.310 16.260 131.610 16.330 ;
        RECT 132.270 16.260 132.570 16.330 ;
        RECT 133.230 16.260 133.530 16.330 ;
        RECT 134.190 16.260 134.490 16.330 ;
        RECT 129.870 14.310 130.170 14.360 ;
        RECT 130.830 14.310 131.130 14.360 ;
        RECT 131.790 14.310 132.090 14.360 ;
        RECT 132.750 14.310 133.050 14.360 ;
        RECT 133.710 14.310 134.010 14.360 ;
        RECT 134.680 14.310 134.980 14.360 ;
        RECT 129.870 11.800 134.980 14.310 ;
        RECT 136.150 13.270 137.490 14.350 ;
        RECT 129.870 11.760 130.170 11.800 ;
        RECT 130.830 11.760 131.130 11.800 ;
        RECT 131.790 11.760 132.090 11.800 ;
        RECT 132.750 11.760 133.050 11.800 ;
        RECT 133.710 11.760 134.010 11.800 ;
        RECT 134.680 11.760 134.980 11.800 ;
        RECT 140.960 10.910 141.960 11.970 ;
      LAYER met3 ;
        RECT 129.990 224.850 130.370 225.170 ;
        RECT 132.750 224.880 133.130 225.200 ;
        RECT 83.970 219.465 85.080 221.035 ;
        RECT 85.980 219.475 87.090 221.045 ;
        RECT 87.970 219.475 89.080 221.045 ;
        RECT 89.970 219.485 91.080 221.055 ;
        RECT 91.980 219.465 93.090 221.035 ;
        RECT 93.970 219.455 95.080 221.025 ;
        RECT 122.315 220.730 122.645 220.745 ;
        RECT 130.030 220.730 130.330 224.850 ;
        RECT 122.315 220.430 130.330 220.730 ;
        RECT 122.315 220.415 122.645 220.430 ;
        RECT 126.465 220.010 126.795 220.025 ;
        RECT 132.790 220.010 133.090 224.880 ;
        RECT 137.940 221.465 139.040 222.025 ;
        RECT 126.465 219.710 133.090 220.010 ;
        RECT 126.465 219.695 126.795 219.710 ;
        RECT 130.445 219.330 130.775 219.345 ;
        RECT 133.810 219.330 134.130 219.370 ;
        RECT 130.445 219.030 134.130 219.330 ;
        RECT 130.445 219.015 130.775 219.030 ;
        RECT 133.810 218.990 134.130 219.030 ;
        RECT 48.930 212.625 51.060 215.755 ;
        RECT 0.950 207.065 3.030 210.345 ;
        RECT 116.790 204.870 117.270 205.290 ;
        RECT 116.860 202.930 117.160 204.870 ;
        RECT 116.760 202.480 117.160 202.930 ;
        RECT 48.920 200.485 51.010 202.015 ;
        RECT 116.860 200.230 117.160 202.480 ;
        RECT 116.710 199.780 117.160 200.230 ;
        RECT 0.960 194.865 3.040 197.775 ;
        RECT 116.860 196.840 117.160 199.780 ;
        RECT 110.830 196.540 117.160 196.840 ;
        RECT 110.830 188.790 111.130 196.540 ;
        RECT 110.680 188.340 111.130 188.790 ;
        RECT 48.940 186.155 51.080 187.755 ;
        RECT 110.830 185.890 111.130 188.340 ;
        RECT 110.630 185.290 111.130 185.890 ;
        RECT 0.960 181.435 3.050 183.305 ;
        RECT 0.950 175.795 3.040 177.585 ;
        RECT 110.830 177.490 111.130 185.290 ;
        RECT 102.750 177.190 111.130 177.490 ;
        RECT 102.750 173.005 103.160 177.190 ;
        RECT 115.190 176.500 115.800 176.630 ;
        RECT 116.580 176.500 117.430 176.525 ;
        RECT 115.190 176.200 117.430 176.500 ;
        RECT 115.190 176.080 115.800 176.200 ;
        RECT 116.580 176.175 117.430 176.200 ;
        RECT 107.650 174.920 108.000 174.945 ;
        RECT 120.320 174.920 121.370 174.945 ;
        RECT 107.650 174.570 121.370 174.920 ;
        RECT 107.650 174.545 108.000 174.570 ;
        RECT 120.320 174.545 121.370 174.570 ;
        RECT 48.940 171.375 51.080 172.975 ;
        RECT 102.750 172.475 103.250 173.005 ;
        RECT 106.930 171.000 107.310 171.025 ;
        RECT 106.930 170.850 107.810 171.000 ;
        RECT 106.930 170.610 107.680 170.850 ;
        RECT 106.930 170.585 107.310 170.610 ;
        RECT 110.015 169.975 110.345 170.305 ;
        RECT 110.030 169.175 110.330 169.975 ;
        RECT 110.015 168.845 110.345 169.175 ;
        RECT 126.660 168.935 127.130 171.000 ;
        RECT 0.950 166.885 3.060 168.425 ;
        RECT 48.950 161.925 51.030 164.035 ;
        RECT 0.940 95.805 3.050 97.305 ;
        RECT 55.160 90.215 56.160 91.385 ;
        RECT 136.430 88.420 137.550 88.445 ;
        RECT 136.430 87.270 149.170 88.420 ;
        RECT 136.430 87.245 137.550 87.270 ;
        RECT 117.955 85.920 119.005 85.945 ;
        RECT 117.955 84.920 138.010 85.920 ;
        RECT 117.955 84.895 119.005 84.920 ;
        RECT 48.940 81.705 51.020 84.665 ;
        RECT 136.450 79.110 138.050 79.215 ;
        RECT 136.450 78.210 151.040 79.110 ;
        RECT 136.450 78.095 138.050 78.210 ;
        RECT 74.480 75.005 75.480 76.165 ;
        RECT 0.950 69.065 3.040 70.565 ;
        RECT 136.130 60.060 137.560 60.155 ;
        RECT 136.130 59.160 152.760 60.060 ;
        RECT 136.130 59.105 137.560 59.160 ;
        RECT 48.940 55.015 51.030 56.495 ;
        RECT 0.950 50.045 3.050 51.545 ;
        RECT 55.160 44.385 56.160 45.555 ;
        RECT 136.300 42.580 137.760 42.605 ;
        RECT 148.170 42.580 149.170 42.590 ;
        RECT 136.300 41.440 149.170 42.580 ;
        RECT 136.300 41.430 149.070 41.440 ;
        RECT 136.300 41.405 137.760 41.430 ;
        RECT 136.120 40.130 137.540 40.175 ;
        RECT 107.500 40.125 137.540 40.130 ;
        RECT 107.450 39.090 137.540 40.125 ;
        RECT 107.450 39.065 109.070 39.090 ;
        RECT 136.120 39.065 137.540 39.090 ;
        RECT 48.940 35.885 51.040 38.825 ;
        RECT 136.450 33.270 138.050 33.335 ;
        RECT 136.440 32.380 151.040 33.270 ;
        RECT 136.440 32.370 150.750 32.380 ;
        RECT 136.450 32.285 138.050 32.370 ;
        RECT 74.480 29.175 75.480 30.335 ;
        RECT 0.940 23.215 3.040 24.715 ;
        RECT 136.100 14.260 137.540 14.325 ;
        RECT 136.100 13.360 137.490 14.260 ;
        RECT 151.760 13.360 152.760 14.260 ;
        RECT 136.100 13.295 137.540 13.360 ;
      LAYER met4 ;
        RECT 130.015 224.845 130.030 225.175 ;
        RECT 130.330 224.845 130.345 225.175 ;
        RECT 132.775 224.875 132.790 225.205 ;
        RECT 133.090 224.875 133.105 225.205 ;
        RECT 80.350 221.660 80.650 224.760 ;
        RECT 83.110 222.310 83.410 224.760 ;
        RECT 85.870 223.080 86.170 224.760 ;
        RECT 88.630 223.800 88.930 224.760 ;
        RECT 88.630 223.500 90.650 223.800 ;
        RECT 85.870 222.780 88.640 223.080 ;
        RECT 83.110 222.010 86.650 222.310 ;
        RECT 80.350 221.360 84.660 221.660 ;
        RECT 84.360 221.015 84.660 221.360 ;
        RECT 86.350 221.025 86.650 222.010 ;
        RECT 88.340 221.025 88.640 222.780 ;
        RECT 90.350 221.035 90.650 223.500 ;
        RECT 91.390 223.180 91.690 224.760 ;
        RECT 91.390 222.880 92.690 223.180 ;
        RECT 5.920 217.230 6.000 220.760 ;
        RECT 38.690 220.500 41.220 220.890 ;
        RECT 5.920 211.290 48.990 217.230 ;
        RECT 50.910 215.735 50.990 220.760 ;
        RECT 84.015 219.485 85.035 221.015 ;
        RECT 86.025 219.495 87.045 221.025 ;
        RECT 88.015 219.495 89.035 221.025 ;
        RECT 90.015 219.505 91.035 221.035 ;
        RECT 92.390 221.015 92.690 222.880 ;
        RECT 94.150 221.500 94.450 224.760 ;
        RECT 124.510 223.150 124.810 224.760 ;
        RECT 115.350 222.850 124.810 223.150 ;
        RECT 92.025 219.485 93.045 221.015 ;
        RECT 94.150 221.005 94.470 221.500 ;
        RECT 94.015 219.475 95.035 221.005 ;
        RECT 50.910 212.645 51.015 215.735 ;
        RECT 0.995 207.085 1.000 210.325 ;
        RECT 5.920 196.140 6.000 211.290 ;
        RECT 48.965 200.505 48.990 201.995 ;
        RECT 5.920 190.200 48.990 196.140 ;
        RECT 3.000 181.455 3.005 183.285 ;
        RECT 0.995 175.815 1.000 177.565 ;
        RECT 5.920 176.950 6.000 190.200 ;
        RECT 50.910 187.735 50.990 212.645 ;
        RECT 48.985 186.175 48.990 187.735 ;
        RECT 50.910 186.175 51.035 187.735 ;
        RECT 5.920 171.010 48.990 176.950 ;
        RECT 50.910 172.955 50.990 186.175 ;
        RECT 115.350 176.635 115.650 222.850 ;
        RECT 127.270 221.700 127.570 224.760 ;
        RECT 135.550 223.560 135.850 224.760 ;
        RECT 116.900 221.400 127.570 221.700 ;
        RECT 133.820 223.260 135.850 223.560 ;
        RECT 138.310 223.530 138.610 224.780 ;
        RECT 116.900 205.295 117.200 221.400 ;
        RECT 133.820 219.345 134.120 223.260 ;
        RECT 137.940 222.280 139.050 223.530 ;
        RECT 137.990 221.490 138.990 222.000 ;
        RECT 133.805 219.015 134.135 219.345 ;
        RECT 116.835 204.865 117.225 205.295 ;
        RECT 115.235 176.075 115.755 176.635 ;
        RECT 50.910 171.395 51.035 172.955 ;
        RECT 0.995 166.905 1.000 168.405 ;
        RECT 3.000 166.905 3.015 168.405 ;
        RECT 5.920 157.290 6.000 171.010 ;
        RECT 5.920 151.350 48.990 157.290 ;
        RECT 0.985 95.825 1.000 97.285 ;
        RECT 3.000 95.825 3.005 97.285 ;
        RECT 5.920 78.620 6.000 151.350 ;
        RECT 48.985 81.725 48.990 84.645 ;
        RECT 5.920 72.680 48.990 78.620 ;
        RECT 0.995 69.085 1.000 70.545 ;
        RECT 0.995 50.065 1.000 51.525 ;
        RECT 3.000 50.065 3.005 51.525 ;
        RECT 5.920 46.150 6.000 72.680 ;
        RECT 48.985 55.035 48.990 56.475 ;
        RECT 5.920 40.210 48.990 46.150 ;
        RECT 0.985 23.235 1.000 24.695 ;
        RECT 5.920 19.020 6.000 40.210 ;
        RECT 50.910 38.805 50.990 171.395 ;
        RECT 55.210 91.365 56.110 91.410 ;
        RECT 55.205 90.235 56.115 91.365 ;
        RECT 55.210 45.535 56.110 90.235 ;
        RECT 148.220 88.425 149.120 88.440 ;
        RECT 148.215 87.265 149.125 88.425 ;
        RECT 74.530 76.145 75.430 76.190 ;
        RECT 74.525 75.025 75.435 76.145 ;
        RECT 55.205 44.405 56.115 45.535 ;
        RECT 48.985 35.905 48.990 38.805 ;
        RECT 50.910 35.905 50.995 38.805 ;
        RECT 5.920 13.080 48.990 19.020 ;
        RECT 5.920 5.000 6.000 13.080 ;
        RECT 50.910 5.000 50.990 35.905 ;
        RECT 5.200 4.990 6.000 5.000 ;
        RECT 16.570 4.560 17.470 4.920 ;
        RECT 35.890 4.380 36.790 4.920 ;
        RECT 55.210 1.000 56.110 44.405 ;
        RECT 74.530 30.315 75.430 75.025 ;
        RECT 148.220 42.595 149.120 87.265 ;
        RECT 150.090 79.115 150.990 79.150 ;
        RECT 150.085 78.205 150.995 79.115 ;
        RECT 148.215 41.435 149.125 42.595 ;
        RECT 74.525 29.195 75.435 30.315 ;
        RECT 74.530 1.000 75.430 29.195 ;
        RECT 148.220 6.990 149.120 41.435 ;
        RECT 150.090 33.275 150.990 78.205 ;
        RECT 151.815 59.160 152.715 60.065 ;
        RECT 151.810 59.155 152.715 59.160 ;
        RECT 150.085 32.375 150.995 33.275 ;
        RECT 113.170 6.090 149.120 6.990 ;
        RECT 93.850 1.000 94.750 4.920 ;
        RECT 113.170 1.000 114.070 6.090 ;
        RECT 132.490 4.690 133.390 4.920 ;
        RECT 150.090 4.690 150.990 32.375 ;
        RECT 151.810 14.265 152.710 59.155 ;
        RECT 151.805 13.355 152.715 14.265 ;
        RECT 132.490 3.790 150.990 4.690 ;
        RECT 132.490 1.000 133.390 3.790 ;
        RECT 151.810 1.000 152.710 13.355 ;
  END
END tt_um_ece298A_analog_r1
END LIBRARY

